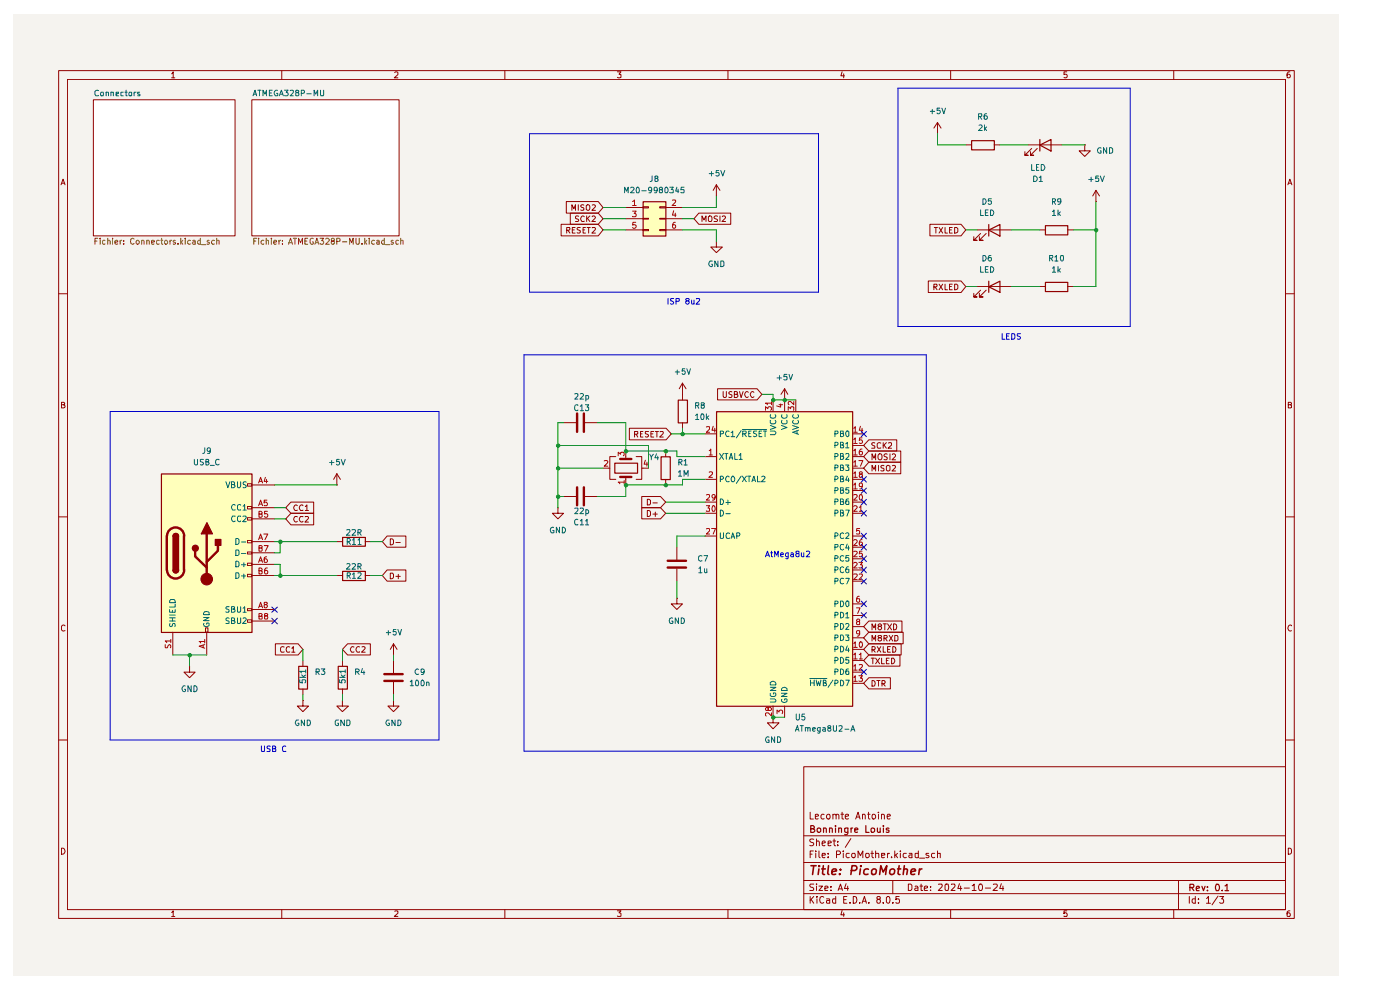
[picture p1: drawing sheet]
<svg xmlns="http://www.w3.org/2000/svg" width="297mm" height="210mm" viewBox="0 0 297 210" stroke-linecap="round" stroke-linejoin="round" font-family="sans-serif">
<path d="M2.9 3h281.2v203.8h-281.2z" fill="#f5f3ef"/>
<g fill="none" stroke="#910000" stroke-width=".21">
<path d="M12.4 15h262.2v179.8h-262.2zM14.3 16.8h258.4v176.2h-258.4zM36.4 15.7l.3-.5v1.3M36.4 16.5h.7M59.8 15v1.8M83.7 15.4l.2-.2h.3l.2 .2v.4l-.8 .7h.8M107.1 15v1.8M131 15.2h.7l-.4 .5 .4 .1v.6h-.7M154.4 15v1.8M178.6 15.2l-.2 .9h.8M179 15.7v.8M201.7 15v1.8"/>
<path d="M226.3 15.2h-.6v.6l.4-.1 .3 .3-.1 .4h-.6M249 15v1.8M273.6 15.2l-.4 .1-.2 .3v.8h.6v-.6l-.4-.1-.2 .3M13 39.2l.4-1.2 .4 1.2M13.1 38.9h.6M273.2 39.2l.4-1.2 .5 1.2M273.3 38.9h.6M12.4 62.3h1.9M272.7 62.3h1.9M13 85.8h.5l.2-.3-.2-.2h-.5v1.2h.5l.3-.4-.3-.3M273.3 85.8h.5l.2-.3-.2-.2h-.5v1.2h.5l.2-.1v-.4l-.3-.2M12.4 109.6h1.9"/>
<path d="M272.7 109.6h1.9M13.8 132.8l-.4-.2-.4 .3 .1 .8 .3 .2 .4-.1M274 132.8l-.2-.2a.6 .6 0 0 0-.6 .7 .6 .6 0 0 0 .8 .5M12.4 157h1.9M272.7 157h1.9M13 179.9a.65 .65 0 0 1 .8 .6 .65 .65 0 0 1-.8 .7zM170.5 162.6h102.2v30.4h-102.2zM170.5 177.3h102.2M171.9 172.3v1.4h.6M172.6 178.1h-.7l-.1 .3 .2 .2 .5 .1 .1 .4-.3 .3-.5-.1M173 173.2l.6-.1v-.3h-.6v.8h.6M173.2 178.6l.2-.2 .3 .1 .1 .9"/>
<path d="M173.2 178v1.4M174.4 178.9l.7-.2-.2-.3-.4 .1-.1 .7 .3 .2 .3-.1M174.8 172.8l-.4-.1a.6 .6 0 0 0 0 1l.4-.1M175.7 178.9l.7-.2-.1-.2h-.6v.8h.6M176.7 172.9l.1-.1a.36 .36 0 0 1 .6 .2v.7M176.7 178.4h.6M176.7 172.7v1M177 178v1.2l.3 .2M177.4 173v-.2a.36 .36 0 0 1 .6 .2v.7M177.7 179.2v.2M177.7 178.5v.1M178.4 172.7h.6"/>
<path d="M178.6 172.3v1.3l.4 .1M179.3 173.2l.7-.1v-.3l-.4-.1-.3 .3 .1 .6h.6M180.5 177.9l-1.2 1.8M181.5 173.7l.5-1.4 .5 1.4M181.7 173.3h.7M183 172.9l.1-.2 .4 .1 .1 .9M183 172.7v1M184.1 172.7h.5M184.2 172.3v1.2l.4 .2M186.3 172.3v.1M186.3 172.7v1M187 172.9v-.1a.36 .36 0 0 1 .6 .2v.7"/>
<path d="M187 172.7v1M188.2 173.2l.7-.1-.2-.4-.4 .1-.1 .7 .2 .2 .4-.1M273.3 179.9l.5 .1 .2 .3v.5l-.4 .4h-.3zM36.4 193.5l.3-.3v1.2M36.4 194.4h.7M59.8 193v1.8M83.7 193.3h.7v.4l-.8 .7h.8M107.1 193v1.8M131 193.2h.7l-.4 .4 .4 .2v.5h-.7M154.4 193v1.8M170.5 189.6h102.2M170.5 186.8h102.2"/>
<path d="M170.5 183h102.2M171.9 190.2v1.4M171.9 181.2h.4M172 190.8l.6 .8M172.5 180.5h-.6v1.4M172.6 187.5l-.7 .1v.4l.6 .3 .1 .3-.1 .3h-.7M172.6 190.2l-.7 .8M173.1 180.5v.2M173.1 181v.9M173.2 187.5v.1M173.2 188v.9M173.3 190.2v.1"/>
<path d="M173.3 190.7v.9M173.7 188h.8l-.8 .9h.8M173.7 180.5v1.2l.3 .2M174.4 181.4h.7l-.1-.4h-.5l-.1 .2 .1 .7h.5M174.7 190.3l-.4-.1a.7 .7 0 0 0-.4 .8 .7 .7 0 0 0 .8 .5v-.1M175 188.5l.7-.2-.1-.3h-.6v.9h.6M175.3 190.7h.6l.1 .9M175.7 181.8v.1M175.7 181v.2M176 191l-.7 .1v.4h.7M176.3 188.8v.1M176.3 188v.2"/>
<path d="M177.3 190.7h-.6l-.1 .2 .1 .6h.6M177.3 190.2v1.4M177.5 181.3h.6l.2-.3v-.2l-.2-.3h-.6v1.4M177.8 188.9l.5-1.4 .4 1.4M178 188.5h.6M178.6 193.1l-.2 1h.8M178.9 180.5v.2M178.9 181v.9M179 193.6v.8M179 190.8h.5M179.5 187.4l-.3 1.1h.8M179.7 190.2h-.7v1.4h.7"/>
<path d="M179.8 188v.9M180.2 181h-.5l-.2 .3v.4l.2 .2h.5M180.3 191.4v.2M180.8 181.1l.6-.1v.9a.45 .45 0 0 1-.7-.2zM181 190.2h.4a.75 .75 0 0 1 .4 .8 .75 .75 0 0 1-.8 .6zM182 181.9v-1.4l.5 1 .5-1v1.4M182.4 191.4v.2M182.9 191.6l.5-1.4 .4 1.4M183 191.2h.7M183.7 181h.5l.2 .7a.45 .45 0 0 1-.7 .2zM184.3 191.4v.2M184.7 181h.6"/>
<path d="M185 180.5v1.2l.3 .2M185.8 181.1l.5-.1 .1 .9M185.8 180.5v1.4M186.3 190.8l-.3-.3 .3-.3h.4v.5a.56 .56 0 0 0-.6 .2 .56 .56 0 0 0 0 .6h.6l.1-.5-.3-.2M187 181.4h.7l-.1-.4h-.6v.9h.6M187.4 191.4v.2M188 190.4l.4-.2a.8 .8 0 0 1 .4 .7 .8 .8 0 0 1-.4 .7l-.4-.3zM188.3 181v.9M188.7 181h-.3l-.1 .3M189.1 181.8v.1M189.4 191.4v.2M189.4 186.8v2.8"/>
<path d="M189.8 180.5v1.4M190 181.4l.4 .5M190.4 181l-.6 .5M190.8 190.2h-.7v.6l.1-.1 .6 .1v.7l-.6 .1-.1-.2M191 180.5v.2M191 181v.9M192.3 181h-.5l-.2 .3v.4l.3 .2h.4M192.7 187.5h.5l.3 .4v.6l-.3 .4h-.5zM192.9 181h.6v.9M193.5 181.4h-.5l-.2 .2 .2 .3h.5M194.1 188h.4l.2 .2v.7h-.6v-.4l.6-.2M194.8 181l-.7 .1v.7l.3 .1h.4"/>
<path d="M194.8 180.5v1.4M195.1 182h1.1M195.2 188h.5M195.4 187.5v1.4h.3M196.1 188.5l.7-.2v-.3h-.5l-.2 .2 .1 .7h.6M197 181h-.5l-.1 .2 .6 .3v.4h-.6M197.4 188.8v.1M197.4 188v.2M198.3 181h-.5l-.2 .3v.4l.3 .2h.4M198.9 181.1l.6-.1v.9M198.9 180.5v1.4M199.1 187.6l.7-.1 .1 .4-.9 1h.9"/>
<path d="M200.6 187.6h.6v.8l-.1 .5h-.4l-.2-.3zM201.7 193v1.8M201.8 187.6l.7-.1 .1 .4-.8 1h.8M203.5 187.4l-.3 1.1h.8M203.8 188v.9M204.6 188.4h1.1M206.2 187.9l.5-.4v1.4M206.2 188.9h.9M207.9 187.5a.73 .73 0 0 1 .6 .6 .73 .73 0 0 1-.3 .8h-.3l-.3-.5zM209 188.4h1.1M210.7 187.6l.7-.1 .2 .4-.1 .2-.9 .8h1M212.4 187.4l-.3 1.1h.8"/>
<path d="M212.8 188v.9M226.3 193.2h-.6v.6l.2-.2 .4 .1v.7l-.6-.1M249 193v1.8M250 186.8v6.2M252.3 190.2v1.4M253.6 190.7h-.5l-.2 .2v.4l.2 .3 .5-.1M253.6 190.2v1.4M254.3 191.4v.2M254.3 190.7v.1M255.9 190.6l.5-.4v1.4M255.9 191.6h.9M258.4 190.1l-1.3 1.8"/>
<path d="M258.7 190.2h.9l-.4 .5 .3 .1v.7l-.6 .1-.2-.2M273.6 193.2l-.6 .3v.8l.6 .1v-.7l-.4-.1-.2 .3"/>
<circle cx="175.7" cy="173.3" r=".48"/>
<circle cx="185.4" cy="173.3" r=".48"/>
</g>
<g fill="none" stroke="#910000" stroke-width=".25">
<path d="M172 175.8l.7-.1 .1-.3-.3-.3h-.5v1.5h.5l.3-.3v-.2l-.3-.3M173.4 175.7l.5-.1 .2 .3v.4l-.2 .3h-.3l-.2-.3zM174.7 175.7l.4-.1 .2 .2v.8M174.7 175.6v1M176 175.7l.4-.1 .2 .2v.8M176 175.6v1M177.2 175.1v.2M177.2 175.6v1M177.9 175.7h.6v.9M177.9 175.6v1M179.9 175.6l-.1 1.3-.3 .2-.3-.1M179.9 175.7h-.7v.7l.2 .2 .5-.1"/>
<path d="M180.5 175.6v1M180.9 175.6l-.4 .1v.2M181.3 176.1l.7-.1-.2-.4-.5 .2v.6l.3 .2 .3-.1M183.7 175.1v1.5h.7M184.9 175.7h.6v.6a.45 .45 0 0 1-.6 .2zM186.1 175.6v.8l.2 .2 .4-.2M186.7 175.6v1M187.4 175.1v.2M187.4 175.6v1M188.6 175.7l-.3-.1-.3 .2 .1 .3h.5v.4h-.6M252.4 188.3h.7l.2-.3-.1-.3-.8-.1v1.3M252.8 188.3l.5 .6"/>
<path d="M253.8 188.5l.7-.2-.2-.3-.4 .1-.1 .7 .1 .1h.5M255 188l.3 .9 .3-.9M256.2 188.8v.1M256.2 188.1v.2M258 187.6a.73 .73 0 0 1 .8 .5 .73 .73 0 0 1-.4 .8h-.4l-.2-.5zM259.3 188.8v.1M259.9 187.9l.4-.3v1.3M259.9 188.9h.7"/>
</g>
<g fill="none" stroke="#910000" stroke-width=".34">
<path d="M172 183.6h1.1M172.6 183.6l-.2 1.9M173.7 184.3l-.1 1.2M173.8 183.6l-.1 .2 .2-.1-.1-.1-.1 .2M174.3 184.3h.8M174.7 183.6l-.2 1.6 .4 .3M175.8 183.6l-.2 1.6 .2 .3M176.5 184.9l1-.2-.1-.3a.6 .6 0 0 0-.9 .2v.8h.8M178.1 185.3v.2M178.3 184.4v.2M180.6 184.7l.9-.1 .3-.3-.1-.5-.3-.2h-.6l-.3 1.9M182.5 184.3l-.1 1.2"/>
<path d="M182.6 183.6v.2M184.2 184.4a.65 .65 0 0 0-.9 .3v.6a.64 .64 0 0 0 .8 .1M184.9 184.7l.4-.4 .5 .1 .1 .3-.1 .5a.56 .56 0 0 1-.9 .1zM186.6 185.5l.3-1.9 .5 1.4 .7-1.4-.2 1.9M188.9 184.5l.3-.2 .5 .2v.8l-.4 .2-.5-.2zM190.4 184.3h.7M190.8 183.6l-.3 1.6 .4 .3M191.7 184.5l.3-.2 .4 .1v1.1M191.9 183.6l-.3 1.9M193.3 184.9l.9-.2-.1-.3a.6 .6 0 0 0-.8 .2v.8h.8M195.1 184.3l-.2 1.2M195.6 184.3l-.4 .1-.1 .3"/>
</g>
<g fill="#fff">
<path d="M53.4 21.2h31.3v28.8h-31.3z"/>
<path d="M19.8 21.2h30.1v28.8h-30.1z"/>
</g>
<g fill="#ffb">
<path d="M136.4 42.8h4.8v7.2h-4.8z"/>
<path d="M34.2 100.5h19.2v33.6h-19.2z"/>
<path d="M152 87.3h28.8v62.5h-28.8z"/>
</g>
<g fill="none" stroke="#910000" stroke-width=".21">
<path d="M19.8 21.2h30.1v28.8h-30.1zM53.4 21.2h31.3v28.8h-31.3zM152 39.2l-.7 1.2M152 39.2v2.4M152 39.2l.7 1.2M198.9 28.4h.1M198.9 26l-.8 1.2M198.9 26v2.4M198.9 26l.7 1.2M204.9 30.7h1.2M210.9 30.7h1.2M218.1 30.7h7.2"/>
<path d="M218.9 31.5l-1.5 1.4h.7h-.7v-.7M220 31.5l-1.4 1.4h.7h-.7v-.7M230.1 30.7v1.3h1.2l-1.2 1.2-1.2-1.2h1.2M230.1 30.7h.1M119 47.6h7.9l1 1.2-1 1.2h-7.9zM120.1 42.8h6.8l1 1.2-1 1.2h-6.8zM120.2 48.8h.6v-.5h-.6v1.1M120.5 48.8l.4 .6M121 45.2h5.9l1 1.2-1 1.2h-5.9zM121.3 44.6v-1.2l.4 .9 .4-.9v1.2M121.4 48.8h.4M122 48.3h-.6v1.1h.6"/>
<path d="M122.7 43.4v1.2M122.8 45.9l-.5-.1-.2 .2v.3l.7 .3-.2 .4h-.5M123.1 48.3h-.5l-.2 .1 .2 .4 .5 .1v.4l-.2 .1h-.5M123.7 48.8h.3M123.9 43.5l-.5-.1-.2 .3 .2 .3 .5 .2v.3h-.7M123.9 46l-.2-.2a.67 .67 0 0 0-.5 .5 .67 .67 0 0 0 .2 .7l.5-.1M124.2 48.3h-.5v1.1h.5M124.4 43.6l.5-.2a.65 .65 0 0 1 .3 .7 .65 .65 0 0 1-.6 .5l-.2-.2zM124.5 45.8v1.2M124.5 48.3h.7M124.6 46.3l.5 .7M124.9 48.3v1.1"/>
<path d="M125.1 45.8l-.6 .7M125.6 48.3h.6l.1 .3-.7 .8h.7M125.6 46l.5-.2 .2 .3-.7 .9h.7M125.6 43.5l.5-.1 .2 .4-.7 .8h.7M132.8 48.8h3.6M132.8 44h3.6M132.8 46.4h3.6M136.4 48.7h1.2v.2h-1.2zM136.4 46.3h1.2v.2h-1.2zM136.4 43.9h1.2v.2h-1.2zM140 48.7h1.2v.2h-1.2zM140 46.3h1.2v.2h-1.2z"/>
<path d="M140 43.9h1.2v.2h-1.2zM141.2 48.8h3.6M141.2 44h3.6M141.2 46.4h3.6M148.2 45.2h6.8v2.4h-6.8l-1-1.2zM148.9 47v-1.2l.4 .8 .5-.8v1.2M150.3 46l.5-.2a.86 .86 0 0 1 .1 1.2h-.5l-.1-.2zM152 51.2v1.2h1.2l-1.2 1.2-1.2-1.2h1.2M152 51.2h.1M152 41.6h.1M152.2 45.9l-.5-.1-.2 .3 .1 .2 .5 .2 .1 .3-.1 .2h-.6M152.7 45.8v1.2"/>
<path d="M153.2 46l.5-.2 .2 .3-.7 .9h.7M196.9 59.6h7l1 1.2-1 1.3h-7zM197.3 47.6h6.6l1 1.2-1 1.2h-6.6zM198.2 48.3h.7M198.5 48.3v1.1M199.2 48.3l.8 1.1M200 48.3l-.8 1.1M200.5 48.3v1.1h.5M201.4 48.8h.4M202 48.3h-.6v1.1h.6M202.5 48.3h.4l.3 .2v.6l-.4 .3h-.3zM207.3 48.8h7.2"/>
<path d="M208 49.5l-1.4 1.5h.7h-.7v-.8M209.2 49.5l-1.4 1.5h.7h-.7v-.8M220.6 48.8h1.1M226.5 48.8h1.2M232.5 42.8h.1M232.5 40.4l-.7 1.2M232.5 40.4v2.4M232.5 40.4l.8 1.2M198.1 60.9l.6-.1v-.5h-.6v1.2M198.4 60.9l.4 .6M199.2 60.3l.8 1.2M200 60.3l-.8 1.2"/>
<path d="M200.5 60.3v1.2h.5M201.4 60.8h.4M202 60.3h-.6v1.2h.6M202.5 60.3h.4l.3 .2v.6l-.4 .4h-.3zM207.3 60.8h7.2M208 61.5l-1.4 1.5h.7h-.7v-.8M209.2 61.5l-1.4 1.5h.7h-.7v-.8M220.6 60.8h1.1M226.5 60.8h1.2M152.2 82.5h8.4l1 1.1-1 1.2h-8.4zM153.4 83.1v1l.3 .2 .4-.1v-1.1M155.3 83.1h-.4l-.3 .2 .1 .3 .6 .2v.4l-.2 .1-.5-.1"/>
<path d="M155.8 83.6h.6v-.5h-.6v1.2h.5l.2-.4-.3-.3M156.9 83.1l.3 1.2 .4-1.2M158.7 83.2l-.2-.1a.65 .65 0 0 0-.5 .6 .65 .65 0 0 0 .5 .6l.2-.1M159.9 83.2l-.2-.1a.65 .65 0 0 0-.5 .6 .65 .65 0 0 0 .5 .6l.2-.1M166.5 84.8h.1M166.5 82.5l-.8 1.1M166.5 82.5v2.3M166.5 82.5l.6 1.1M184.3 93.3h5.9v2.4h-5.9l-1.1-1.2zM184.3 95.7h6.8v2.3h-6.8l-1.1-1.1zM184.3 98h6.8v2.5h-6.8l-1.1-1.2zM185 97.5v-1.2l.4 .9 .4-.9v1.2"/>
<path d="M185 99.9v-1.2l.4 .9 .4-.9v1.2M185.6 94l-.4-.1-.3 .2 .3 .4 .4 .2v.3l-.7 .1M186.3 98.7v1.2M186.4 96.3h.5a.86 .86 0 0 1 0 1.2 .46 .46 0 0 1-.6-.4zM186.9 94h-.1a.45 .45 0 0 0-.7 .1v.7l.2 .3 .6-.1M187.4 93.9v1.2M187.5 98.8l-.4-.1-.2 .3 .2 .3 .4 .2v.3h-.6M187.5 94.4l.5 .7M188 98.9l.3-.2 .5 .2v.8l-.3 .2-.5-.2zM188 93.9l-.6 .7M188.2 96.3h-.4l-.3 .2 .2 .4 .5 .1v.4l-.2 .1-.5-.1M188.5 94h.6v.4l-.7 .7h.7"/>
<path d="M188.8 96.3v1.2M189.3 96.4l.4-.1 .3 .4-.8 .8h.8M189.3 98.8l.4-.1 .3 .4-.8 .8h.8M52.5 119.5h.9v.5h-.9zM52.5 117.1h.9v.4h-.9zM52.5 114.6h.9v.5h-.9zM52.5 109.8h.9v.5h-.9zM52.5 107.4h.9v.5h-.9zM52.5 102.6h.9v.5h-.9zM61.7 108.9h4.8v2.4h-4.8l-1.1-1.2zM61.7 106.5h4.8v2.4h-4.8l-1.1-1.2zM63.1 109.6h-.5a.67 .67 0 0 0-.3 .6 .67 .67 0 0 0 .5 .5l.3-.1"/>
<path d="M63.1 107.3l-.3-.2a.67 .67 0 0 0-.5 .5 .67 .67 0 0 0 .3 .7l.5-.1M64.3 109.6h-.5a.66 .66 0 0 0-.3 .7 .66 .66 0 0 0 .6 .4l.2-.1M64.3 107.3l-.2-.2a.66 .66 0 0 0-.6 .5 .66 .66 0 0 0 .3 .7l.5-.1M64.8 109.6h.5l.1 .3-.7 .8h.7M64.8 107.4l.3-.3v1.2M64.8 108.3h.6M43.6 133.2h.5v.9h-.5zM52.5 131.5h.9v.5h-.9zM52.5 129.1h.9v.4h-.9zM52.5 121.8h.9v.5h-.9zM184.3 134.1h7.3v2.5h-7.3l-1.1-1.3zM184.3 138.9h6.6v2.4h-6.6l-1.1-1.2z"/>
<path d="M184.3 131.7h7v2.4h-7l-1.1-1.2zM184.3 136.6h6.9v2.3h-6.9l-1.1-1.2zM184.8 139.6h.7M185 136v-1.2l.4 .8 .4-.8v1.2M185 133.6v-1.3l.4 .9 .4-.9v1.3M185 137.8l.6-.1v-.5h-.6v1.1M185.2 139.6v1.2M185.2 137.8l.5 .5M185.8 139.6l.8 1.2M186.1 137.2l.8 1.1M186.5 135.3l-.2-.3 .1-.2h.5l.1 .2-.2 .3h-.4l-.1 .2 .2 .5h.3l.2-.3-.2-.4M186.5 132.8l-.2-.2 .2-.3h.3l.2 .4-.7 .4v.2l.2 .3h.3l.2-.3v-.2l-.2-.3"/>
<path d="M186.6 139.6l-.8 1.2M186.9 137.2l-.8 1.1M187 139.6v1.2h.6M187.4 137.2v1.1h.5M187.4 132.3h.6M187.5 135.4l.6-.1 .1-.3-.2-.2h-.5v1.2M187.7 132.3v1.3M187.8 135.4l.4 .6M188.3 132.3l.8 1.3M188.3 137.7h.4M188.6 139.6h-.6v1.2h.6M188.6 134.8l.8 1.2"/>
<path d="M188.9 137.2h-.6v1.1h.6M189.1 139.6h.5a.66 .66 0 0 1 .2 .8 .66 .66 0 0 1-.7 .4zM189.1 132.3l-.8 1.3M189.4 137.2a.66 .66 0 0 1 .7 .4 .66 .66 0 0 1-.3 .7h-.4zM189.4 134.8l-.8 1.2M189.6 132.3a.64 .64 0 0 1 .7 .7 .64 .64 0 0 1-.7 .6zM189.8 134.8h.5l.2 .2v.7l-.3 .3h-.4zM184.3 143.8h4.6v2.3h-4.6l-1.1-1.2zM185 144.4a.66 .66 0 0 1 .6 .4 .66 .66 0 0 1-.2 .7h-.4zM186 144.4h.7M186.3 144.4v1.1M187.1 145l.6-.1v-.5h-.6v1.1"/>
<path d="M187.4 145l.4 .5M188 140.1h.4"/>
</g>
<path d="M206.1 29.8h4.8v2h-4.8zM220.6 30.8l2.4-1.2v2.4zM220.6 29.6v2.4M136.4 42.8h4.9v7.3h-4.9zM209.8 48.8l2.3-1.2v2.5zM209.8 47.6v2.5M209.8 59.6v2.4M221.8 47.9h4.7v1.9h-4.7zM221.8 59.9h4.7v1.9h-4.7zM209.8 60.8l2.3-1.2v2.4zM34.2 100.5h19.3v33.7h-19.3zM36.7 120.9a.59 .59 0 0 0 .6 .6 .59 .59 0 0 0 .6-.6" fill="none" stroke="#910000" stroke-width=".25"/>
<path d="M134.2 42.8l.4-.4v1.2M134.2 44.8h.8l-.5 .5 .5 .2v.3l-.2 .2-.6-.1M134.2 43.6h.8M134.9 47.2h-.6l-.1 .5h.7l.1 .5-.3 .2h-.3l-.2-.1M142.7 42.5l.6-.1v.4l-.7 .8h.7M142.9 44.7l-.2 .9h.7M143.3 47.2a.72 .72 0 0 0-.6 .5 .72 .72 0 0 0 .2 .7l.4-.1v-.4a.35 .35 0 0 0-.3-.2 .35 .35 0 0 0-.3 .2M143.3 45.2v.8" fill="none" stroke="#b90000" stroke-width=".21"/>
<path d="M35.4 120.9a1.82 1.82 0 0 0 1.9 1.8 1.82 1.82 0 0 0 1.8-1.8" fill="none" stroke="#910000" stroke-width=".51"/>
<path d="M36.7 120.9h1.2a.59 .59 0 0 1-.6 .6 .59 .59 0 0 1-.6-.6z" fill="#910000"/>
<path d="M36.7 113.7h1.2v7.2h-1.2z" fill="none" stroke="#910000" stroke-width=".25"/>
<path d="M36.7 113.7h1.2v7.2h-1.2z" fill="#910000"/>
<path d="M36.7 113.7a.59 .59 0 0 1 .6-.5 .59 .59 0 0 1 .6 .5" fill="none" stroke="#910000" stroke-width=".25"/>
<path d="M36.9 113.3a.59 .59 0 0 1 .6-.1 .59 .59 0 0 1 .4 .5h-1.2z" fill="#910000"/>
<path d="M35.4 113.7a1.82 1.82 0 0 1 1.9-1.8 1.82 1.82 0 0 1 1.8 1.8" fill="none" stroke="#910000" stroke-width=".51"/>
<circle cx="41.4" cy="116.3" r=".64" fill="none" stroke="#910000" stroke-width=".25"/>
<circle cx="41.4" cy="116.3" r=".64" fill="#910000"/>
<circle cx="43.9" cy="122.8" r="1.23" fill="none" stroke="#910000" stroke-width=".21"/>
<circle cx="43.9" cy="122.8" r="1.23" fill="#910000"/>
<path d="M35.4 113.7v7.2M39 113.7v7.2M41.4 116.8v1.2l2.5 2.4M43.9 113.2v9.6M46.2 115.7v1.1l-2.3 2.4" fill="none" stroke="#910000" stroke-width=".51"/>
<path d="M43.9 110.9l1.2 2.3h-2.4z" fill="none" stroke="#910000" stroke-width=".25"/>
<path d="M43.9 110.9l1.2 2.3h-2.4z" fill="#910000"/>
<path d="M45.7 114.4h1.2v1.3h-1.2z" fill="none" stroke="#910000" stroke-width=".25"/>
<path d="M45.7 114.4h1.2v1.3h-1.2z" fill="#910000"/>
<g fill="none" stroke="#910000" stroke-width=".21">
<path d="M119.5 89.7h2.7M124.1 89.7h2.6M127.9 99.3h1.5M130.6 96.9h-1.2v4.8h1.2M132.8 95.7v1.7M133.5 90.8h7.8l1.1 1.2-1.1 1.3h-7.8zM134.6 92.1l.7-.1v-.4l-.7-.1v1.2M135 96.9h1.1v4.8h-1.1M135 92.1l.3 .6M135.9 92h.3M136.1 99.3h1.5M136.4 91.5h-.5v1.2h.5"/>
<path d="M137.6 91.5h-.6l-.1 .4a.57 .57 0 0 1 .6 .7h-.6M138.1 92h.4M138.7 91.5h-.6v1.2h.6M139 91.5h.7M139.4 91.5v1.2M140 91.6l.6-.1 .1 .4-.7 .8h.7M141.2 95.7v1.2M144.8 83.6h.1M144.8 81.3l-.7 1.2M144.8 81.3v3.5M144.8 89.7v1.1M144.8 81.3l.7 1.2"/>
<path d="M149.6 92h2.4M149.6 96.9h2.4M164 84.8v2.5M166.5 84.8v2.5M168.8 84.8v2.5M180.8 92h2.4M180.8 99.3h2.4M180.8 96.9h2.4M180.8 94.5h2.4M53.4 102.9h4.8M53.4 107.7h4.8M53.4 119.7h4.8"/>
<path d="M53.4 114.9h4.8M53.4 110.1h4.8M53.4 117.3h4.8M71.5 102.9h.1M71.5 114.9h1.1M71.5 100.5l-.7 1.2M71.5 100.5v2.4M71.5 100.5l.7 1.2M77.5 114.9h1.2M82.1 113.7h4v2.4h-4l-1-1.2zM82.8 114.3l.5 .1 .2 .2v.6l-.4 .4h-.3zM84 115.1h.9"/>
<path d="M118.4 107.7v1.2h1.1l-1.1 1.2-1.2-1.2h1.2M118.4 107.7h.1M119.5 105.3h2.7M124.1 105.3h2.6M132.8 101.2v1.7M136.1 107.7h4l1.1 1.2-1.1 1.2h-4zM136.1 105.3h4l1.1 1.2-1.1 1.2h-4zM137.3 108.3h.4l.3 .3v.6l-.3 .4h-.4zM137.3 105.9h.4l.3 .3v.6l-.2 .3h-.5zM138.5 109h.9M138.5 106.7h.9M139 108.6v1"/>
<path d="M141.2 101.7v1.2M143.6 116.1v2.7M149.6 101.7h2.4M149.6 106.5h2.4M149.6 108.9h2.4M149.6 113.7h2.4M180.8 101.7h2.4M180.8 104.1h2.4M180.8 106.5h2.4M180.8 108.9h2.4M180.8 118.5h2.4M180.8 116.1h2.4"/>
<path d="M180.8 113.7h2.4M36.7 134.1v4.8M43.9 134.1v4.8M53.4 129.3h4.8M53.4 122.1h4.8M53.4 131.7h4.8M58.4 136.6h4.8l1.1 1.1-1.1 1.2h-4.8zM60.3 137.2h-.4l-.4 .3v.6l.2 .2h.6M61.5 137.2h-.3a.67 .67 0 0 0-.5 .5 .67 .67 0 0 0 .3 .6h.5M61.9 137.5h.2l.1-.3v1.1M61.9 138.3h.7M71.5 122.1h1.1"/>
<path d="M73.7 136.6h4.9v2.3h-4.9l-1.1-1.2zM75.1 137.2h-.3a.67 .67 0 0 0-.5 .5 .67 .67 0 0 0 .3 .6h.5M76.3 137.2h-.2a.66 .66 0 0 0-.6 .4 .66 .66 0 0 0 .3 .7h.5M76.8 137.2h.4l.3 .3-.8 .8h.8M77.5 122.1h1.2M82.1 120.9h4v2.4h-4l-1-1.2zM82.8 121.6h.5l.2 .2v.6l-.4 .4h-.3zM83.5 138.9h.1M83.5 136.6l-.7 1.1M83.5 136.6v2.3M83.5 136.6l.7 1.1M84 122.3h.9"/>
<path d="M84.5 121.8v1M143.6 126.9v1.2h1.2l-1.2 1.2-1.2-1.2h1.2M143.6 126.9h.1M143.6 120.6v2.7M180.8 137.7h2.4M180.8 123.3h2.4M180.8 120.9h2.4M180.8 128.1h2.4M180.8 130.6h2.4M180.8 132.9h2.4M180.8 135.3h2.4M40.2 141.3v1.3h1.2l-1.2 1.2-1.2-1.2h1.2"/>
<path d="M40.2 141.3h.1M64.3 148.6v1.2h1.1l-1.1 1.2-1.2-1.2h1.2M64.3 148.6h.1M64.3 140.1v1.2M64.3 146.1v1.2M72.6 148.6v1.2h1.3l-1.3 1.2-1.1-1.2h1.1M72.6 148.6h.1M72.6 140.1v1.2M72.6 146.1v1.2M83.5 148.6v1.2h1.2l-1.2 1.2-1.2-1.2h1.2M83.5 148.6h.1M83.5 140.1v2.6"/>
<path d="M83.5 144.7v2.6M164 152.1v1.2h1.3l-1.3 1.3-1.2-1.3h1.2M164 152.1h.1M164 149.8v2.3M166.5 149.8v2.3M180.8 140.1h2.4M180.8 142.6h2.4M180.8 144.9h2.4"/>
</g>
<g fill="none" stroke="#006665" stroke-width=".21">
<path d="M20.9 19.2h-.1a.46 .46 0 0 0-.7 .2v.7l.2 .2 .6-.1M21.4 19.6h.5l-.1 .7h-.4zM22.5 19.6h.4l.1 .7M22.5 19.6v.7M23.5 19.6h.5v.7M23.5 19.6v.7M24.6 20l.5-.2v-.2h-.5v.7h.5M26.2 19.6h-.5v.6l.5 .1M26.5 19.6h.5M26.8 19.1v1.2h.2M27.4 19.6h.5v.7h-.5zM28.4 19.6v.7"/>
<path d="M28.9 19.6h-.3l-.2 .2M29.6 19.6h-.4v.3l.4 .1 .1 .1-.1 .2h-.4M53.8 20h.6M54.7 19.1h.7M55 19.1v1.2M57.1 19.7h.5M57.7 19.1h-.6v1.2h.6M58.8 19.2a.59 .59 0 0 0-.7 .4 .59 .59 0 0 0 .3 .7l.5-.1v-.4h-.2M59.4 20h.5M60.4 19.1h.7l-.4 .5 .4 .2v.3l-.1 .2-.6-.1M61.5 19.2h.7v.4l-.7 .7h.7M62.9 19.6h-.2v-.4h.6v.4l-.6 .2 .1 .5h.4l.2-.2v-.2l-.2-.3"/>
<path d="M63.9 19.8l.6-.1v-.5l-.6-.1v1.2M65.1 19.9h.9M68 19.1l.1 1.2h.5l.1-.2v-1M53.7 20.3l.4-1.2 .3 1.2M55.8 20.3v-1.2l.4 .9 .4-.9v1.2M59.3 20.3l.4-1.2 .4 1.2M66.6 20.3v-1.2l.4 .9 .4-.9v1.2M152.7 96.2l.8 1.2M152.8 92l.6-.1 .1-.3-.2-.2h-.5v1.2M153.5 96.2l-.8 1.2M153.8 96.2h.6M154.1 96.2v1.2"/>
<path d="M154.7 97.4l.4-1.2 .3 1.2M154.7 91.5l-.5-.1a.67 .67 0 0 0-.3 .7 .67 .67 0 0 0 .5 .5l.3-.1M154.8 97.1h.6M155.1 91.8l.3-.4v1.2M155.1 92.6h.8M155.9 96.2v1.2h.6M156.8 96.6l.3-.4v1.2M156.8 97.4h.7M157.2 91.4l-1 1.5M157.5 91.1h5.1M157.6 92l.6-.1 .1-.3-.1-.2h-.6v1.2M157.9 92l.4 .6"/>
<path d="M158.8 91.9h.4M159.3 91.4h-.5v1.2h.5M160.5 91.4h-.6l-.1 .2 .1 .3 .5 .2v.4h-.6M161 91.9h.5M161.6 91.4h-.6v1.2h.6M162 91.4h.6M162.3 91.4v1.2M163.4 91.4h.9l.3 .3v.2l-.3 .3h-.9M163.4 90.3l1.2 .4-1.2 .4M163.5 89.2l-.1 .5 .3 .2 .7-.1 .2-.2-.2-.4M163.5 88l-.1 .5a.67 .67 0 0 0 .7 .2 .67 .67 0 0 0 .5-.5l-.2-.2M165.8 90.3l1.2 .4-1.2 .4"/>
<path d="M165.9 89.2a.45 .45 0 0 0 .1 .7h.7l.3-.2-.1-.5M165.9 88l-.1 .2a.67 .67 0 0 0 .5 .5 .67 .67 0 0 0 .7-.2l-.1-.5M168.1 90.3l1.3 .4-1.3 .4M168.3 89.2l-.2 .4 .4 .3h.6l.2-.2 .1-.3-.2-.2M168.3 88l-.2 .2a.65 .65 0 0 0 .7 .5 .65 .65 0 0 0 .6-.5l-.2-.2M169.1 91.4v.6M169.4 91.3l-1.3 .4 1.3 .4M177.1 92l.6-.1 .1-.3-.2-.2h-.5v1.2M177.1 94.5h.4l.3-.3-.1-.3-.6-.1v1.2M177.1 96.9l.6-.1 .1-.4-.3-.2h-.4v1.2M177.1 99.2h.5l.2-.1-.1-.4-.6-.1v1.2M178.3 91.9h.5l.1-.4-.6-.1v1.2l.6-.1 .1-.3-.3-.3"/>
<path d="M178.3 94.4h.4l.2-.2v-.3l-.6-.1v1.2h.6l.1-.3-.3-.3M178.3 96.8h.5l.1-.5-.2-.1h-.4v1.2h.6l.1-.4-.3-.2M178.3 99.2h.4l.2-.1v-.4l-.2-.1h-.4v1.2l.6-.1 .1-.3-.3-.2M179.4 94.1l.3-.3v1.2M179.4 96.3l.2-.1h.3l.2 .1v.5l-.7 .6h.7M179.4 98.6h.7l-.4 .5 .4 .1v.5h-.7M179.4 95h.7M179.6 91.4h.3l.2 .2v.8l-.2 .1a.6 .6 0 0 1-.6-.4 .6 .6 0 0 1 .3-.7zM47.9 102.2l.4 1.3 .5-1.3M49.1 102.8h.6v-.5l-.6-.1v1.3h.5l.3-.5-.4-.2M49.9 107.2l-.2-.2a.66 .66 0 0 0-.6 .5 .66 .66 0 0 0 .3 .7l.5-.1M49.9 109.6l-.5-.1a.66 .66 0 0 0-.3 .7 .66 .66 0 0 0 .6 .5l.2-.2"/>
<path d="M50 119h.4l.3 .4v.6l-.2 .2h-.5zM50 114.2l.5 .1 .2 .3v.5l-.3 .4h-.4zM50 116.7h.5l.2 .2v.7l-.3 .3h-.4zM50.4 102.2v1.1l.1 .2h.3l.3-.3v-1M51.1 107.2l-.4-.2-.3 .4v.5l.1 .3 .6-.1M51.1 109.6l-.6-.1-.1 .2 .1 .8 .2 .2 .4-.2M51.2 119.8h1M51.2 115h1M51.2 117.4h1M51.6 107.4l.3-.4v1.2M51.6 109.6l.6-.1v.3l-.7 .9h.7M51.6 108.2h.6"/>
<path d="M51.7 119.4v.8M52.2 102.3h-.6v.5l.6 .2v.2l-.2 .3-.4-.1M152.8 101.7h.4l.3-.4-.3-.3h-.4v1.2M152.8 113l.1 1.2h.4l.2-.2v-1M152.8 105.8a.66 .66 0 0 1 .7 .5 .66 .66 0 0 1-.3 .7h-.4zM152.8 108.2a.64 .64 0 0 1 .7 .6 .64 .64 0 0 1-.7 .7zM154 106.6h.9M154 109h.9M154.4 106.1v.9M154.7 101.2l-.3-.2a.67 .67 0 0 0-.5 .5 .67 .67 0 0 0 .3 .7l.5-.1M154.8 113.2l-.3-.2a.67 .67 0 0 0-.5 .5 .67 .67 0 0 0 .3 .7l.5-.1M155.1 114.2l.3-1.2 .5 1.2"/>
<path d="M155.2 113.9h.6M155.3 101.1l.1-.1a.61 .61 0 0 1 .5 .7 .61 .61 0 0 1-.6 .5l-.2-.4zM156.3 113.7l.6-.1v-.5l-.6-.1v1.2M157.2 101l-1 1.5M157.5 101l.8 1.2M158.3 101l-.8 1.2M158.6 101h.7M158.9 101v1.2M159.5 102.2l.4-1.2 .4 1.2M159.6 101.9h.6M160.7 101v1.2h.6M161.6 101.2l.4-.2 .3 .3-.8 .9h.8"/>
<path d="M177.1 101.7h.4l.3-.4-.3-.3h-.4v1.2M177.1 104.1l.6-.1 .1-.4-.2-.1h-.5v1.1M177.1 106.4h.5l.2-.1-.1-.4-.6-.1v1.2M177.1 108.9h.4l.3-.4-.3-.3h-.4v1.3M177.1 118.4h.5l.2-.1-.1-.4h-.6v1.1M177.1 116.1l.6-.1 .1-.3-.2-.2h-.5v1.2M177.1 113.7h.4l.3-.2-.3-.5h-.4v1.2M178.3 101.6l.6-.1v-.3l-.2-.2h-.4v1.2h.6l.1-.3-.3-.3M178.3 104h.5l.1-.5h-.6v1.1h.6l.1-.4-.3-.2M178.3 106.4h.4l.2-.1v-.4l-.6-.1v1.2h.6l.1-.4-.3-.2M178.3 108.8l.6-.1v-.3l-.2-.2h-.4v1.3l.6-.1 .1-.4-.3-.2M179 117.9h-.3a.6 .6 0 0 0-.5 .5 .6 .6 0 0 0 .5 .6h.3"/>
<path d="M179 115.6l-.5-.1a.67 .67 0 0 0-.3 .7 .67 .67 0 0 0 .5 .5l.3-.2M179 113.2l-.3-.2a.67 .67 0 0 0-.5 .5 .67 .67 0 0 0 .3 .7l.5-.1M179.4 108.2h.8l-.5 1.3M179.4 113.2l.2-.2h.3l.2 .2v.3l-.7 .7h.7M179.7 101l-.3 .9h.8M179.7 115.4l-.3 .8h.8M180 105.8l-.4 .1a.94 .94 0 0 0 0 1.1l.5-.1v-.5l-.4-.1-.3 .2M180 101.4v.8M180 115.8v.9M180.1 103.5h-.6l-.1 .5h.7v.5l-.2 .1h-.3l-.2-.1M180.1 117.9h-.6l-.1 .5 .2-.1h.3l.2 .1v.6h-.7M36 129.3v.6h1.2v-.6"/>
<path d="M36 131.7h1.2M36 131.1h1.2M36 130.5h1.2M36.1 132.2l-.1 .5 .2 .2 .3-.1 .2-.6h.4v.7M36.1 127.3l.1-.1h.7l.3 .3v.3h-1.2zM36.6 129.5v.4M36.6 131.1v.6M37.2 128.2v.6h-1.2M43.2 131h1.2l-1.2 .7h1.2M43.3 132.2l-.1 .1a.66 .66 0 0 0 .5 .6 .66 .66 0 0 0 .7-.2l-.1-.5h-.4v.2M43.3 129.8h.9l.2 .2v.4h-1.2zM48.6 128.7h-.5l-.2 .2 .2 .3 .5 .3v.3h-.7"/>
<path d="M48.6 131.1h-.6a.57 .57 0 0 0 .6 .7l-.1 .4h-.6M49.1 129.2h.6v-.5h-.6v1.2h.5l.3-.4-.4-.3M49.1 131.7l.6-.1v-.5h-.6v1.1h.6l.2-.3-.4-.2M50 121.5h.5l.2 .2v.6l-.3 .4h-.4zM50.4 128.7v1.1l.1 .1 .5-.1 .1-.2v-.9M50.4 131.1l.1 1.1h.4l.2-.1v-1M51.2 122.2h1M51.6 129l.3-.3v1.2M51.6 131.1h.4l.2 .3-.7 .8h.7M51.6 129.9h.6M51.7 121.7v1M177.1 137.7h.4l.3-.2-.1-.3-.6-.1v1.2"/>
<path d="M177.1 123.3h.5l.2-.5-.2-.1h-.5v1.2M177.1 120.9h.4l.3-.4-.3-.3h-.4v1.3M177.1 128.1l.6-.1 .1-.3-.2-.2h-.5v1.2M177.1 130.5h.5l.2-.2-.1-.3-.6-.1v1.2M177.1 132.9h.4l.3-.4-.3-.3h-.4v1.3M177.1 135.3l.6-.1 .1-.3-.2-.2h-.5v1.2M178.3 137.1a.66 .66 0 0 1 .7 .4 .66 .66 0 0 1-.3 .8h-.4zM178.3 139.4a.64 .64 0 0 1 .7 .7 .64 .64 0 0 1-.7 .6zM178.3 127.5h.4a.66 .66 0 0 1 .3 .8 .66 .66 0 0 1-.7 .4zM178.3 129.9l.6 .1 .1 .4-.1 .5-.3 .2h-.3zM178.3 132.2a.64 .64 0 0 1 .7 .7 .64 .64 0 0 1-.7 .6zM178.3 134.7h.4a.66 .66 0 0 1 .3 .8 .66 .66 0 0 1-.7 .4z"/>
<path d="M179 122.8l-.5-.1a.61 .61 0 0 0-.3 .8 .61 .61 0 0 0 .8 .3M179 120.4l-.3-.2a.65 .65 0 0 0-.5 .7 .65 .65 0 0 0 .5 .6l.3-.2M179.4 122.7h.8l-.5 1.2M179.4 130.2l.3-.3v1.2M179.4 132.4l.2-.2h.3l.2 .2v.4l-.7 .7h.7M179.4 134.7h.7l-.4 .4 .4 .1v.6h-.7M179.4 131.1h.7M179.6 127.5h.3l.2 .2v.7l-.3 .3a.71 .71 0 0 1-.2-1.2zM179.7 137l-.3 .9h.8M180 120.2l-.4 .2-.2 .8 .3 .3 .4-.2-.1-.6h-.4l-.2 .2M180 137.5v.8M180.1 139.4h-.6l-.1 .6h.7v.5l-.2 .2h-.3l-.2-.2"/>
<path d="M163.4 148.2h.9l.3 .3-.2 .4h-1M163.4 147.1v.5l.3 .1h.6l.2-.1 .1-.4-.2-.2h-.3v.2M163.4 145.8h1.2l-1.2 .7h1.2M163.4 144.8a.66 .66 0 0 1 .8-.2 .66 .66 0 0 1 .4 .7h-1.2zM165.8 147.1h1.2l-1.2 .6h1.2M165.9 148.3l-.1 .1a.66 .66 0 0 0 .4 .6 .66 .66 0 0 0 .8-.2l-.1-.6h-.4v.3M165.9 146a.72 .72 0 0 1 1.1 0v.5h-1.2zM171.8 143.9h3.6M172 144.3v1.2M172 144.9h.7M172.7 144.3v1.2M173.1 144.3l.3 1.2 .2-.9 .3 .9 .3-1.2"/>
<path d="M174.7 144.9l.5-.1v-.4l-.5-.1v1.2h.5l.1-.4-.3-.2M176.7 144.3l-1 1.5M177.1 140.1l.6-.1 .1-.3-.3-.3h-.4v1.3M177.1 142.5h.5l.2-.2-.1-.3-.6-.1v1.2M177.1 144.9h.4l.3-.4-.3-.2h-.4v1.2M178.3 141.9l.6 .2 .1 .3-.1 .5-.3 .2h-.3zM178.3 144.3a.66 .66 0 0 1 .7 .4 .66 .66 0 0 1-.3 .8h-.4zM179.4 144.3h.8l-.5 1.2M180 141.9h-.3a.73 .73 0 0 0 0 1.2l.4-.1v-.5l-.4-.2-.3 .3"/>
</g>
<g fill="none" stroke="#b90000" stroke-width=".21">
<path d="M128.2 97.8l.6-.1 .1 .2v.3l-.7 .7h.7M131.1 96.7v-.8l.6 .4v-.3h.6l.1 .5-.2 .2M136.9 97.6l-.3 .9h.8M137.2 98v.9M149.9 90.6h.6v.4l-.6 .7h.6M150.4 95.6l.4-.4v1.3M150.4 96.5h.7M151.3 90.4l-.3 .9h.8M151.6 90.8v.9M162.4 87v-.7l.5 .4 .1-.3h.6l.1 .5-.2 .1M163.7 85.5h-1.3l.4 .3M163.7 85.2v.6"/>
<path d="M165.3 85.8h.7M165.6 85.7v.7l-.8-.3M167.2 87v-.7l.5 .4v-.3h.7l-.1 .6M168.4 85.2v.6l-.7-.6h-.3l-.2 .1v.4l.2 .1M181.1 90.8l.3-.3v1.2M181.1 93.2l.3-.3v1.2M181.1 95.6h.2l.1-.4v1.3M181.1 98l.3-.3v1.2M181.1 96.5h.8M181.1 91.7h.8M181.1 94.1h.8M181.1 98.9h.8"/>
<path d="M182.2 97.7h.8l-.5 1.2M182.5 90.4l-.2 .9h.7M182.9 92.9h-.5l-.1 .6 .2-.2 .4 .1v.6h-.6M182.9 95.2h-.3a.93 .93 0 0 0-.2 1.2h.5l.1-.5-.1-.1h-.5l-.1 .1M182.9 90.8v.9M54.9 102.4l.4-1.1 .4 1.1M54.9 107.3l.4-1.2 .4 1.2M54.9 119.3l.4-1.2 .4 1.2M54.9 114.5l.4-1.2 .4 1.2M54.9 109h.6l.1-.3-.2-.2h-.5v1.2h.6l.1-.1v-.4l-.2-.2M54.9 116.2h.6l.1-.3-.1-.2h-.6v1.2h.6l.1-.1v-.4l-.2-.2M55 102.1h.5"/>
<path d="M55 106.9h.5M55 119h.5M55 114.1h.5M56 113.3h.8l-.6 1.2M56 115.7h.9l-.6 1.2M56.3 101.3l-.3 .8h.8M56.6 118.1l-.6 .3v.8l.6 .1 .1-.2v-.3l-.2-.3h-.3l-.2 .3M56.6 101.7v.7M56.6 106.1h-.6v.6l.5-.2 .2 .3v.3l-.1 .2-.6-.1M56.7 108.5h-.6v.5h.6v.6l-.4 .1-.2-.1M132.4 102.3h-1.3l.4 .3M132.4 101.9v.7"/>
<path d="M149.9 112.2h.6v.4l-.6 .7h.6M149.9 105h.6v.4l-.6 .7h.6M149.9 107.3h.6l-.3 .5 .3 .1v.5h-.6M150.4 100.2h.7v.4l-.7 .7h.7M151 112.1h.8l-.5 1.2M151.3 107.3a.75 .75 0 0 1 .3 1.2h-.4l-.2-.5 .1-.6zM151.7 105.4l-.4 .3-.2-.1-.1-.4a.35 .35 0 0 1 .4-.3 .35 .35 0 0 1 .3 .3l-.1 .8-.5 .1M181.1 100.4l.3-.3v1.2M181.1 102.9l.3-.5v1.3M181.1 105l.5-.1 .3 .3-.8 .9h.8M181.1 107.4l.2-.1h.3l.3 .2-.8 1h.8M181.1 119.5l.2-.2h.3l.3 .2-.8 1h.8"/>
<path d="M181.1 117l.5-.1 .3 .3-.8 .9h.8M181.1 114.6l.2-.1h.3l.3 .2-.1 .4-.7 .6h.8M181.1 101.3h.8M181.1 103.7h.8M182.2 119.3h.8l-.5 .5h.4l.1 .2-.1 .5-.7-.1M182.3 107.6l.3-.3v1.2M182.3 108.5h.7M182.4 105l.3-.1a.78 .78 0 0 1 0 1.2l-.3-.1zM182.4 112.1h-.6l-.1 .6 .2-.2h.3l.2 .2v.5h-.7M182.5 100.6h-.1l-.1-.3a.35 .35 0 0 1 .3-.2 .35 .35 0 0 1 .4 .2l-.1 .3-.5 .1v.6h.5l.1-.2v-.3l-.3-.2M182.9 116.9h-.5l-.1 .6 .2-.2 .4 .1v.6h-.6M182.9 114.5a.72 .72 0 0 0-.6 .5 .72 .72 0 0 0 .2 .7h.4l.1-.5a.35 .35 0 0 0-.4-.2 .35 .35 0 0 0-.3 .2"/>
<path d="M183 103l-.1 .2h-.5l-.1-.2 .1-.5 .3-.1 .2 .2a.85 .85 0 0 1-.3 1.1h-.2M35 136.7l.1 .7h.4l.4-.7 .3 .3-.1 .4M36.2 136h-1.2l.4 .3M36.2 135.6v.7M43.1 136.8v.6M43.4 136.7l-1.2 .4 1.2 .4M43.4 136.1h-1.2l.4 .3M43.4 135.6v.8M54.9 128.9l.4-1.1 .4 1.1M54.9 121.1h.6l.1-.4-.2-.2h-.5v1.2h.6l.1-.1v-.4l-.2-.1M54.9 130.7h.5l.2-.2-.1-.3-.6-.1v1.2h.6l.1-.5-.2-.1M55 128.6h.5"/>
<path d="M56.2 128.3l-.2-.5h.6l.1 .2-.2 .3-.5 .1v.4l.2 .1h.3l.2-.2v-.3l-.2-.1M56.3 130.6h-.2v-.4h.6v.4l-.6 .1 .1 .6 .5-.1a.36 .36 0 0 0-.1-.6M56.7 120.5l-.4 .1-.2 .2v.8l.2 .1h.4v-.6l-.4-.1-.2 .2M181.1 136.5l.3-.4v1.2M181.1 138.9h.2l.1-.4v1.3M181.1 121.8l.6-.1 .2 .2-.1 .4-.7 .6h.8M181.1 137.3h.8M181.1 139.8h.8M181.7 128.9h.8l-.6 1.2M181.9 131.8l-.2-.2 .2-.3h.3l.2 .4-.5 .1-.2 .3 .2 .4 .5-.1v-.4l-.2-.2M182.3 138.9l.3-.4v1.3M182.3 121.8l.6-.1 .1 .4-.8 .8h.8"/>
<path d="M182.3 126.5l-.4 .2-.2 .8 .2 .3 .5-.2-.1-.6h-.4l-.2 .3M182.3 139.8h.7M182.4 136.2l.3-.1a.78 .78 0 0 1 0 1.2l-.3-.1zM182.4 134.3l-.1 .1h-.4l-.2-.1v-.4l.2-.1 .5 .1v.7l-.2 .3-.3 .1M163 150.3l.1-.3h.3l.3 .3-.2 .4h-.4l-.1-.4-.3-.3-.3 .3 .2 .4 .4-.2M163.7 151.2v.7l-.7-.7h-.4l-.2 .2v.3l.2 .2M164.8 151.4v-.8l.5 .4 .1-.3h.5v.7M181.1 141.3l.3-.3v1.2M181.1 143.7h.2l.1-.4v1.2M181.1 142.2h.8M181.1 144.5h.8M182.2 143.3h.8l-.5 .5h.4l.1 .2-.1 .5-.7-.1"/>
<path d="M182.3 141.1l.6-.1 .1 .3-.8 .9h.8"/>
</g>
<path d="M122.4 87.7v3.9M123.9 87.7v3.9M131.6 97.4h2.3M122.4 103.4v3.8M123.9 103.4v3.8M131.6 101.2h2.3M141.6 119h3.9M141.6 120.4h3.9M81.5 144.4h3.9M81.5 143h3.9" fill="none" stroke="#910000" stroke-width=".51"/>
<path d="M130.4 98.3h4.9v2.1h-4.9zM140.2 96.9h2v4.8h-2zM143.9 84.9h1.9v4.8h-1.9zM152 87.3h28.9v62.5h-28.9zM72.7 114h4.8v1.9h-4.8zM72.7 121.2h4.8v1.9h-4.8zM63.4 141.3h1.8v4.9h-1.8zM71.8 141.3h1.9v4.9h-1.9z" fill="none" stroke="#910000" stroke-width=".25"/>
<g fill="none" stroke="#090" stroke-width=".21">
<path d="M198.9 28.4v2.3h6M212.1 30.7h6M225.3 30.7h4.8M127.9 48.8h4.9M127.9 46.4h4.9M127.9 44h4.9M144.8 48.8h7.2v2.4M144.8 46.4h2.4M152 41.6v2.4h-7.2M204.9 48.8h2.4M214.5 48.8h6.1M227.7 48.8h4.8"/>
<path d="M232.5 42.8v18h-4.8M204.9 60.8h2.4M214.5 60.8h6.1M118.4 99.3h9.5M118.4 94.5h19.2v4.8M119.5 89.7h-1.1v18M126.7 89.7h6.1v6h10.8v1.2h6M142.4 92h7.2M144.8 90.8v1.2M161.6 83.6h2.4v1.2h4.8M58.2 102.9h13.3M58.2 114.9h13.3"/>
<path d="M58.2 119.7h1.2v2.4M58.2 110.1h2.4M58.2 107.7h2.4M59.4 114.9v2.4h-1.2M78.7 114.9h2.4M118.4 105.3h1.1M141.2 108.9h8.4M141.2 106.5h8.4M149.6 113.7h-6v2.4M149.6 101.7h-4.8v1.2h-12v2.4h-6.1M36.7 138.9h7.2M40.2 138.9v2.4"/>
<path d="M58.2 122.1h13.3M64.3 137.7v2.4M72.6 137.7v2.4M78.7 122.1h2.4M83.5 138.9v1.2M143.6 123.3v3.6M64.3 147.3v1.3M72.6 147.3v1.3M83.5 147.3v1.3M164 152.1h2.5"/>
</g>
<g fill="none" stroke="#0000ca" stroke-width=".21">
<path d="M190.5 18.7h49.3v50.6h-49.3zM112.3 28.4h61.3v33.6h-61.3zM111.2 75.3h85.3v84h-85.3zM141.7 63.3v1.2M142.9 63.3h-.6l-.1 .2 .1 .3 .5 .2v.4h-.6M143.4 63.9l.7-.1v-.4l-.7-.1v1.2M145.7 63.8l-.2-.3 .1-.2h.4l.2 .3-.7 .4v.3l.2 .2h.3l.2-.2v-.3l-.2-.2M146.7 63.7v.7l.4 .1 .1-.2M147.2 63.7v.8M147.7 63.4l.6-.1 .1 .4-.7 .8h.7M212.6 70.8v1.2h.6M213.5 71.3h.4"/>
<path d="M214.1 70.8h-.6v1.2h.6M214.6 70.8h.5l.2 .2v.6l-.3 .4h-.4zM216.5 70.8l-.7 .1v.3l.7 .4-.3 .4-.4-.1M23.4 87.3h69.7v69.7h-69.7zM162.4 118.1l.4-1.2 .4 1.2M162.6 117.8h.5M163.5 117.3h.4M163.7 116.9v1.1l.2 .1M164.3 118.1v-1.2l.5 .9 .3-.9v1.2M165.6 117.7l.6-.1-.2-.3-.4 .1v.5l.2 .2 .3-.1M167.2 117.3v1.1l-.2 .1-.3-.1M167.2 117.3h-.3l-.3 .2 .1 .5h.5"/>
<path d="M167.8 117.3h.3l.2 .1v.7M168.3 117.6h-.4l-.2 .2 .2 .3 .4-.1M169.1 117.4l-.3-.3 .2-.2h.4l.1 .4-.7 .3 .1 .4 .2 .1 .4-.1v-.5l-.2-.1M170 117.3v.6l.2 .2 .3-.1M170.5 117.3v.8M171.1 117l.5-.1 .2 .4-.8 .8h.8M55.5 158.2v1.2h.5l.1-1.2M57.3 158.3h-.6v.4a.47 .47 0 0 1 .5 .2 .47 .47 0 0 1 0 .5h-.6M57.8 158.8h.4l.3-.2-.1-.3-.6-.1v1.2h.6l.1-.5-.3-.1M60.6 158.3a.45 .45 0 0 0-.7 .2v.7l.2 .2 .5-.1"/>
</g>
<g fill="none" stroke="#765500" stroke-width=".21">
<path d="M20.1 51.1h.5M20.7 50.5h-.6v1.3M21.2 50.5v.2M21.2 51v.8M22.3 51.1l-.4-.1-.1 .1v.5l.1 .2 .4-.1M22.9 51.1l.1-.1 .4 .1v.7M22.9 50.5v1.3M23.9 50.5v.2M23.9 51v.8M24.4 51.4l.6-.1v-.2l-.4-.1-.2 .1 .1 .6h.5M25.5 51v.8M25.8 51l-.3 .2"/>
<path d="M26.2 51.6v.2M26.2 51.1h.1M28.4 50.7l-.2-.2a.65 .65 0 0 0-.5 .7 .65 .65 0 0 0 .5 .6l.2-.2M28.9 51.2l.4-.2 .2 .2v.4l-.4 .2-.2-.2zM30.1 51.1l.1-.1 .4 .1v.7M30.1 51v.8M31.2 51.1l.1-.1 .4 .1v.7M31.2 51v.8M32.2 51.4l.6-.1-.1-.2h-.5v.6h.5M33.8 51.1l-.4-.1-.2 .2 .1 .5h.5M34.1 51h.4M34.3 50.5v1.2l.2 .1"/>
<path d="M35.1 51l.5 .2v.4l-.3 .2-.4-.2v-.4zM36.1 51v.8M36.4 51l-.3 .2M37.2 51.1h-.5v.2l.4 .1 .2 .2-.2 .2-.4-.1M37.8 51.6v.2M38.4 50.5v1.3M38.4 51.3l.4 .5M38.8 51l-.4 .5M39.3 50.5v.2M39.3 51v.8M40.4 51.1l-.4-.1-.2 .2v.4l.2 .2 .4-.1M40.9 51.1h.5v.7"/>
<path d="M41.4 51.3l-.6 .2 .3 .3 .3-.1M42.5 51.1l-.3-.1-.3 .2v.4l.3 .2 .3-.1M42.5 50.5v1.3M42.8 51.9h.9M44.4 51.1l-.3-.1-.2 .2 .5 .4-.1 .2-.4-.1M45.5 51.1l-.4-.1-.2 .2v.4l.2 .2 .4-.1M46 51.1l.1-.1 .4 .1v.7M46 50.5v1.3M53.8 51.1h.5M54.4 50.5h-.6v1.3M54.9 50.5v.2M54.9 51v.8"/>
<path d="M56 51.1l-.4-.1-.2 .2v.4l.2 .2 .4-.1M56.5 51.1l.1-.1 .4 .1v.7M56.5 50.5v1.3M57.6 50.5v.2M57.6 51v.8M58.1 51.4l.6-.1-.2-.3-.4 .1v.5l.1 .2 .4-.1M59.2 51v.8M59.5 51l-.3 .2M59.9 51.6v.2M59.9 51.1h.1M61.2 51.8l.4-1.3 .5 1.3M61.3 51.5h.6"/>
<path d="M62.2 50.5h.7M62.6 50.5v1.3M63.3 51.8v-1.3l.5 1 .4-1v1.3M64.7 51.1h.4M65.3 50.5h-.6v1.3h.6M66.5 50.6l-.4-.1-.3 .4v.6l.2 .2h.5v-.4h-.2M66.8 51.8l.4-1.3 .4 1.3M67 51.5h.6M67.9 50.5h.8l-.5 .6 .5 .2-.1 .4-.5 .1-.2-.2M69.1 50.7l.2-.2h.3l.2 .3v.3l-.7 .7h.7M70.5 51.1h-.1a.31 .31 0 0 1 0-.5 .31 .31 0 0 1 .5 .1v.4h-.5l-.1 .2v.3l.2 .2 .4-.2v-.5h-.2M71.5 51.2l.6-.1v-.4l-.1-.2h-.5v1.3"/>
<path d="M72.6 51.3h1M74.2 51.8v-1.3l.4 1 .3-1v1.3M75.5 50.5v1.1l.3 .2 .4-.2v-1.1M76.8 51.6v.2M77.4 50.5v1.3M77.5 51.3l.3 .5M77.8 51l-.4 .5M78.3 50.5v.2M78.3 51v.8M79.4 51.1l-.3-.1-.3 .2v.4l.3 .2 .3-.1M79.9 51.1h.5v.7M80.4 51.3l-.5 .1v.3h.5"/>
<path d="M81.5 51.1l-.3-.1-.3 .2v.4l.3 .2 .3-.1M81.5 50.5v1.3M81.8 51.9h.9M83.4 51.1l-.3-.1-.1 .2 .5 .4-.2 .2-.3-.1M84.5 51.1l-.3-.1-.2 .1v.5l.2 .2 .3-.1M85 51.1l.2-.1 .3 .1v.7M85 50.5v1.3"/>
</g>
<g fill="none" stroke="#00008a" stroke-width=".21">
<path d="M182.7 91.5l1.1 1.1M183.8 91.5l-1.1 1.1M182.7 101.1l1.1 1.2M182.7 103.5l1.1 1.1M182.7 117.9l1.1 1.2M182.7 105.9l1.1 1.2M182.7 108.3l1.1 1.2M182.7 113.1l1.1 1.2M182.7 115.5l1.1 1.2M183.8 101.1l-1.1 1.2M183.8 103.5l-1.1 1.1M183.8 117.9l-1.1 1.2"/>
<path d="M183.8 105.9l-1.1 1.2M183.8 108.3l-1.1 1.2M183.8 113.1l-1.1 1.2M183.8 115.5l-1.1 1.2M57.7 128.8l1.1 1.1M57.7 131.1l1.1 1.2M58.8 128.8l-1.1 1.1M58.8 131.1l-1.1 1.2M182.7 127.5l1.1 1.2M182.7 122.8l1.1 1.1M182.7 120.3l1.1 1.2M182.7 130l1.1 1.1"/>
<path d="M183.8 127.5l-1.1 1.2M183.8 122.8l-1.1 1.1M183.8 120.3l-1.1 1.2M183.8 130l-1.1 1.1M182.7 142l1.1 1.1M183.8 142l-1.1 1.1"/>
</g>
<g fill="#090">
<circle cx="132.8" cy="102.9" r=".47"/>
<circle cx="141.3" cy="102.9" r=".47"/>
<circle cx="118.4" cy="105.4" r=".47"/>
<circle cx="132.8" cy="95.7" r=".47"/>
<circle cx="118.4" cy="94.5" r=".47"/>
<circle cx="118.4" cy="99.4" r=".47"/>
<circle cx="59.5" cy="114.9" r=".47"/>
<circle cx="59.5" cy="122.1" r=".47"/>
<circle cx="141.3" cy="95.7" r=".47"/>
<circle cx="144.8" cy="92.1" r=".47"/>
<circle cx="166.5" cy="84.9" r=".47"/>
<circle cx="164" cy="84.9" r=".47"/>
<circle cx="232.5" cy="48.8" r=".47"/>
<circle cx="40.3" cy="139" r=".47"/>
<circle cx="164" cy="152.2" r=".47"/>
</g>
<g fill="none" stroke="#006665" stroke-width=".21">
<path d="M133.8 39.9l.1-.2h.4l.2 .3-.7 .9h.7M135.2 39.7a.75 .75 0 0 1 .3 1.2h-.4l-.1-.4v-.6zM138.3 37.3v1.1l-.4 .1M139.1 37.8h-.2v-.4h.6v.4l-.6 .1v.5l.2 .1h.3l.2-.2-.2-.5M141.3 39.7a.71 .71 0 0 1 .3 1.2h-.4l-.1-.2v-.7zM142.1 39.7h.7l-.4 .5 .4 .1v.5h-.7M143.6 39.7l-.3 .9h.7M145.1 39.7h-.6l-.1 .6 .6-.1 .1 .6h-.7M150.4 36.8h1M151 36.4v.9M152.5 36.1h-.5l-.1 .6h.6v.6h-.6M152.9 36.1l.4 1.2 .5-1.2"/>
<path d="M197.4 23.6h.9M197.8 23.2v.9M199.4 22.9h-.6v.5h.6l.1 .5-.3 .2-.4-.1M199.8 22.9l.4 1.2 .4-1.2M207.6 24.7l.7-.1v-.4l-.7-.1v1.2M207.7 26.6l.4-.1 .3 .3-.8 .9h.8M207.9 24.7l.4 .6M208.9 26.5v1.2M209 27.3l.3 .4M209.3 24.1h-.3l-.2 .3v.8a.42 .42 0 0 0 .5 0 .42 .42 0 0 0 .1-.6h-.4l-.2 .2M209.3 26.9l-.4 .4M218.9 34.9v1.2h.6"/>
<path d="M219.3 37.3a.61 .61 0 0 1 .8 .6 .61 .61 0 0 1-.8 .6zM219.9 35.5h.3M220.4 34.9h-.5v1.2h.5M220.5 37.7l.3-.4v1.2M220.5 38.5h.6M220.9 34.9a.65 .65 0 0 1 .8 .6 .65 .65 0 0 1-.8 .6zM231 38.1h.9M231.5 37.6v.9M233.1 37.3h-.6l-.1 .6 .2-.1h.3l.2 .1v.5h-.7M233.4 37.3l.4 1.2 .5-1.2M233.6 31.4a.55 .55 0 0 0-.8 .5 .55 .55 0 0 0 .8 .5v-.4h-.2M234.8 31.3v1.2l-.7-1.2v1.2"/>
<path d="M235.4 31.3h.3l.3 .3v.7l-.3 .2h-.3zM132.5 40.9v-1.2l.4 .9 .4-.9v1.2M136.1 40.5h1M138.3 40.2a.35 .35 0 0 1-.4 .3 .35 .35 0 0 1-.3-.3l.1-.4h.5v.8l-.2 .3h-.3M139.4 40.2l-.2 .3-.4-.1v-.5l.4-.2a.81 .81 0 0 1 0 1.2h-.3M140.1 40.2h-.1a.31 .31 0 0 1 0-.4 .31 .31 0 0 1 .5 .1v.3h-.4l-.2 .3 .1 .4h.5v-.4l-.2-.3M143.8 40.1v.8M151.1 55.4h-.5a.61 .61 0 0 0-.2 .7 .61 .61 0 0 0 .7 .4v-.5h-.1M152.3 55.4v1.2l-.7-1.2v1.2M152.9 55.4h.5l.2 .2v.7l-.4 .3h-.3zM208 56.6v1.1h.6M208 44.5v1.2h.6"/>
<path d="M208.5 54.2h.5a.66 .66 0 0 1 .2 .7 .66 .66 0 0 1-.7 .5zM208.5 42.2h.5a.66 .66 0 0 1 .2 .7 .66 .66 0 0 1-.7 .4zM209 57.1h.5M209 45.1h.5M209.6 56.6h-.6v1.1h.6M209.6 44.5h-.6v1.2h.6M210.1 56.6a.66 .66 0 0 1 .7 .4 .66 .66 0 0 1-.2 .7h-.5zM210.1 44.5a.66 .66 0 0 1 .7 .5 .66 .66 0 0 1-.2 .7h-.5zM210.2 54.2l-.4 .1a.82 .82 0 0 0 .1 1.1l.4-.2v-.5l-.4-.1-.3 .3M210.3 42.2h-.6l-.1 .5h.7v.5l-.2 .1h-.3l-.2-.1M222.7 54.8l.6-.1v-.5h-.6v1.2M222.9 54.8l.4 .6"/>
<path d="M223.3 44.9l.3-.4v1.2M223.3 56.9l.3-.3v1.1M223.3 42.8l.6-.1v-.4l-.1-.1h-.5v1.1M223.3 45.7h.6M223.3 57.7h.6M223.5 42.8l.4 .5M223.8 54.5l.3-.3v1.2M223.8 55.4h.6M224.4 44.5v1.2M224.4 56.6v1.1M224.6 45.3l.4 .4M224.6 57.3l.4 .4"/>
<path d="M225 45l-.6 .4M225 57l-.6 .4M225 42.7v.1h-.6v-.6h.6v.8l-.1 .3h-.5M225 54.3l.1-.1a.59 .59 0 0 1 .6 .3 .59 .59 0 0 1-.2 .7l-.1 .2-.4-.2zM143.3 78.9h.9M143.7 78.5v.9M145.3 78.2h-.5l-.1 .5h.6v.6l-.4 .1-.2-.2M145.7 78.2l.4 1.2 .4-1.2M165.4 79.7v.9M167 79.4h-.6l-.1 .5h.7v.6h-.7M167.4 79.4l.3 1.2 .4-1.2M41.2 97.4v1l.3 .2 .4-.1v-1.1"/>
<path d="M43.2 97.4l-.7 .1v.4l.7 .4-.3 .3-.4-.1M43.4 95v.8l-.1 .4h-.3M43.7 98h.5v-.6h-.5v1.2h.4l.3-.4-.4-.2M44.6 95.5l-.2 .3-.4-.1v-.6l.4-.1 .2 .2v.7l-.2 .3h-.4M44.6 98.7h.9M46.5 97.5l-.5-.1a.67 .67 0 0 0-.3 .7 .67 .67 0 0 0 .5 .5l.3-.1M69.9 98.1h1M70.4 97.7v.9M72 97.4h-.5l-.1 .6h.6v.5l-.5 .1-.1-.1M72.4 97.4l.4 1.2 .4-1.2M121.9 83.6h.7v.4l-.7 .7h.7M122.6 86l-.3-.2-.4 .4 .1 .7 .3 .2 .3-.2"/>
<path d="M123.1 83.6l.4-.1 .3 .3-.8 .9h.8M123.1 86.2l.3-.4v1.3M123.1 87.1h.7M124.2 85.8h.7l-.4 .6h.4v.5l-.2 .2h-.3l-.2-.2M124.3 84.7l.5-.1 .1-.5-.2-.2h-.4v1.2M137.8 96.3l.4 .6 .4-.6M138.2 96.9v.6M139.3 96.3l-.4 .8h.8M139.5 96.8v.7M144 98h.6l.1-.4-.2-.2h-.5v1.2M144.3 98l.4 .6M145.1 97.8l.4-.4v1.2"/>
<path d="M145.1 98.6h.7M147.6 88.1l.3-.3v1.2M147.6 86l.6-.1v-.4l-.6-.1v1.2M147.6 89h.6M147.9 86l.3 .6M148.8 87.9l.3-.1a.86 .86 0 0 1 .1 1.2l-.4-.1zM148.9 85.9l-.1-.4 .5-.1 .1 .3-.2 .2-.4 .1v.5l.1 .1 .4-.1 .1-.1v-.3l-.2-.2M149.9 87.8v1.2M150 88.6l.4 .4M150.4 88.2l-.5 .4M164.8 80.2h1M73.6 119.6l.4-.1 .2 .4-.7 .8h.7"/>
<path d="M73.6 112.4l.6-.1v.4l-.7 .8h.7M73.7 114.9h.4l.2-.4-.2-.3h-.4v1.3M73.9 114.9l.4 .6M74.7 119.6l.5-.1 .2 .3-.7 .9h.7M74.7 112.4l.6-.1 .1 .2v.4l-.7 .6h.7M74.8 114.6l.3-.4v1.3M74.8 115.5h.6M75.9 112.9h.6l.1-.4-.1-.2h-.6v1.2M75.9 114.6l.4-.4v1.3M75.9 115.5h.7M76.2 112.9l.4 .6M117.4 111.9l-.1-.1a.66 .66 0 0 0-.5 .5 .66 .66 0 0 0 .2 .7l.5-.1v-.4h-.2"/>
<path d="M118.7 111.8v1.2l-.7-1.2v1.2M119.3 111.8a.66 .66 0 0 1 .6 .5 .66 .66 0 0 1-.2 .7h-.4zM121.9 107.9h.7v.4l-.7 .7h.7M122.6 110.2l-.3-.1-.4 .4v.6l.2 .2 .5-.1M123.1 107.9l.6-.1 .1 .3-.8 .9h.8M123.1 110.5l.3-.4v1.2M123.1 111.3h.7M124.2 110.5h.2l.1-.4v1.2M124.2 111.3h.7M124.3 108.2l.3-.1 .3 .3-.1 .5h-.5M124.3 108.1v1.3M143.9 100.2l.4-.4v1.2"/>
<path d="M143.9 101h.7M145.1 101v-1.2l.4 .9 .5-.9v1.2M148.9 117.9h-.2a.6 .6 0 0 0-.5 .5 .6 .6 0 0 0 .5 .6h.2M149.3 117.9h.8l-.5 1.1M73.7 122.1l.5-.1 .1-.3-.1-.2h-.5v1.2M73.9 122.1l.4 .6M74.8 121.8l.3-.3v1.2M74.8 122.7h.6M75.9 120.1h.6l.1-.1-.1-.4-.6-.1v1.2M75.9 121.6l.6-.1 .1 .3-.7 .9h.7M76.2 120.1l.4 .6M82 134.2h.9"/>
<path d="M82.4 133.8v.9M84 133.5h-.5l-.1 .5h.6v.6l-.4 .1-.2-.2M84.4 133.5l.4 1.2 .4-1.2M142.7 131.1h-.1a.66 .66 0 0 0-.6 .4 .66 .66 0 0 0 .2 .7h.5v-.5h-.2M143.9 131.1v1.1l-.6-1.1v1.1M144.5 131.1a.66 .66 0 0 1 .7 .4 .66 .66 0 0 1-.3 .7h-.4zM148.2 120.6l.4-.4v1.3M148.2 121.5h.7M149.4 120.6v.7l.2 .2 .3-.2M149.9 120.6v.9M39.3 145.5h-.1a.6 .6 0 0 0-.6 .6 .6 .6 0 0 0 .7 .5l.1-.4h-.3M40.6 145.5v1.2l-.7-1.2v1.2"/>
<path d="M41.1 145.5a.64 .64 0 0 1 .7 .6 .64 .64 0 0 1-.7 .6zM63.3 152.7h-.4a.67 .67 0 0 0-.3 .7 .67 .67 0 0 0 .6 .5l.2-.1v-.4h-.2M63.6 144.2v.6l.6 .1-.1-.6 .6-.1 .2 .2v.3l-.2 .2M63.6 143.7h1.3M64 143.2l.5 .5M64.6 152.7v1.2l-.7-1.2v1.2M64.9 142.4h-1.3l.3 .3M64.9 143.2l-.6 .3M64.9 142.1v.6M65.2 152.7h.4a.66 .66 0 0 1 .2 .8 .66 .66 0 0 1-.6 .4zM67.1 142.5h.5l.1-.5-.6-.1v1.2M67.3 142.5l.4 .6"/>
<path d="M68.2 141.9h.7l-.4 .4 .4 .3-.1 .4h-.6M71.8 152.7h-.5l-.2 .3v.6l.2 .2h.5v-.4h-.2M72 144.2v.6l.6 .1v-.7h.5v.7M72 143.7h1.2M72.4 143.2l.5 .5M73.1 152.7v1.2l-.8-1.2v1.2M73.2 142.4h-1.2l.4 .3M73.2 143.2l-.4 .3M73.2 142.1v.6M73.6 152.7h.5l.1 .3v.6l-.3 .3h-.3zM75.4 142.5h.6l.2-.2-.1-.3-.7-.1v1.2M75.8 142.5l.4 .6"/>
<path d="M76.9 141.8l-.3 .9h.8M77.2 142.3v.8M82.5 152.7h-.4a.67 .67 0 0 0-.2 .7 .67 .67 0 0 0 .5 .5l.2-.1v-.4h-.2M83.8 152.7v1.2l-.7-1.2v1.2M84.4 152.7h.4a.66 .66 0 0 1 .3 .8 .66 .66 0 0 1-.7 .4zM87 144.6l.4-.3v1.2M87 145.5h.7M88.4 144.3a.75 .75 0 0 1 .2 1.2h-.3l-.2-.5 .1-.6zM88.8 142a.55 .55 0 0 0-.8 .5 .55 .55 0 0 0 .8 .5M89.6 144.3a.71 .71 0 0 1 .2 1.2h-.3l-.2-.2v-.8zM90 142.4l-.3 .3-.4-.2v-.5l.4-.1a.73 .73 0 0 1 0 1.2h-.3M90.5 144.8l.3-.1 .2 .2v.6"/>
<path d="M90.5 144.7v.8M163.1 156.4l-.1-.1a.66 .66 0 0 0-.6 .5 .66 .66 0 0 0 .2 .7h.5v-.5h-.2M164.3 156.3v1.2l-.6-1.2v1.2M164.9 156.3l.5 .1 .2 .2v.6l-.2 .3h-.5zM168.7 155.1l.5-1.2 .3 1.2M168.8 154.8h.6M168.9 151.5v1l.3 .2 .4-.2v-1M169.8 153.9h.6M170.1 153.9v1.2M170.7 151.5h-.5l-.1 .6h.6v.6h-.4l-.2-.1M170.9 154.4l.4-.1 .1 .8M170.9 154.3v.8"/>
<path d="M171.4 154.5v-.2h.4l.1 .8M172.4 154.7l.6-.1-.1-.3h-.4l-.1 .2v.4l.1 .2 .4-.1M174 155h-.5l-.1-.5 .2-.2h.4v1l-.3 .2-.2-.1M174.6 154.3h.4l.1 .8M175.1 154.6l-.5 .1-.1 .2 .2 .2 .4-.1M175.8 154.4l-.2-.2a.35 .35 0 0 1 .3-.3 .35 .35 0 0 1 .4 .3l-.3 .2a.36 .36 0 0 0-.4 .4 .36 .36 0 0 0 .5 .3 .36 .36 0 0 0 .1-.6l-.2-.1M176.8 153.9v1l.2 .2 .5-.1v-1.1M178 154h.6v.4l-.6 .7h.6M179.2 154.7h.9M180.5 155.1l.4-1.2 .5 1.2M180.6 154.8h.6"/>
</g>
</svg>
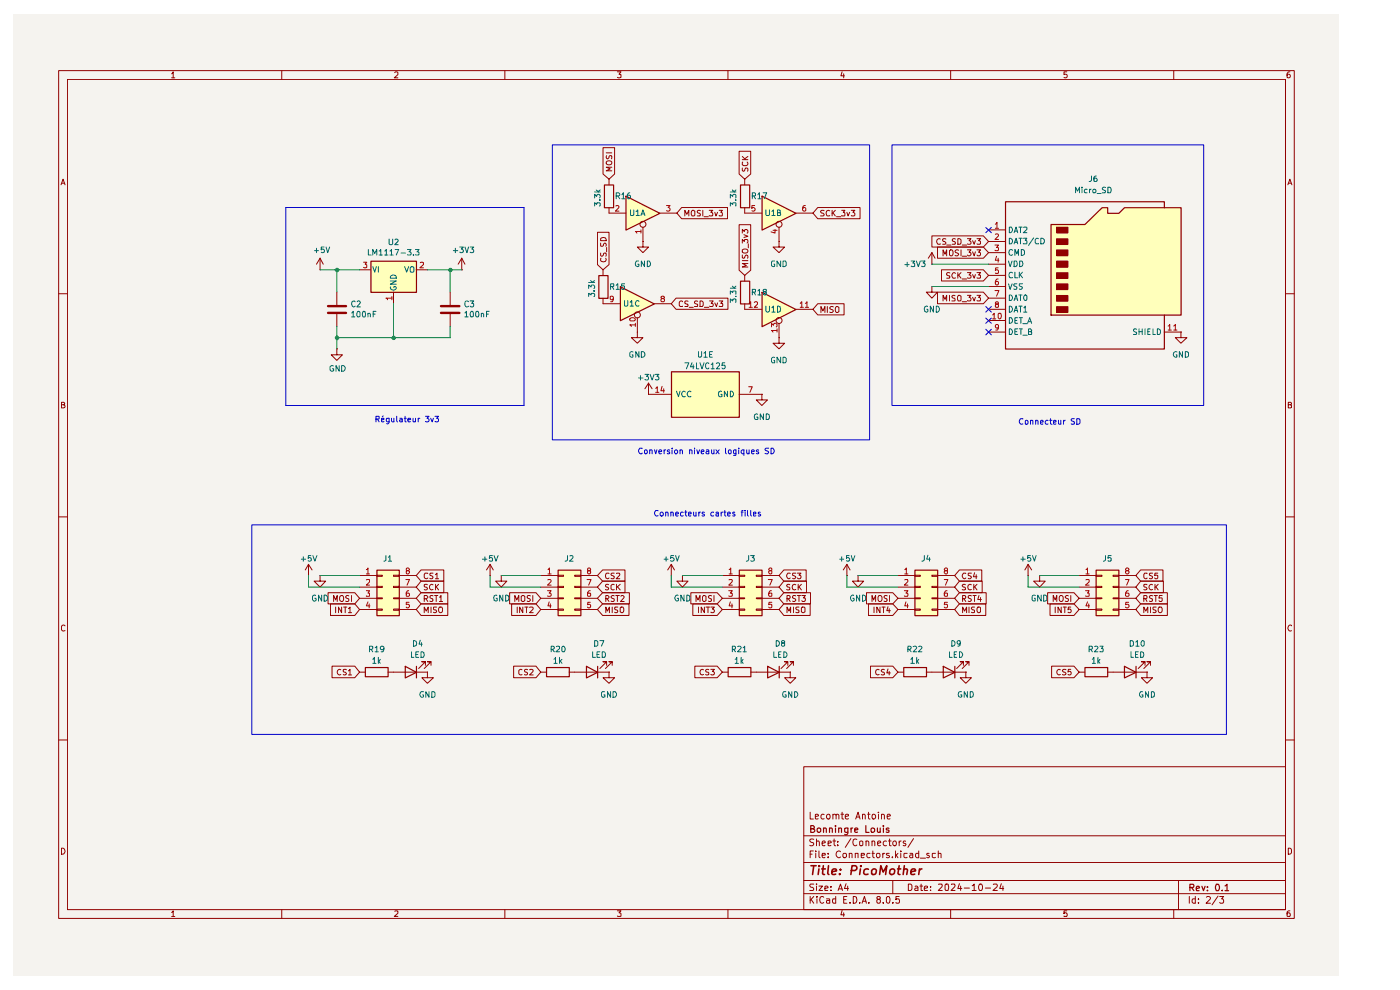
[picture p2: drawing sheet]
<svg xmlns="http://www.w3.org/2000/svg" width="297mm" height="210mm" viewBox="0 0 297 210" stroke-linecap="round" stroke-linejoin="round" font-family="sans-serif">
<path d="M2.9 3h281.2v203.8h-281.2z" fill="#f5f3ef"/>
<g fill="none" stroke="#910000" stroke-width=".21">
<path d="M12.4 15h262.2v179.8h-262.2zM14.3 16.8h258.4v176.2h-258.4zM36.4 15.7l.3-.5v1.3M36.4 16.5h.7M59.8 15v1.8M83.7 15.4l.2-.2h.3l.2 .2v.4l-.8 .7h.8M107.1 15v1.8M131 15.2h.7l-.4 .5 .4 .1v.6h-.7M154.4 15v1.8M178.6 15.2l-.2 .9h.8M179 15.7v.8M201.7 15v1.8"/>
<path d="M226.3 15.2h-.6v.6l.4-.1 .3 .3-.1 .4h-.6M249 15v1.8M273.6 15.2l-.4 .1-.2 .3v.8h.6v-.6l-.4-.1-.2 .3M13 39.2l.4-1.2 .4 1.2M13.1 38.9h.6M273.2 39.2l.4-1.2 .5 1.2M273.3 38.9h.6M12.4 62.3h1.9M272.7 62.3h1.9M13 85.8h.5l.2-.3-.2-.2h-.5v1.2h.5l.3-.4-.3-.3M273.3 85.8h.5l.2-.3-.2-.2h-.5v1.2h.5l.2-.1v-.4l-.3-.2M12.4 109.6h1.9"/>
<path d="M272.7 109.6h1.9M13.8 132.8l-.4-.2-.4 .3 .1 .8 .3 .2 .4-.1M274 132.8l-.2-.2a.6 .6 0 0 0-.6 .7 .6 .6 0 0 0 .8 .5M12.4 157h1.9M272.7 157h1.9M13 179.9a.65 .65 0 0 1 .8 .6 .65 .65 0 0 1-.8 .7zM170.5 162.6h102.2v30.4h-102.2zM170.5 177.3h102.2M171.9 172.3v1.4h.6M172.6 178.1h-.7l-.1 .3 .2 .2 .5 .1 .1 .4-.3 .3-.5-.1M173 173.2l.6-.1v-.3h-.6v.8h.6M173.2 178.6l.2-.2 .3 .1 .1 .9"/>
<path d="M173.2 178v1.4M174.4 178.9l.7-.2-.2-.3-.4 .1-.1 .7 .3 .2 .3-.1M174.8 172.8l-.4-.1a.6 .6 0 0 0 0 1l.4-.1M175.7 178.9l.7-.2-.1-.2h-.6v.8h.6M176.7 172.9l.1-.1a.36 .36 0 0 1 .6 .2v.7M176.7 178.4h.6M176.7 172.7v1M177 178v1.2l.3 .2M177.4 173v-.2a.36 .36 0 0 1 .6 .2v.7M177.7 179.2v.2M177.7 178.5v.1M178.4 172.7h.6"/>
<path d="M178.6 172.3v1.3l.4 .1M179.3 173.2l.7-.1v-.3l-.4-.1-.3 .3 .1 .6h.6M180.5 177.9l-1.2 1.8M181.5 173.7l.5-1.4 .5 1.4M181.7 173.3h.7M181.8 178.1l-.4-.1a.7 .7 0 0 0-.5 .8 .7 .7 0 0 0 .8 .5l.1-.1M182.5 178.5l.3-.1 .2 .2v.6l-.2 .2-.4-.2zM183 172.9l.1-.2 .4 .1 .1 .9M183 172.7v1M183.7 178.6v-.1a.36 .36 0 0 1 .6 .1v.8M183.7 178.4v1M184.1 172.7h.5"/>
<path d="M184.2 172.3v1.2l.4 .2M185 178.6l.2-.2 .3 .1 .1 .9M185 178.4v1M186.2 178.9l.7-.2-.2-.3-.4 .1-.1 .7 .2 .2 .4-.1M186.3 172.3v.1M186.3 172.7v1M187 172.9v-.1a.36 .36 0 0 1 .6 .2v.7M187 172.7v1M188 178.5l-.3-.1-.3 .3 .1 .6h.5M188.2 173.2l.7-.1-.2-.4-.4 .1-.1 .7 .2 .2 .4-.1M188.5 178.4h.6M188.7 178v1.3l.4 .1"/>
<path d="M190.8 178.4v1M191.2 178.4l-.4 .3M192.1 178.5l-.3-.1-.2 .2 .2 .3 .4 .2-.1 .2h-.5M193.8 177.9l-1.2 1.8M273.3 179.9l.5 .1 .2 .3v.5l-.4 .4h-.3zM36.4 193.5l.3-.3v1.2M36.4 194.4h.7M59.8 193v1.8M83.7 193.3h.7v.4l-.8 .7h.8M107.1 193v1.8M131 193.2h.7l-.4 .4 .4 .2v.5h-.7M154.4 193v1.8"/>
<path d="M170.5 189.6h102.2M170.5 186.8h102.2M170.5 183h102.2M171.9 190.2v1.4M171.9 181.2h.4M172 190.8l.6 .8M172.5 180.5h-.6v1.4M172.6 187.5l-.7 .1v.4l.6 .3 .1 .3-.1 .3h-.7M172.6 190.2l-.7 .8M173.1 180.5v.2M173.1 181v.9M173.2 187.5v.1"/>
<path d="M173.2 188v.9M173.3 190.2v.1M173.3 190.7v.9M173.7 188h.8l-.8 .9h.8M173.7 180.5v1.2l.3 .2M174.4 181.4h.7l-.1-.4h-.5l-.1 .2 .1 .7h.5M174.7 190.3l-.4-.1a.7 .7 0 0 0-.4 .8 .7 .7 0 0 0 .8 .5v-.1M175 188.5l.7-.2-.1-.3h-.6v.9h.6M175.3 190.7h.6l.1 .9M175.7 181.8v.1M175.7 181v.2M176 191l-.7 .1v.4h.7"/>
<path d="M176.3 188.8v.1M176.3 188v.2M177.3 190.7h-.6l-.1 .2 .1 .6h.6M177.3 190.2v1.4M177.8 188.9l.5-1.4 .4 1.4M178 188.5h.6M178.3 180.7a.63 .63 0 0 0-.9 .5 .63 .63 0 0 0 .9 .6M178.6 193.1l-.2 1h.8M178.9 181.1h.6l.1 .6-.3 .2h-.2l-.3-.2zM179 193.6v.8M179 190.8h.5M179.5 187.4l-.3 1.1h.8"/>
<path d="M179.7 190.2h-.7v1.4h.7M179.8 188v.9M180.2 181.1l.5-.1 .1 .9M180.2 181v.9M180.3 191.4v.2M181 190.2h.4a.75 .75 0 0 1 .4 .8 .75 .75 0 0 1-.8 .6zM181.4 181.1l.6-.1v.9M181.4 181v.9M182.4 191.4v.2M182.7 181.4h.7l-.1-.4h-.6v.9h.6M182.9 191.6l.5-1.4 .4 1.4M183 191.2h.7"/>
<path d="M184.3 191.4v.2M184.6 181h-.5l-.2 .3v.4l.2 .2h.5M185 181h.5M185.2 180.5v1.2l.3 .2M186 181.1h.6l.1 .6-.3 .2h-.2l-.3-.2zM186.3 190.8l-.3-.3 .3-.3h.4v.5a.56 .56 0 0 0-.6 .2 .56 .56 0 0 0 0 .6h.6l.1-.5-.3-.2M187.3 181v.9M187.4 191.4v.2M187.7 181h-.3l-.1 .3M188 190.4l.4-.2a.8 .8 0 0 1 .4 .7 .8 .8 0 0 1-.4 .7l-.4-.3zM188.6 181h-.5l-.1 .2 .6 .3v.4h-.6M189.3 181.8v.1"/>
<path d="M189.4 191.4v.2M189.4 186.8v2.8M190 180.5v1.4M190.1 181.4l.4 .5M190.5 181l-.5 .5M190.8 190.2h-.7v.6l.1-.1 .6 .1v.7l-.6 .1-.1-.2M191.1 180.5v.2M191.1 181v.9M192.4 181l-.6 .1v.7l.2 .1h.4M192.7 187.5h.5l.3 .4v.6l-.3 .4h-.5zM193 181h.5l.1 .9M193.6 181.4h-.5l-.1 .2 .1 .3h.5"/>
<path d="M194.1 188h.4l.2 .2v.7h-.6v-.4l.6-.2M194.9 181h-.5l-.2 .3v.4l.3 .2h.4M194.9 180.5v1.4M195.2 188h.5M195.2 182h1.1M195.4 187.5v1.4h.3M196.1 188.5l.7-.2v-.3h-.5l-.2 .2 .1 .7h.6M197.1 181h-.4l-.1 .2 .2 .2 .3 .1v.4h-.5M197.4 188.8v.1M197.4 188v.2M198.5 181l-.7 .1v.7l.2 .1h.5M199 181.1l.6-.1v.9"/>
<path d="M199 180.5v1.4M199.1 187.6l.7-.1 .1 .4-.9 1h.9M200.6 187.6h.6v.8l-.1 .5h-.4l-.2-.3zM201.7 193v1.8M201.8 187.6l.7-.1 .1 .4-.8 1h.8M203.5 187.4l-.3 1.1h.8M203.8 188v.9M204.6 188.4h1.1M206.2 187.9l.5-.4v1.4M206.2 188.9h.9M207.9 187.5a.73 .73 0 0 1 .6 .6 .73 .73 0 0 1-.3 .8h-.3l-.3-.5zM209 188.4h1.1"/>
<path d="M210.7 187.6l.7-.1 .2 .4-.1 .2-.9 .8h1M212.4 187.4l-.3 1.1h.8M212.8 188v.9M226.3 193.2h-.6v.6l.2-.2 .4 .1v.7l-.6-.1M249 193v1.8M250 186.8v6.2M252.3 190.2v1.4M253.6 190.7h-.5l-.2 .2v.4l.2 .3 .5-.1M253.6 190.2v1.4M254.3 191.4v.2M254.3 190.7v.1M255.9 190.3l.2-.1h.4l.3 .4-.9 1h.9"/>
<path d="M258.4 190.1l-1.3 1.8M258.7 190.2h.9l-.4 .5 .3 .1v.7l-.6 .1-.2-.2M273.6 193.2l-.6 .3v.8l.6 .1v-.7l-.4-.1-.2 .3"/>
<circle cx="175.7" cy="173.3" r=".48"/>
<circle cx="185.4" cy="173.3" r=".48"/>
<circle cx="189.8" cy="178.9" r=".48"/>
</g>
<g fill="none" stroke="#910000" stroke-width=".25">
<path d="M172 175.8l.7-.1 .1-.3-.3-.3h-.5v1.5h.5l.3-.3v-.2l-.3-.3M173.4 175.7l.5-.1 .2 .3v.4l-.2 .3h-.3l-.2-.3zM174.7 175.7l.4-.1 .2 .2v.8M174.7 175.6v1M176 175.7l.4-.1 .2 .2v.8M176 175.6v1M177.2 175.1v.2M177.2 175.6v1M177.9 175.7h.6v.9M177.9 175.6v1M179.9 175.6l-.1 1.3-.3 .2-.3-.1M179.9 175.7h-.7v.7l.2 .2 .5-.1"/>
<path d="M180.5 175.6v1M180.9 175.6l-.4 .1v.2M181.3 176.1l.7-.1-.2-.4-.5 .2v.6l.3 .2 .3-.1M183.7 175.1v1.5h.7M184.9 175.7h.6v.6a.45 .45 0 0 1-.6 .2zM186.1 175.6v.8l.2 .2 .4-.2M186.7 175.6v1M187.4 175.1v.2M187.4 175.6v1M188.6 175.7l-.3-.1-.3 .2 .1 .3h.5v.4h-.6M252.4 188.3h.7l.2-.3-.1-.3-.8-.1v1.3M252.8 188.3l.5 .6"/>
<path d="M253.8 188.5l.7-.2-.2-.3-.4 .1-.1 .7 .1 .1h.5M255 188l.3 .9 .3-.9M256.2 188.8v.1M256.2 188.1v.2M258 187.6a.73 .73 0 0 1 .8 .5 .73 .73 0 0 1-.4 .8h-.4l-.2-.5zM259.3 188.8v.1M259.9 187.9l.4-.3v1.3M259.9 188.9h.7"/>
</g>
<g fill="none" stroke="#910000" stroke-width=".34">
<path d="M172 183.6h1.1M172.6 183.6l-.2 1.9M173.7 184.3l-.1 1.2M173.8 183.6l-.1 .2 .2-.1-.1-.1-.1 .2M174.3 184.3h.8M174.7 183.6l-.2 1.6 .4 .3M175.8 183.6l-.2 1.6 .2 .3M176.5 184.9l1-.2-.1-.3a.6 .6 0 0 0-.9 .2v.8h.8M178.1 185.3v.2M178.3 184.4v.2M180.6 184.7l.9-.1 .3-.3-.1-.5-.3-.2h-.6l-.3 1.9M182.5 184.3l-.1 1.2"/>
<path d="M182.6 183.6v.2M184.2 184.4a.65 .65 0 0 0-.9 .3v.6a.64 .64 0 0 0 .8 .1M184.9 184.7l.4-.4 .5 .1 .1 .3-.1 .5a.56 .56 0 0 1-.9 .1zM186.6 185.5l.3-1.9 .5 1.4 .7-1.4-.2 1.9M188.9 184.5l.3-.2 .5 .2v.8l-.4 .2-.5-.2zM190.4 184.3h.7M190.8 183.6l-.3 1.6 .4 .3M191.7 184.5l.3-.2 .4 .1v1.1M191.9 183.6l-.3 1.9M193.3 184.9l.9-.2-.1-.3a.6 .6 0 0 0-.8 .2v.8h.8M195.1 184.3l-.2 1.2M195.6 184.3l-.4 .1-.1 .3"/>
</g>
<g fill="#ffb">
<path d="M161.6 41.6l7.2 3.6-7.2 3.6z"/>
<path d="M161.6 62l7.2 3.6-7.2 3.7z"/>
<path d="M132.8 41.6l7.2 3.6-7.2 3.6z"/>
<path d="M142.4 78.8h14.4v9.7h-14.4z"/>
<path d="M78.7 55.4h9.6v6.6h-9.6z"/>
<path d="M131.6 60.8l7.2 3.6-7.2 3.6z"/>
<path d="M232.5 120.9h4.8v9.7h-4.8z"/>
<path d="M194.1 120.9h4.8v9.7h-4.8z"/>
<path d="M222.9 47.6h7.2l3.7-3.6h1.1v1.2h2.4l1.2-1.2h12v22.8h-27.6z"/>
<path d="M156.8 120.9h4.8v9.7h-4.8z"/>
<path d="M79.9 120.9h4.8v9.7h-4.8z"/>
<path d="M118.4 120.9h4.8v9.7h-4.8z"/>
</g>
<g fill="none" stroke="#910000" stroke-width=".21">
<path d="M127.9 31.3h2.5v5.6l-1.2 1.1-1.3-1.1zM128.6 34.4a.65 .65 0 0 1 .7-.3 .65 .65 0 0 1 .5 .5 .62 .62 0 0 1-.7 .4 .62 .62 0 0 1-.5-.6zM128.6 32.4h1.2M128.7 33l-.1 .4 .3 .3 .3-.3 .2-.4h.3v.7M129.2 38v1.2M129.8 35.5h-1.2l.9 .3-.9 .4h1.2M156.8 32.1h2.5v4.8l-1.3 1.1-1.2-1.1zM157.5 35.6v.5l.1 .2 .4-.2 .2-.5h.3l.2 .2-.1 .5M157.5 33.9h1.2M157.5 33.2l.7 .7M157.6 34.4l-.1 .6 .2 .1h.6l.3-.1 .1-.4-.2-.2M158 38v1.2"/>
<path d="M158.7 33.2l-.7 .5M67.9 57.2h.1M67.9 54.8l-.8 1.2M67.9 54.8v2.4M67.9 54.8l.7 1.2M76.3 57.2h2.4M88.3 57.2h2.4M98 57.2h.1M98 54.8l-.8 1.2M98 54.8v2.4M98 54.8l.6 1.2M126.7 49.3h2.5v6.8l-1.3 1.1-1.2-1.1z"/>
<path d="M127.4 53.7v.5l.2 .2 .4-.3 .2-.4h.3v.7M127.4 51.6l.1 .6h.3l.5-.6 .3 .2-.1 .4M127.4 50.6a.66 .66 0 0 1 .8-.2 .66 .66 0 0 1 .4 .7h-1.2zM127.5 54.8l-.1 .5a.61 .61 0 0 0 .8 .2 .61 .61 0 0 0 .3-.7M127.9 57.2v1.2M128.7 52.5v.9M129.2 44v1.2h3.6M136.4 51.2v1.2h1.2l-1.2 1.2-1.2-1.2h1.2M136.4 51.2h.1M136.4 48.2v3M140 45.2h3.6M144.6 44h9.7v2.4h-9.7l-1-1.2z"/>
<path d="M145.3 45.8v-1.2l.4 .9 .4-.9v1.2M146.9 44.6l.5 .2v.8l-.2 .2h-.4a.86 .86 0 0 1 .1-1.2zM148.6 44.7h-.6v.4a.47 .47 0 0 1 .5 .2 .47 .47 0 0 1 0 .5h-.6M149.1 44.6v1.2M149.3 46h1M150.4 44.6h.8l-.4 .4 .4 .3-.1 .5-.7-.1M151.6 45l.3 .8 .3-.8M152.6 44.6h.6l-.3 .4 .3 .2v.5h-.6M156.8 47.7h2.5v9.6l-1.3 1.1-1.2-1.1zM157.5 54.1v.6h.5l.2-.5 .2-.1 .3 .3-.1 .4M157.5 53a.77 .77 0 0 1 1.2 .2l-.1 .3a.72 .72 0 0 1-1.1-.2zM157.5 51.6v-.8l.4 .4 .1-.4h.5l.2 .3v.3l-.2 .2"/>
<path d="M157.5 49.4v-.7l.4 .4 .1-.3 .4-.1 .3 .2v.4l-.2 .1M157.5 55.3h1.2M157.8 49.8l.9 .3-.9 .3M158 44v1.2h3.6M158 58.4v1.2M158.7 55.9h-1.2l.8 .4-.8 .3h1.2M158.7 51.7v.9M165.3 51.2v1.2h1.2l-1.2 1.2-1.3-1.2h1.3M165.3 51.2h.1M165.3 48.2v3M168.8 45.2h3.7M173.5 44h9v2.4h-9l-1-1.2z"/>
<path d="M174.8 44.7h-.6l-.1 .3 .2 .2h.3l.2 .4-.1 .2h-.6M176 44.7l-.2-.1a.67 .67 0 0 0-.5 .5 .67 .67 0 0 0 .2 .7l.5-.1M176.5 44.6v1.2M176.7 45.1l.5 .7M177.2 44.6l-.7 .7M177.5 46h.9M178.6 44.6h.6l-.3 .4 .3 .2v.5h-.6M179.7 45l.2 .8 .4-.8M180.6 44.6h.8l-.5 .4 .5 .3v.3l-.2 .2-.6-.1M197.7 50h10.9l1.1 1.2-1.1 1.2h-10.9zM198.9 52.4h9.7l1.1 1.2-1.1 1.2h-9.7zM199.5 50.7a.61 .61 0 0 0-.8 .3 .61 .61 0 0 0 .3 .8l.5-.1"/>
<path d="M199.7 57.2h8.9l1.1 1.2-1.1 1.2h-8.9zM200.1 54.3v-1.3l.4 .9 .3-.9v1.3M200.7 50.7h-.7v.4l.7 .4-.2 .3h-.5M200.8 52h1M201.4 53.2l.5-.2a.86 .86 0 0 1 0 1.3l-.5-.2zM201.5 57.9l-.5-.1-.2 .2v.3l.6 .2 .1 .2-.1 .3h-.6M202.7 50.7h-.6v.4a.47 .47 0 0 1 .5 .2 .47 .47 0 0 1 0 .5h-.6M202.7 58l-.3-.2a.67 .67 0 0 0-.5 .5 .67 .67 0 0 0 .3 .7l.5-.1M203.2 50.6h.3l.4 .3v.7l-.2 .2h-.5zM203.2 57.8v1.2M203.4 53.1l-.5-.1-.3 .3 .2 .3 .5 .2 .1 .2-.3 .3-.5-.1M203.4 58.3l.5 .7"/>
<path d="M203.9 53v1.3M203.9 57.8l-.7 .7M204.1 54.4h1M204.1 52h1M204.1 59.2h1M205.2 53h.8l-.4 .5 .3 .1 .1 .4-.3 .3h-.3l-.2-.2M205.2 50.6h.8l-.4 .5 .4 .2v.3l-.2 .2-.6-.1M205.2 57.8h.8l-.4 .5 .4 .2v.3l-.2 .2-.6-.1M206.3 53.4l.4 .9 .2-.9M206.3 51.1l.4 .7 .2-.7M206.3 58.2l.4 .8 .2-.8M207.3 53h.7l-.4 .5 .3 .1v.6l-.5 .1-.1-.2"/>
<path d="M207.3 50.6h.7l-.4 .5 .4 .2-.1 .5-.6-.1M207.3 57.8h.7l-.4 .5h.3v.7l-.6-.1M71.5 74v1.3h1.1l-1.1 1.2-1.2-1.2h1.2M71.5 74h.1M71.5 62v2.7M71.5 66.5v2.8M83.5 62v2.4M95.5 62v2.7M95.5 66.5v2.8M127.9 63.2v1.2h3.7M135.2 70.4v1.2h1.2l-1.2 1.2-1.3-1.2h1.3M135.2 70.4h.1"/>
<path d="M135.2 67.4v3M138.8 64.4h3.6M143.4 63.2h11v2.4h-11l-1-1.2zM144.8 64l-.4-.2-.3 .4v.6l.2 .2 .5-.1M146 63.9l-.5-.1-.2 .2v.3l.6 .2 .1 .2-.1 .3h-.6M146.2 65.2h.9M148 63.9l-.4-.1-.3 .3 .1 .2 .6 .3v.3l-.7 .1M148.5 63.8h.3l.4 .4v.6l-.2 .2h-.5zM149.4 65.2h1M150.5 63.8h.8l-.4 .5 .4 .2v.4l-.2 .1-.6-.1M151.6 64.3l.4 .7 .2-.7M152.6 63.8h.7l-.4 .5h.3l.1 .2-.1 .5-.6-.1"/>
<path d="M158 64.4v1.2h3.6M165.3 71.6v1.2h1.2l-1.2 1.2-1.3-1.2h1.3M165.3 71.6h.1M165.3 68.7v2.9M168.8 65.6h3.7M173.5 64.4h5.6v2.4h-5.6l-1-1.2zM174.2 66.3v-1.3l.4 1 .4-1v1.3M175.5 65v1.3M176.8 65.1l-.5-.1-.3 .3 .1 .2 .5 .2 .2 .3-.3 .3-.5-.1M177.5 65l.5 .2v.9l-.5 .2a.86 .86 0 0 1 0-1.3zM198.9 62h9.7l1.1 1.2-1.1 1.2h-9.7zM200.1 63.8v-1.1l.4 .8 .3-.8v1.1"/>
<path d="M201.4 62.7v1.1M202.6 62.7h-.4l-.3 .2 .3 .3 .4 .2v.4h-.7M203.4 62.7l.5 .1v.9l-.2 .1h-.4l-.1-.1a.82 .82 0 0 1 .2-1zM204.1 64h1M205.2 62.7h.8l-.4 .4 .4 .2-.1 .5h-.7M206.3 63.1l.4 .7 .2-.7M207.3 62.7h.7l-.4 .4 .4 .2-.1 .5h-.6M137.6 83.6h.1M137.6 83.6h4.8M137.6 81.3l-.8 1.2M137.6 81.3v2.3M137.6 81.3l.7 1.2"/>
<path d="M156.8 83.6h4.8M161.6 83.6v1.2h1.2l-1.2 1.2-1.2-1.2h1.2M161.6 83.6h.1M65.4 119.7l-.6 1.2M65.4 119.7v2.4M65.4 119.7l.8 1.2M104 119.7l-.8 1.2M104 119.7v2.4M104 119.7l.6 1.2M142.4 119.7l-.8 1.2M142.4 119.7v2.4M142.4 119.7l.7 1.2"/>
<path d="M179.7 119.7l-.8 1.2M179.7 119.7v2.4M179.7 119.7l.6 1.2M218.1 119.7l-.7 1.2M218.1 119.7v2.4M218.1 119.7l.8 1.2M65.4 122.1h.1M104 122.1h.1M142.4 122.1h.1M166.3 120.9h4.7v2.4h-4.7l-1-1.2zM167.6 121.7l-.5-.1a.67 .67 0 0 0-.2 .7 .67 .67 0 0 0 .5 .5l.2-.2M168.8 121.6l-.7 .1v.3l.7 .4-.2 .4-.5-.1"/>
<path d="M169.2 121.6h.7l-.4 .4 .3 .1v.6l-.5 .1-.1-.2M179.7 122.1h.1M183.8 125.7h5.6l1.1 1.2-1.1 1.2h-5.6zM184.2 128.1h5.2l1.1 1.2-1.1 1.3h-5.2zM185 127.6v-1.3l.3 1 .5-1v1.3M185.4 128.8v1.2M186.5 126.3a.46 .46 0 0 1 .6 .4v.5a.46 .46 0 0 1-.6 .4 .86 .86 0 0 1 0-1.3zM186.7 128.8v1.2l-.7-1.2v1.2M187.1 128.8h.7M187.4 128.8v1.2M188.2 126.4h-.6v.4l.5 .2 .1 .3-.2 .3-.5-.1M188.4 128.7l-.3 .8h.8"/>
<path d="M188.6 129.1v.9M188.7 126.3v1.3M190.5 122.1h3.6M190.5 124.5h3.6M190.5 126.9h3.6M190.5 129.3h3.6M194.1 129.2h1.1v.3h-1.1zM194.1 126.8h1.1v.2h-1.1zM194.1 124.4h1.1v.2h-1.1zM194.1 122h1.1v.3h-1.1zM197.7 129.2h1.2v.3h-1.2zM197.7 126.8h1.2v.2h-1.2z"/>
<path d="M197.7 124.4h1.2v.2h-1.2zM197.7 122h1.2v.3h-1.2zM198.9 122.1h3.6M198.9 124.5h3.6M198.9 126.9h3.6M198.9 129.3h3.6M203.5 120.9h4.8v2.4h-4.8l-1-1.2zM203.5 123.3h4.9v2.4h-4.9l-1-1.2zM203.5 128.1h5.6v2.5h-5.6l-1-1.3zM203.5 125.7h5.7v2.4h-5.7l-1-1.2zM204.2 130v-1.2l.4 .8 .5-.8v1.2M204.2 127l.6-.1v-.5l-.6-.1v1.3"/>
<path d="M204.5 127l.4 .6M204.8 124l-.4-.1-.3 .3 .3 .3 .4 .2v.3h-.7M204.9 121.7l-.5-.1a.67 .67 0 0 0-.3 .7 .67 .67 0 0 0 .5 .5l.3-.2M205.6 128.8v1.2M206.1 121.6l-.7 .1v.3l.7 .4-.3 .4-.4-.1M206.1 124l-.3-.1a.6 .6 0 0 0-.5 .6 .6 .6 0 0 0 .5 .6l.3-.1M206.1 126.4l-.5-.1-.2 .2v.3l.5 .2 .2 .3-.3 .3-.4-.1M206.4 126.3h.7M206.6 123.9v1.2M206.8 121.5l-.3 .8h.8M206.8 128.8h-.6l-.1 .1 .2 .5 .5 .1v.4h-.7M206.8 124.5l.5 .6"/>
<path d="M206.8 126.3v1.3M207.1 121.9v.9M207.3 123.9l-.7 .7M207.4 128.8h.5l.1 .1v.9l-.5 .2a.86 .86 0 0 1-.1-1.2zM207.7 126.3l-.3 .9h.8M208 126.7v.9M218.1 122.1h.1M220.6 122.1v1.2h1.1l-1.1 1.2-1.3-1.2h1.3M220.6 122.1h.1M222.2 125.7h5.6l1.1 1.2-1.1 1.2h-5.6zM222.8 128.1h5l1.1 1.2-1.1 1.3h-5zM223.4 127.6v-1.3l.5 1 .3-1v1.3"/>
<path d="M223.9 128.8v1.2M224.8 126.5l.2-.2 .5 .2v.7l-.3 .4-.4-.2zM225.1 128.8v1.2l-.7-1.2v1.2M225.5 128.8h.7M225.9 128.8v1.2M226.6 126.4l-.4-.1-.2 .3 .1 .2 .5 .3v.3l-.1 .2-.5-.1M227.2 128.8h-.6v.6l.1-.2 .5 .1v.6h-.6M227.2 126.3v1.3M228.9 122.1h3.6M228.9 124.5h3.6M228.9 126.9h3.6M228.9 129.3h3.6"/>
<path d="M232.5 129.2h1.3v.3h-1.3zM232.5 126.8h1.3v.2h-1.3zM232.5 124.4h1.3v.2h-1.3zM232.5 122h1.3v.3h-1.3zM236.1 129.2h1.2v.3h-1.2zM236.1 126.8h1.2v.2h-1.2zM236.1 124.4h1.2v.2h-1.2zM236.1 122h1.2v.3h-1.2zM237.3 122.1h3.7M237.3 124.5h3.7M237.3 126.9h3.7M237.3 129.3h3.7"/>
<path d="M242 120.9h4.7v2.4h-4.7l-1-1.2zM242 123.3h4.8v2.4h-4.8l-1-1.2zM242 128.1h5.6v2.5h-5.6l-1-1.3zM242 125.7h5.6v2.4h-5.6l-1-1.2zM242.7 130v-1.2l.4 .8 .4-.8v1.2M242.7 127h.5l.1-.2v-.3l-.1-.2h-.5v1.3M243 127l.3 .6M243.3 121.7l-.5-.1-.1 .2v.8l.3 .2 .3-.2M243.3 124h-.6v.4l.6 .4-.2 .3-.4-.1M244.1 128.8v1.2M244.5 121.6h-.6v.5l.5 .2 .1 .2-.2 .3-.5-.1M244.5 124a.55 .55 0 0 0-.8 .5 .55 .55 0 0 0 .8 .5"/>
<path d="M244.5 126.4h-.6v.4l.5 .2 .1 .3-.2 .3-.5-.1M244.9 126.3h.6M245 123.9v1.2M245.2 124.5l.5 .6M245.2 126.3v1.3M245.3 128.8l-.7 .1v.3l.7 .4-.3 .4-.4-.1M245.6 121.6h-.6l-.1 .5h.7v.5l-.2 .2h-.3l-.2-.2M245.7 123.9l-.7 .7M245.9 128.8h.5a.77 .77 0 0 1-.2 1.2l-.3-.1a.87 .87 0 0 1 0-1.1zM246.5 126.3h-.5l-.1 .6 .6-.1v.6l-.1 .2h-.4l-.1-.2"/>
<circle cx="136.4" cy="47.6" r=".64"/>
<circle cx="165.3" cy="47.6" r=".64"/>
<circle cx="135.2" cy="66.8" r=".64"/>
<circle cx="165.3" cy="68" r=".64"/>
</g>
<g fill="none" stroke="#910000" stroke-width=".25">
<path d="M128.2 39.2h2v4.9h-2zM157.1 39.2h1.9v4.9h-1.9zM78.7 55.4h9.6v6.6h-9.6zM127 58.5h2v4.8h-2zM132.8 41.6l7.2 3.7-7.2 3.5zM157.1 59.6h1.9v4.9h-1.9zM161.7 41.6l7.2 3.7-7.2 3.5zM131.6 60.8l7.2 3.7-7.2 3.5zM142.4 78.9h14.4v9.6h-14.4zM161.7 62l7.2 3.7-7.2 3.6zM224.2 65.1h2.3v1.1h-2.3zM194.1 120.9h4.8v9.7h-4.8z"/>
<path d="M232.5 120.9h4.9v9.7h-4.9z"/>
</g>
<g fill="none" stroke="#b90000" stroke-width=".21">
<path d="M77.1 55.6h.7l-.3 .4 .3 .2v.5h-.7M89.2 55.7h.6v.4l-.7 .7h.7M130.6 43.7l.5-.1 .2 .3-.7 .9h.7M136 49.1h-1.2l.3 .3M136 48.8v.6M141.4 43.6h.8l-.5 .4 .5 .3-.1 .4h-.7M160.1 43.6h-.6v.6l.4-.2 .3 .3-.1 .4h-.6M164 48.8h.8M164.4 48.7v.7l-.8-.2M170.9 43.6h-.3a.73 .73 0 0 0-.1 1.2l.4-.1v-.5l-.4-.2-.2 .3M83.1 63.2h-1.2l.3 .2v.2M83.1 62.9v.7"/>
<path d="M130.1 63.3l-.2 .3h-.3l-.1-.2v-.5l.4-.1 .2 .3-.1 .8-.5 .1M133.6 67.6h.1a.66 .66 0 0 1 1.1 .2l-.3 .3h-.7l-.2-.2zM134.8 68.9h-1.2l.3 .4M134.8 68.6v.7M140.5 63.3l-.3-.2 .3-.3 .4 .1v.3a.48 .48 0 0 0-.5 .2 .48 .48 0 0 0 0 .6h.4l.2-.2-.1-.4-.2-.1M158.9 64.3l.4-.3v1.2M158.9 65.2h.7M160 64.2l.2-.2h.3l.2 .2v.3l-.7 .7h.7M163.7 69.3v-.7l.4 .4 .1-.3 .4-.1 .2 .2v.4l-.1 .1M164.8 70.1h-1.1l.3 .3M164.8 69.8v.6M169.8 64.3l.3-.3v1.2"/>
<path d="M169.8 65.2h.6M170.9 64.3l.3-.3v1.2M170.9 65.2h.6M139.1 82.4l.3-.4v1.2M139.1 83.2h.7M140.5 82l-.3 .9h.8M140.8 82.5v.7M158.8 82h.8l-.5 1.2M191.9 125.3h.7l-.4 .5h.3v.7l-.6-.1M191.9 120.8l.4-.3v1.2M191.9 123l.6-.1 .1 .4-.7 .8h.7M191.9 121.7h.7"/>
<path d="M192.2 127.7l-.3 .8h.8M192.5 128.1v.8M200.3 122.9h.8l-.5 1.2M200.6 121.1l-.3-.4 .3-.2h.2l.2 .4-.7 .3v.3l.3 .2 .4-.1v-.4l-.2-.1M200.9 125.3l-.4 .2-.2 .8 .2 .2 .5-.1-.1-.6h-.4l-.2 .2M201 127.8h-.6l-.1 .5h.7v.5l-.2 .1h-.3l-.2-.1M230.3 125.3h.8l-.4 .5 .4 .1v.5h-.8M230.4 120.8l.3-.3v1.2M230.4 123l.6-.1 .1 .5-.8 .7h.8M230.4 121.7h.7M230.7 127.7l-.3 .8h.7M231 128.1v.8"/>
<path d="M238.8 122.9h.7l-.5 1.2M239 121.1l-.2-.4 .2-.2h.3l.2 .3-.7 .4v.3l.2 .2h.3l.2-.2v-.3l-.2-.1M239.3 125.3l-.3 .1-.2 .2v.7l.1 .2h.4l.2-.2v-.3l-.2-.2h-.4l-.1 .2M239.4 127.8h-.6v.5h.6l.1 .4-.2 .2-.5-.1"/>
</g>
<g fill="none" stroke="#006665" stroke-width=".21">
<path d="M79.1 56.6l.4 1.1 .3-1.1M80.3 56.6v1.1M82.8 59.6h1.3l-1.3 .7h1.3M82.9 58.6a.66 .66 0 0 1 .7-.2 .66 .66 0 0 1 .5 .6h-1.3zM85.8 56.6l.5 1.1 .4-1.1M87 56.7l.3-.1 .5 .1v.9l-.2 .1h-.4l-.2-.1zM82.9 60.9l-.1 .1a.6 .6 0 0 0 .6 .5 .6 .6 0 0 0 .6-.6l-.4-.1v.2M143.5 83l.4 1.2 .4-1.2M145.4 83.1l-.3-.1a.67 .67 0 0 0-.5 .5 .67 .67 0 0 0 .3 .7l.5-.1M146.6 83.1l-.2-.1a.66 .66 0 0 0-.6 .4 .66 .66 0 0 0 .2 .8l.6-.1M153.1 83.1l-.1-.1a.66 .66 0 0 0-.6 .4 .66 .66 0 0 0 .3 .8l.5-.1v-.5h-.3M154.3 83v1.2l-.6-1.2v1.2"/>
<path d="M154.9 83a.66 .66 0 0 1 .7 .4 .66 .66 0 0 1-.2 .8h-.5z"/>
</g>
<path d="M69.6 66.4h3.8M69.6 64.9h3.8M93.6 66.4h3.8M93.6 64.9h3.8" fill="none" stroke="#910000" stroke-width=".51"/>
<path d="M224.2 65.1h2.3v1.1h-2.3z" fill="#910000"/>
<path d="M224.2 62.7h2.3v1.2h-2.3z" fill="none" stroke="#910000" stroke-width=".25"/>
<path d="M224.2 62.7h2.3v1.2h-2.3z" fill="#910000"/>
<path d="M224.2 60.2h2.3v1.2h-2.3z" fill="none" stroke="#910000" stroke-width=".25"/>
<path d="M224.2 60.2h2.3v1.2h-2.3z" fill="#910000"/>
<path d="M224.2 57.9h2.3v1.2h-2.3z" fill="none" stroke="#910000" stroke-width=".25"/>
<path d="M224.2 57.9h2.3v1.2h-2.3z" fill="#910000"/>
<path d="M224.2 55.4h2.3v1.3h-2.3z" fill="none" stroke="#910000" stroke-width=".25"/>
<path d="M224.2 55.4h2.3v1.3h-2.3z" fill="#910000"/>
<path d="M224.2 53h2.3v1.2h-2.3z" fill="none" stroke="#910000" stroke-width=".25"/>
<path d="M224.2 53h2.3v1.2h-2.3z" fill="#910000"/>
<path d="M224.2 50.7h2.3v1.2h-2.3z" fill="none" stroke="#910000" stroke-width=".25"/>
<path d="M224.2 50.7h2.3v1.2h-2.3z" fill="#910000"/>
<path d="M224.2 48.2h2.3v1.2h-2.3z" fill="none" stroke="#910000" stroke-width=".25"/>
<path d="M224.2 48.2h2.3v1.2h-2.3z" fill="#910000"/>
<g fill="none" stroke="#910000" stroke-width=".25">
<path d="M223 47.6h7.2l3.6-3.5h1.2v1.2h2.4l1.1-1.2h12.1v22.7h-27.6zM247 44.1v-1.3h-33.7v31.2h33.7v-7.2M80 120.9h4.7v9.7h-4.7zM118.4 120.9h4.8v9.7h-4.8zM156.8 120.9h4.9v9.7h-4.9zM77.5 141.6h4.8v1.9h-4.8zM86 141.3l2.3 1.3-2.3 1.2zM88.3 141.3v2.5M115.9 141.6h4.9v1.9h-4.9zM124.4 141.3l2.4 1.3-2.4 1.2zM126.8 141.3v2.5M154.5 141.6h4.8v1.9h-4.8z"/>
<path d="M162.9 141.3l2.4 1.3-2.4 1.2zM165.3 141.3v2.5M191.7 141.6h4.9v1.9h-4.9zM200.1 141.3l2.5 1.3-2.5 1.2zM202.6 141.3v2.5M230.2 141.6h4.8v1.9h-4.8zM238.5 141.3l2.5 1.3-2.5 1.2zM241 141.3v2.5"/>
</g>
<g fill="none" stroke="#910000" stroke-width=".21">
<path d="M197.7 56h.1M197.7 53.6l-.8 1.2M197.7 53.6v2.4M197.7 53.6l.7 1.2M209.7 48.8h3.6M209.7 51.2h3.6M209.7 53.6h3.6M209.7 56h3.6M209.7 58.4h3.6M197.7 60.8v1.2h1.2l-1.2 1.2-1.2-1.2h1.2M197.7 60.8h.1M209.7 68h3.6"/>
<path d="M209.7 70.4h3.6M209.7 60.8h3.6M209.7 63.2h3.6M209.7 65.6h3.6M247 70.4h3.5M250.5 70.4v1.2h1.3l-1.3 1.2-1.2-1.2h1.2M250.5 70.4h.1M67.9 122.1v1.2h1.2l-1.2 1.2-1.3-1.2h1.3M67.9 122.1h.1M69.6 125.7h5.7l1 1.2-1 1.2h-5.7zM70.1 128.1h5.2l1 1.2-1 1.3h-5.2zM70.8 127.6v-1.3l.4 1 .3-1v1.3"/>
<path d="M71.2 128.8v1.2M72.1 126.5l.5-.2a.86 .86 0 0 1 0 1.3l-.3-.1a.74 .74 0 0 1-.2-1zM72.5 128.8v1.2l-.7-1.2v1.2M72.9 128.8h.7M73.2 128.8v1.2M73.9 129.1l.3-.3v1.2M73.9 130h.7M74 126.4l-.4-.1-.3 .3 .1 .2 .6 .3v.3l-.2 .2-.5-.1M74.6 126.3v1.3M76.3 122.1h3.6M76.3 124.5h3.6M76.3 126.9h3.6"/>
<path d="M76.3 129.3h3.6M79.9 129.2h1.2v.3h-1.2zM79.9 126.8h1.2v.2h-1.2zM79.9 124.4h1.2v.2h-1.2zM79.9 122h1.2v.3h-1.2zM83.5 129.2h1.2v.3h-1.2zM83.5 126.8h1.2v.2h-1.2zM83.5 124.4h1.2v.2h-1.2zM83.5 122h1.2v.3h-1.2zM84.7 122.1h3.6M84.7 124.5h3.6M84.7 126.9h3.6"/>
<path d="M84.7 129.3h3.6M89.3 128.1h5.7v2.5h-5.7l-1-1.3zM89.3 120.9h4.8v2.4h-4.8l-1-1.2zM89.3 125.7h5.7v2.4h-5.7l-1-1.2zM89.3 123.3h4.8v2.4h-4.8l-1-1.2zM90 130v-1.2l.4 .8 .4-.8v1.2M90 127h.5l.3-.4-.3-.3h-.5v1.3M90.3 127l.5 .6M90.7 124h-.7v.4l.7 .4-.3 .3-.4-.1M90.8 121.7l-.6-.1-.2 .2 .1 .8 .3 .2 .4-.2M91.4 128.8v1.2M91.9 121.6h-.6v.5l.5 .2 .1 .2-.3 .3-.4-.1"/>
<path d="M91.9 126.4h-.6v.4l.5 .2 .1 .3-.3 .3-.4-.1M91.9 124a.55 .55 0 0 0-.8 .5 .55 .55 0 0 0 .8 .5M92.2 126.3h.7M92.4 121.9l.3-.3v1.2M92.4 122.8h.6M92.4 123.9v1.2M92.5 126.3v1.3M92.5 124.5l.5 .6M92.6 128.8l-.7 .1v.3l.7 .4-.2 .4-.5-.1M93 123.9l-.6 .7M93.2 128.8h.5a.77 .77 0 0 1-.1 1.2l-.4-.1a.87 .87 0 0 1 0-1.1zM93.2 126.7h.2l.2-.4v1.3"/>
<path d="M93.2 127.6h.7M106.3 122.1v1.2h1.2l-1.2 1.2-1.1-1.2h1.1M106.3 122.1h.1M108.1 125.7h5.6l1 1.2-1 1.2h-5.6zM108.5 128.1h5.2l1 1.2-1 1.3h-5.2zM109.2 127.6v-1.3l.4 1 .5-1v1.3M109.7 128.8v1.2M110.6 126.5l.2-.2 .5 .2v.9l-.2 .2-.5-.2zM110.9 128.8v1.2l-.7-1.2v1.2M111.3 128.8h.7M111.7 128.8v1.2M112.3 128.9l.6-.1 .2 .1-.1 .4-.7 .7h.8"/>
<path d="M112.5 126.4l-.5-.1-.2 .2v.3l.5 .2 .2 .3-.2 .3-.5-.1M113 126.3v1.3M114.7 122.1h3.7M114.7 124.5h3.7M114.7 126.9h3.7M114.7 129.3h3.7M118.4 129.2h1.1v.3h-1.1zM118.4 126.8h1.1v.2h-1.1zM118.4 124.4h1.1v.2h-1.1zM118.4 122h1.1v.3h-1.1zM121.9 129.2h1.3v.3h-1.3zM121.9 126.8h1.3v.2h-1.3z"/>
<path d="M121.9 124.4h1.3v.2h-1.3zM121.9 122h1.3v.3h-1.3zM123.2 122.1h3.5M123.2 124.5h3.5M123.2 126.9h3.5M123.2 129.3h3.5M127.8 120.9h4.8v2.4h-4.8l-1.1-1.2zM127.8 125.7h5.7v2.4h-5.7l-1.1-1.2zM127.8 123.3h4.8v2.4h-4.8l-1.1-1.2zM127.8 128.1h5.6v2.5h-5.6l-1.1-1.3zM128.5 127h.4l.3-.3-.3-.4h-.4v1.3M128.5 130v-1.2l.4 .8 .4-.8v1.2"/>
<path d="M128.8 127l.4 .6M129.1 124h-.6v.5l.5 .1 .1 .3-.2 .2-.5-.1M129.2 121.7l-.5-.1a.67 .67 0 0 0-.3 .7 .67 .67 0 0 0 .5 .5l.3-.2M129.9 128.8v1.2M130.3 121.6h-.5l-.2 .1 .2 .4 .5 .2v.3l-.2 .2-.5-.1M130.3 126.4l-.4-.1-.3 .3 .1 .2 .6 .3v.3l-.2 .2-.5-.1M130.3 124a.45 .45 0 0 0-.7 .2v.7a.45 .45 0 0 0 .7 .1M130.6 126.3h.8M130.8 121.7l.6-.1 .1 .3-.8 .9h.8M130.8 123.9v1.2M131 126.3v1.3M131 124.5l.6 .6"/>
<path d="M131.1 128.8h-.6a.47 .47 0 0 0 0 .5 .47 .47 0 0 0 .5 .2v.4h-.6M131.6 128.9l.1-.1h.5a.86 .86 0 0 1-.1 1.2l-.5-.2zM131.6 123.9l-.8 .7M131.7 126.5l.5-.2 .2 .4-.7 .9h.7M144.8 122.1v1.2h1.2l-1.2 1.2-1.2-1.2h1.2M144.8 122.1h.1M146.6 125.7h5.5l1.1 1.2-1.1 1.2h-5.5zM147 128.1h5.1l1.1 1.2-1.1 1.3h-5.1zM147.7 127.6v-1.3l.4 1 .4-1v1.3M148.2 128.8v1.2M149.3 126.3l.5 .2v.9l-.5 .2a.86 .86 0 0 1 0-1.3zM149.4 128.8v1.2l-.6-1.2v1.2"/>
<path d="M149.8 128.8h.7M150.2 128.8v1.2M150.8 128.8h.8l-.5 .4 .5 .3-.1 .4h-.7M151 126.4h-.6v.4l.5 .2 .1 .3-.3 .3-.4-.1M151.5 126.3v1.3M153.2 122.1h3.6M153.2 124.5h3.6M153.2 126.9h3.6M153.2 129.3h3.6M156.8 129.2h1.2v.3h-1.2zM156.8 126.8h1.2v.2h-1.2zM156.8 124.4h1.2v.2h-1.2z"/>
<path d="M156.8 122h1.2v.3h-1.2zM160.4 129.2h1.2v.3h-1.2zM160.4 126.8h1.2v.2h-1.2zM160.4 124.4h1.2v.2h-1.2zM160.4 122h1.2v.3h-1.2zM161.6 122.1h3.7M161.6 124.5h3.7M161.6 126.9h3.7M161.6 129.3h3.7M166.3 125.7h5.7v2.4h-5.7l-1-1.2zM166.3 128.1h5.6v2.5h-5.6l-1-1.3zM166.3 123.3h4.8v2.4h-4.8l-1-1.2z"/>
<path d="M167 127l.6-.1v-.5l-.6-.1v1.3M167 130v-1.2l.4 .8 .3-.8v1.2M167.2 127l.4 .6M167.6 124l-.5-.1-.2 .3 .2 .3 .5 .2v.3h-.7M168.3 128.8v1.2M168.8 126.4l-.5-.1-.2 .2v.3l.6 .2 .1 .3-.2 .3-.5-.1M168.8 124l-.2-.1a.6 .6 0 0 0-.5 .6 .6 .6 0 0 0 .5 .6l.2-.1M169.2 126.3h.6M169.3 123.9v1.2M169.5 128.8h-.5l-.2 .1 .3 .5 .4 .1v.4h-.7M169.5 126.3v1.3M169.5 124.5l.5 .6"/>
<path d="M170 128.9l.2-.1h.4l.2 .1v.9l-.3 .2-.5-.2zM170 123.9l-.7 .7M170.1 126.3h.8l-.5 .5h.4v.7l-.5 .1-.2-.2M182 122.1v1.2h1.2l-1.2 1.2-1.2-1.2h1.2M182 122.1h.1M70.4 141.3h4.9l1 1.3-1 1.2h-4.9zM72.3 142.1a.55 .55 0 0 0-.8 .5 .55 .55 0 0 0 .8 .5M73.5 142.1h-.7v.3l.7 .4-.3 .4-.4-.1M73.9 142.3l.3-.3v1.2M73.9 143.2h.7M76.3 142.6h1.2M82.3 142.6h8.4"/>
<path d="M90.3 141.1v-.7h-.8h.8l-1.5 1.4M90.7 142.6v1.2h1.2l-1.2 1.1-1.2-1.1h1.2M90.7 142.6h.1M91.4 141.1v-.7h-.7h.7l-1.4 1.4M109 141.3h4.7l1 1.3-1 1.2h-4.7zM110.7 142.1a.45 .45 0 0 0-.6 .1v.7a.45 .45 0 0 0 .6 .2M111.9 142.1l-.4-.1-.3 .2 .1 .3 .5 .2v.4h-.6M112.3 142.1l.6-.1 .2 .2-.8 1h.8M114.7 142.6h1.2M120.7 142.6h8.5M128.7 141.1v-.7h-.8h.8l-1.4 1.4M129.2 142.6v1.2h1.2l-1.2 1.1-1.3-1.1h1.3"/>
<path d="M129.2 142.6h.1M129.9 141.1v-.7h-.7h.7l-1.5 1.4M147.4 141.3h4.7l1.1 1.3-1.1 1.2h-4.7zM149.3 142.1l-.3-.1a.6 .6 0 0 0-.5 .6 .6 .6 0 0 0 .5 .6l.3-.1M150.4 142.1l-.5-.1-.2 .2 .1 .3 .6 .2v.4h-.7M150.8 142h.8l-.5 .4 .5 .3-.1 .4h-.7M153.2 142.6h1.2M159.3 142.6h8.3M167.1 141.1v-.7h-.6h.6l-1.4 1.4M167.6 142.6v1.2h1.2l-1.2 1.1-1.1-1.1h1.1M167.6 142.6h.1M168.3 141.1v-.7h-.7h.7l-1.4 1.4"/>
<path d="M184.7 141.3h4.7l1.1 1.3-1.1 1.2h-4.7zM186.5 142.1l-.2-.1a.6 .6 0 0 0-.6 .6 .6 .6 0 0 0 .6 .6l.2-.1M187.6 142.1l-.4-.1-.3 .2 .3 .4 .4 .1v.4h-.7M188.4 141.9l-.3 .8h.8M188.6 142.4v.8M190.5 142.6h1.2M196.5 142.6h8.4M204.4 141.1v-.7h-.7h.7l-1.5 1.4M204.9 142.6v1.2h1.2l-1.2 1.1-1.2-1.1h1.2M204.9 142.6h.1M205.6 141.1v-.7h-.7h.7l-1.5 1.4M223.1 141.3h4.7l1.1 1.3-1.1 1.2h-4.7z"/>
<path d="M225 142.1a.55 .55 0 0 0-.8 .5 .55 .55 0 0 0 .8 .5M226.1 142.1h-.6l-.1 .2 .2 .3h.3l.2 .3-.2 .3-.5-.1M227.2 142h-.6v.6l.1-.2 .5 .1v.6h-.6M228.9 142.6h1.2M234.9 142.6h8.4M242.9 141.1v-.7h-.8h.8l-1.4 1.4M243.3 142.6v1.2h1.2l-1.2 1.1-1.2-1.1h1.2M243.3 142.6h.1M244.1 141.1v-.7h-.8h.8l-1.4 1.4"/>
</g>
<g fill="none" stroke="#006665" stroke-width=".21">
<path d="M213.9 55.4l.4 1.2 .4-1.2M214.1 48.2h.4a.66 .66 0 0 1 .3 .7 .66 .66 0 0 1-.7 .5zM214.1 50.5a.66 .66 0 0 1 .7 .5 .66 .66 0 0 1-.3 .7h-.4zM214.8 53.1l-.3-.2a.65 .65 0 0 0-.5 .6 .65 .65 0 0 0 .5 .7l.3-.2M214.8 57.9l-.3-.2a.67 .67 0 0 0-.5 .6 .67 .67 0 0 0 .3 .6l.5-.1M215.1 49.4l.5-1.2 .3 1.2M215.1 51.7l.5-1.2 .3 1.2M215.1 55.4h.5a.66 .66 0 0 1 .2 .7 .66 .66 0 0 1-.7 .5zM215.2 49h.6M215.2 51.4h.6M215.3 54.2v-1.3l.4 .9 .4-.9v1.3M215.3 57.7v1.2h.6"/>
<path d="M216.2 48.2h.6M216.2 50.5h.6M216.2 57.7v1.2M216.3 55.4h.4a.66 .66 0 0 1 .3 .7 .66 .66 0 0 1-.7 .5zM216.4 58.2l.5 .7M216.5 48.2v1.2M216.5 50.5v1.2M216.7 52.9l.6 .2v.2v.5l-.4 .4h-.2zM216.9 57.7l-.7 .7M217.1 50.5h.7l-.3 .5 .3 .1v.5h-.7M217.2 48.3l.6-.1v.5l-.7 .7h.7M219.3 50.5l-1.1 1.6"/>
<path d="M220.3 50.6a.45 .45 0 0 0-.7 .2v.7l.2 .2 .5-.1M220.8 50.5a.66 .66 0 0 1 .7 .4 .66 .66 0 0 1-.2 .8h-.5zM213.9 60.2l.4 1.2 .4-1.2M214.1 67.4h.4a.66 .66 0 0 1 .3 .7 .66 .66 0 0 1-.7 .5zM214.1 62.6a.6 .6 0 0 1 .7 .6 .6 .6 0 0 1-.7 .6zM214.1 64.9a.64 .64 0 0 1 .7 .7 .64 .64 0 0 1-.7 .6zM214.1 69.8a.66 .66 0 0 1 .7 .4 .66 .66 0 0 1-.3 .7h-.4zM215.1 63.8l.5-1.2 .3 1.2M215.1 66.2l.5-1.3 .3 1.3M215.2 63.4h.6M215.2 65.9h.6M215.3 68h.4"/>
<path d="M215.3 70.4h.4M215.7 60.2h-.5l-.2 .2 .2 .3 .5 .2v.3l-.1 .2-.6-.1M215.9 67.4h-.6v1.2h.6M215.9 69.8h-.6v1.1h.6M216.2 62.6h.6M216.2 64.9h.6M216.2 67.4h.7M216.2 69.8h.7M216.5 62.6v1.2M216.5 64.9v1.3M216.6 67.4v1.2M216.6 69.8v1.1"/>
<path d="M216.9 60.2l-.7 .1v.3l.7 .4-.2 .4-.5-.1M217 68.7h.9M217 71.1h.9M217.2 65.3h.1l.2-.4v1.3M217.2 66.2h.6M217.3 62.7l.3-.1 .2 .2v.7l-.3 .3a.7 .7 0 0 1-.2-1.1zM218 68.6l.4-1.2 .5 1.2M218.2 70.4l.6-.1 .1-.3-.3-.2h-.4v1.1h.6l.1-.5h-.3M218.2 68.2h.5M241.1 69.8h-.6v.5l.5 .1 .1 .4-.1 .1h-.6M241.6 69.8v1.1M241.6 70.4h.7"/>
<path d="M242.3 69.8v1.1M242.9 69.8v1.1M243.5 70.4h.3M244 69.8h-.5v1.1h.5M244.6 69.8v1.1h.5M245.5 69.8a.66 .66 0 0 1 .7 .4 .66 .66 0 0 1-.2 .7h-.5z"/>
</g>
<g fill="none" stroke="#b90000" stroke-width=".21">
<path d="M211.1 52h.7l-.4 .5h.3v.7l-.6-.1M211.2 47.6l.3-.4v1.2M211.2 49.7l.4-.1 .2 .4-.7 .8h.7M211.2 48.4h.6M211.4 54.4l-.2 .8h.7M211.7 56.8h-.5v.6l.1-.2 .4 .1v.7l-.5-.1M211.7 59.2a.72 .72 0 0 0-.5 .5 .72 .72 0 0 0 .2 .7h.3l.1-.5a.35 .35 0 0 0-.3-.2 .35 .35 0 0 0-.3 .2M211.7 54.8v.8M210.6 66.8l.3-.3v1.1M210.6 67.6h.6M211.1 61.6h.8l-.5 1.2M211.4 64.5h-.2a.31 .31 0 0 1 .1-.4 .31 .31 0 0 1 .4 .1v.3h-.3l-.2 .3v.4h.5l.1-.4-.2-.3"/>
<path d="M211.7 66.6l.2-.1a.6 .6 0 0 1 .6 .4 .6 .6 0 0 1-.2 .7h-.3l-.3-.2zM211.8 69.3l-.4 .3-.2-.3v-.2a.35 .35 0 0 1 .3-.3 .35 .35 0 0 1 .3 .3l-.1 .8-.5 .1M247.8 69.2l.4-.4v1.2M247.8 70h.7M249 69.2l.3-.4v1.2M249 70h.7M77.7 120.8h.2l.2-.3v1.2M77.7 123h.7v.4l-.7 .7h.7M77.7 125.3h.7l-.3 .5 .3 .1v.5h-.7M77.7 121.7h.7M78.1 127.7l-.4 .8h.8M78.3 128.1v.8"/>
<path d="M86.1 122.9h.8l-.5 1.2M86.4 121.1l-.2-.5 .4-.1 .3 .3-.3 .3-.4 .1v.4l.2 .1h.2l.3-.2v-.3l-.3-.1M86.7 125.3l-.3 .1-.2 .2v.8l.5 .1 .2-.2v-.3l-.2-.2h-.4l-.1 .2M86.8 127.8h-.6v.5h.6l.1 .4-.3 .2-.4-.1M116.2 125.3h.7l-.4 .5 .4 .2v.3l-.1 .2-.6-.1M116.2 120.8l.4-.3v1.2M116.2 123l.6-.1 .1 .4-.7 .8h.7M116.2 121.7h.7M116.5 127.7l-.3 .8h.7M116.8 128.1v.8M124.5 122.9h.9l-.5 1.2M124.9 121.1l-.2-.1a.31 .31 0 0 1 .1-.4 .31 .31 0 0 1 .4 0v.4l-.5 .1-.1 .1 .1 .5h.2l.4-.2-.1-.4h-.2"/>
<path d="M125.2 127.8h-.5l-.1 .5h.6v.6h-.4l-.2-.1M125.2 125.3h-.2a.93 .93 0 0 0-.3 1.2h.5l.1-.5-.1-.2h-.5l-.1 .2M154.6 125.3h.8l-.5 .5h.4l.1 .2-.1 .5-.7-.1M154.7 120.8l.3-.3v1.2M154.7 123l.6-.1 .1 .4-.8 .8h.8M154.7 121.7h.7M154.9 127.7l-.2 .8h.7M155.3 128.1v.8M163 122.9h.8l-.5 1.2M163.3 121.1l-.2-.4 .2-.2h.3l.1 .4-.6 .3v.3l.2 .2 .4-.1v-.4l-.1-.1M163.7 125.3l-.5 .2-.1 .8 .1 .2 .5-.1v-.6h-.5l-.1 .2M163.7 127.8h-.6v.5h.6v.5l-.1 .1h-.4l-.1-.1"/>
</g>
<g fill="none" stroke="#090" stroke-width=".21">
<path d="M67.9 57.2h8.4M71.5 57.2v4.8M90.7 57.2h7.3M95.5 57.2v4.8M197.7 56h12M71.5 69.3v4.7M83.5 64.4v7.2M95.5 69.3v2.3h-24M197.7 60.8h12M65.4 122.1v2.4h10.9M67.9 122.1h8.4M104 122.1v2.4h10.7"/>
<path d="M106.3 122.1h8.4M142.4 122.1v2.4h10.8M144.8 122.1h8.4M179.7 122.1v2.4h10.8M182 122.1h8.5M218.1 122.1v2.4h10.8M220.6 122.1h8.3"/>
</g>
<g fill="none" stroke="#0000ca" stroke-width=".21">
<path d="M117.2 30.7h67.3v62.6h-67.3zM189.2 30.7h66.2v55.3h-66.2zM60.6 44h50.6v42h-50.6zM79.8 88.9h.5l.1-.5-.6-.1v1.2M80.1 88.9l.3 .6M80.9 89.1l.5-.1v-.3h-.5v.7h.5M81.3 88.2l-.2 .2M82.5 89.4a.36 .36 0 0 1-.5-.2v-.5h.5v1l-.2 .2-.3-.1M83.1 88.7v.6l.1 .2 .4-.1M83.6 88.7v.8M84.2 88.3v1l.1 .2M84.8 88.7h.5v.8"/>
<path d="M85.3 89l-.5 .1-.1 .1 .2 .3 .4-.1M85.8 88.7h.4M85.9 88.3v1.1l.3 .1M86.5 89.1l.6-.1-.1-.3h-.4l-.1 .2v.4l.2 .2 .3-.1M87.6 88.7v.7h.5M88.1 88.7v.8M88.7 88.7v.8M89.1 88.7h-.3l-.1 .2M90.3 88.3h.7l-.4 .4 .4 .3-.1 .4h-.6M91.4 88.7l.3 .8 .2-.8M92.3 88.3h.7l-.4 .4 .4 .1v.6h-.7M136.2 95.2l-.5-.1a.66 .66 0 0 0-.2 .7 .66 .66 0 0 0 .6 .5l.1-.2"/>
<path d="M136.7 95.6l.2-.2 .3 .1v.7l-.3 .1-.2-.2zM137.8 95.6l.2-.2 .3 .1v.8M137.8 95.4v.9M138.9 95.4l.2 .9 .3-.9M139.8 95.8h.6l-.2-.4-.4 .2v.5l.2 .2 .3-.1M140.9 95.4v.9M141.2 95.4l-.3 .3M142.1 95.5l-.4-.1-.1 .2 .1 .2 .4 .1v.3h-.5M142.6 95.1v.1M142.6 95.4v.9M143.1 95.7l.4-.3 .3 .3v.3l-.5 .3-.2-.3zM144.3 95.6l.1-.2 .4 .2v.7"/>
<path d="M144.3 95.4v.9M146.3 95.6l.2-.2 .3 .2v.7M146.3 95.4v.9M147.3 95.1v.1M147.3 95.4v.9M147.8 95.4l.3 .9 .3-.9M148.8 95.8h.5l-.1-.4-.4 .2v.5l.1 .2 .4-.1M149.9 95.5h.5v.8M150.4 95.8h-.5l-.1 .1 .1 .4 .5-.1M151 95.4v.7l.1 .2 .4-.2M151.5 95.4v.9M151.9 95.4l.7 .9"/>
<path d="M152.6 95.4l-.7 .9M153.9 95.1v1l.2 .2M154.6 95.5l.3-.1 .2 .2v.5l-.2 .2-.4-.3zM156.1 95.4v1.1l-.5 .1M156.1 95.5l-.3-.1-.2 .2v.5l.2 .2 .3-.1M156.7 95.1v.1M156.7 95.4v.9M157.8 95.5l-.3-.1-.3 .3v.3l.3 .3 .3-.1M157.8 95.4v1.2M158.4 95.4v.7l.2 .2 .3-.2M158.9 95.4v.9M159.4 95.8h.6l-.2-.4-.4 .2v.5l.2 .2 .3-.1"/>
<path d="M160.9 95.5l-.3-.1-.2 .2 .2 .2 .3 .1v.3h-.5M163.1 95.1h-.6l-.2 .1 .2 .4 .6 .3-.3 .4-.5-.1M163.6 95.1h.4a.66 .66 0 0 1 .2 .7 .66 .66 0 0 1-.6 .5zM217 88.9l-.5-.1a.61 .61 0 0 0-.2 .8 .61 .61 0 0 0 .7 .3M217.5 89.3l.2-.1h.3v.7h-.5zM218.6 89.3l.2-.1h.3v.8M218.6 89.2v.8M219.7 89.3l.2-.1 .3 .1v.7M219.7 89.2v.8M220.7 89.6l.6-.1-.2-.3-.4 .1v.5l.2 .2 .3-.1M222.3 89.2h-.3l-.3 .2 .1 .5h.5M222.7 89.2h.5"/>
<path d="M222.8 88.8v1l.4 .2M223.5 89.6l.5-.1v-.3h-.5v.7h.5M224.5 89.2v.6l.2 .2 .3-.1M225 89.2v.8M225.6 89.2v.8M226 89.2l-.4 .2M227.9 88.8h-.5l-.2 .2 .2 .3 .5 .2v.4h-.7M228.4 88.8h.5l.2 .3v.6l-.3 .3h-.4zM53.4 111.3h206.8v44.5h-206.8zM139.6 108.4l-.5-.1a.67 .67 0 0 0-.3 .7 .67 .67 0 0 0 .6 .5l.2-.1M140 108.9l.5-.3 .2 .3-.1 .5h-.5zM141.2 108.8l.2-.2 .3 .2v.7"/>
<path d="M141.2 108.6v.9M142.3 108.8l.2-.2 .3 .2v.7M142.3 108.6v.9M143.3 109h.6l-.1-.4-.5 .2v.5l.2 .2 .3-.1M144.9 108.7h-.5v.5a.36 .36 0 0 0 .5 .2M145.3 108.6h.4M145.5 108.3v1l.2 .2M146 109h.6l-.1-.4-.5 .2v.5l.2 .2 .4-.1M147.1 108.6v.7l.2 .2 .4-.1M147.7 108.6v.9M148.2 108.6v.9M148.6 108.6l-.4 .3"/>
<path d="M149.4 108.7l-.3-.1-.2 .2 .2 .2 .3 .1v.3h-.5M151.4 108.7l-.4-.1-.2 .3 .1 .5h.5M151.9 108.7h.5v.8M152.4 109h-.5v.4h.5M153 108.6v.9M153.3 108.6l-.3 .3M153.6 108.6h.4M153.8 108.3v1l.2 .2M154.3 109h.6l-.1-.4-.5 .2v.5l.2 .2 .4-.1M155.9 108.7h-.5v.3h.4l.2 .3-.2 .2-.4-.1M157.2 108.6h.4M157.6 108.3h-.2v1.2"/>
<path d="M158.1 108.3v.1M158.1 108.6v.9M158.6 108.3v1l.1 .2M159.3 108.3v1l.1 .2M159.8 109h.6v-.3h-.6v.7h.6M161.3 108.7h-.4v.3h.3l.2 .3-.2 .2-.3-.1"/>
</g>
<path d="M209.1 48.3l1.2 1.1M210.3 48.3l-1.2 1.1M209.1 67.5l1.2 1.1M209.1 65l1.2 1.2M209.1 69.8l1.2 1.2M210.3 67.5l-1.2 1.1M210.3 65l-1.2 1.2M210.3 69.8l-1.2 1.2" fill="none" stroke="#00008a" stroke-width=".21"/>
<g fill="#090">
<circle cx="95.5" cy="57.3" r=".47"/>
<circle cx="83.5" cy="71.7" r=".47"/>
<circle cx="71.5" cy="71.7" r=".47"/>
<circle cx="71.5" cy="57.3" r=".47"/>
</g>
<g fill="none" stroke="#006665" stroke-width=".21">
<path d="M229.5 39.7v.2M231.6 37.3v.9l-.2 .2-.3 .1M232.6 37.3l-.5 .3v.8h.6v-.4l-.2-.2h-.3l-.1 .2M234.5 39.8l-.4-.1-.3 .3 .1 .2 .5 .2v.5h-.6M235 39.7h.4l.3 .3v.6l-.2 .3h-.5zM66.7 53.2h.9M67.1 52.7v.9M68.7 52.4h-.5v.6l.4-.2 .2 .3-.1 .4h-.5M69.2 52.4l.3 1.2 .4-1.2M78.1 52.9v1.2h.6M79.1 54.1v-1.2l.4 .9 .4-.9v1.2M80.4 53.3l.4-.4v1.2"/>
<path d="M80.4 54.1h.7M81.6 53.3l.4-.4v1.2M81.6 54.1h.7M82.5 50.7v1l.2 .2h.4l.2-.2v-1M82.7 53.3l.4-.4v1.2M82.7 54.1h.7M83.8 52.9h.8l-.5 1.2M83.8 50.9l.4-.2 .3 .4-.8 .8h.8M85.1 53.7h.9M86.4 52.9h.8l-.4 .5 .4 .2v.3l-.2 .2-.6-.1M87.7 54v.1M88.1 52.9h.8l-.4 .5h.3l.1 .2-.1 .5-.7-.1"/>
<path d="M96.2 53.2h.9M96.6 52.7v.9M97.5 52.4h.8l-.4 .4 .4 .3-.1 .4h-.7M98.6 52.4l.5 1.2 .3-1.2M99.7 52.4h.8l-.4 .4 .4 .3-.1 .4h-.7M124.9 59.9h1.3M125.3 59.5l.4 .4M126.2 43.7v-.7l.4 .3 .1-.3h.5l.1 .2v.3l-.1 .2M126.2 42v-.8l.4 .5 .1-.4 .4-.1 .2 .3v.3l-.1 .2M126.2 40.7h1.1M126.2 59.5l-.6 .4M126.5 40.3l.5 .4"/>
<path d="M127.2 42.4h.1M127.3 40.3l-.5 .3M130.7 41.6l.7-.1 .1-.4-.3-.2h-.5v1.3M131.1 41.6l.4 .6M131.9 41.3l.3-.4v1.3M131.9 42.2h.7M133.6 40.9l-.3 .1-.2 .2v.8l.4 .2 .3-.3v-.2l-.3-.3-.4 .1v.2M133.8 44.5l.1 1.2h.4l.1-.2v-1M135 44.9l.3-.4v1.2M135 45.7h.6M135.5 55.4h-.5a.61 .61 0 0 0-.2 .8 .61 .61 0 0 0 .7 .3v-.5h-.2M136 45.7l.4-1.2 .4 1.2"/>
<path d="M136.1 45.4h.5M136.7 55.4v1.2l-.6-1.2v1.2M137.3 55.4h.4a.66 .66 0 0 1 .3 .7 .66 .66 0 0 1-.7 .5zM154.9 43.7v-.7l.5 .3 .1-.3h.5v.7M154.9 42v-.8l.5 .5 .2-.5h.4l.1 .2-.1 .6M154.9 40.7h1.2M155.4 40.3l.4 .4M156 42.4h.1M156.1 40.3l-.4 .3M159.6 41.6l.7-.1v-.4l-.2-.2h-.5v1.3M159.9 41.6l.4 .6M160.8 41.3l.3-.4v1.3"/>
<path d="M160.8 42.2h.7M161.9 40.9h.7l-.5 1.3M162.5 44.5v1l.1 .2h.5l.1-.2v-1M163.7 44.9l.4-.4v1.2M163.7 45.7h.7M164.3 55.4h-.5l-.1 .2v.7a.45 .45 0 0 0 .6 .2v-.5h-.1M164.9 45.1h.5l.1-.1v-.4l-.6-.1v1.2h.6l.1-.3-.1-.3h-.1M165.6 55.4v1.2l-.8-1.2v1.2M166.1 55.4h.5l.2 .2v.7l-.3 .3h-.4zM191.9 56.1h1M192.4 55.6v1M193.3 55.4h.8l-.5 .4 .5 .2v.5h-.8"/>
<path d="M194.4 55.4l.4 1.2 .4-1.2M195.5 55.4h.8l-.5 .4 .4 .1v.6h-.7M228.2 40.9v-1.2l.4 .9 .4-.9v1.2M229.5 40.1v.8M230.6 40.2l-.3-.1-.3 .3v.3l.2 .2h.4M231.1 40.1v.8M231.5 40.1l-.4 .3M231.9 40.2h.5l.1 .5-.2 .2h-.3l-.2-.2zM232.7 41.1h.9M70.7 77.6a.45 .45 0 0 0-.7 .2v.7a.52 .52 0 0 0 .8 .2v-.5h-.3M72 77.6v1.1l-.7-1.1v1.1M72.5 77.6a.61 .61 0 0 1 .7 .5 .61 .61 0 0 1-.7 .6z"/>
<path d="M74.6 66.4l.3-.4v1.2M74.6 67.2h.7M75.4 64l-.3-.2a.6 .6 0 0 0-.5 .7 .6 .6 0 0 0 .7 .5l.1-.1M75.8 64l.4-.2 .3 .4-.8 .9h.8M75.9 66.1l.2-.1 .3 .3v.8l-.2 .1h-.3l-.2-.4zM77 66.1l.3-.1a.91 .91 0 0 1 .1 1.2l-.4-.1zM78.1 66.5h.3l.2 .1v.6M78.1 66.5v.7M79.2 66.6h.4M79.8 66h-.6v1.2M98.6 66.4l.4-.4v1.2M98.6 67.2h.7"/>
<path d="M99.4 64l-.3-.2-.4 .2v.9a.37 .37 0 0 0 .3 .2 .37 .37 0 0 0 .4-.2M99.7 63.8h.8l-.4 .5h.3v.7l-.5 .1-.2-.2M99.9 66.1l.3-.1 .2 .3v.8l-.2 .1h-.3l-.2-.4zM101 66.1l.3-.1a.91 .91 0 0 1 .1 1.2h-.3l-.2-.1zM102.1 66.5h.3l.2 .1v.6M102.1 66.5v.7M103.2 66.6h.4M103.8 66h-.6v1.2M124.9 62.9v-.7l.5 .4 .1-.4h.5l.2 .2v.3l-.2 .2M124.9 61.2v-.8l.5 .5 .2-.5h.3l.3 .3v.3l-.2 .2M126 61.7h.2M129.5 60.8l.7-.1v-.4l-.7-.1v1.2"/>
<path d="M129.9 60.8l.3 .6M130.7 60.5l.4-.3v1.2M130.7 61.4h.7M132.5 60.2h-.6l-.1 .5h.7v.5l-.2 .2h-.3l-.2-.2M132.5 63.8l.1 1.1h.4l.2-.1v-1M133.7 64.1l.3-.3v1.1M133.7 64.9h.7M134.3 74.7a.45 .45 0 0 0-.7 .1v.7a.45 .45 0 0 0 .7 .2v-.4h-.2M135.5 74.6v1.2l-.6-1.2v1.2M135.5 63.9l-.2-.1a.67 .67 0 0 0-.5 .5 .67 .67 0 0 0 .2 .6h.5M135.9 79.7v.9M136.1 74.6a.61 .61 0 0 1 .7 .6 .61 .61 0 0 1-.7 .6z"/>
<path d="M136.8 79.4h.8l-.4 .4 .4 .3-.1 .4h-.7M137.9 79.4l.4 1.2 .5-1.2M139 79.4h.8l-.4 .4 .4 .3-.1 .4h-.7M145.3 77h.8l-.5 1.2M146.8 77l-.3 .8h.7M147.1 77.4v.8M147.7 77v1.2h.5M148.2 74.6v1.1l.1 .1 .5-.1v-.2v-.9M148.5 77l.4 1.2 .4-1.2M149.3 74.9l.4-.3v1.2M149.3 75.8h.7M150.4 77.1l-.2-.1-.4 .1v.9a.36 .36 0 0 0 .6 .1"/>
<path d="M150.5 75.2h.5M150.9 77.3l.3-.3v1.2M150.9 78.2h.7M151.1 74.6h-.6v1.2h.6M152 77.1l.1-.1h.4l.2 .1v.4l-.7 .7h.7M153.8 77h-.6v.6l.6-.1v.6l-.5 .1-.1-.1M154.9 64.2v-.8l.5 .4v-.3l.2-.1 .5 .1-.1 .7M154.9 62.4v-.7l.5 .4 .1-.4h.5v.7M154.9 61.1h1.2M155.4 60.7l.4 .4M156 62.9h.1M156.1 60.7l-.4 .3"/>
<path d="M159.6 62h.6l.1-.5-.7-.1v1.2M159.9 62l.4 .6M160.8 61.7l.3-.3v1.2M160.8 62.6h.7M162.1 61.9l-.2-.3 .1-.2h.5l.1 .4a.51 .51 0 0 0-.6 .7h.6v-.5l-.2-.1M162.5 64.9v1.1l.2 .2h.3l.2-.2v-1.1M163.7 65.3l.4-.4v1.3M163.7 66.2h.7M164.3 75.9l-.3-.1-.3 .3v.6l.1 .3h.5v-.5h-.1M164.9 64.9a.64 .64 0 0 1 .7 .7 .64 .64 0 0 1-.7 .6zM165.6 75.8v1.2l-.8-1.2v1.2M166.1 75.8h.4l.3 .3v.6l-.2 .3h-.5z"/>
<path d="M196.8 65l-.1-.1a.64 .64 0 0 0-.6 .6 .64 .64 0 0 0 .5 .7l.2-.2v-.4h-.2M198 64.9v1.3l-.6-1.3v1.3M198.6 64.9a.64 .64 0 0 1 .7 .7 .64 .64 0 0 1-.7 .6zM249.7 74.7a.55 .55 0 0 0-.8 .5 .55 .55 0 0 0 .8 .5v-.4h-.2M250.9 74.6v1.2l-.7-1.2v1.2M251.5 74.6h.3l.3 .2v.7l-.3 .3h-.3zM135.5 80.2h.9M160.7 87.9l-.1-.1a.66 .66 0 0 0-.6 .5 .66 .66 0 0 0 .3 .7l.5-.1v-.4h-.3M162 87.8v1.2l-.7-1.2v1.2M162.6 87.8a.66 .66 0 0 1 .6 .4 .66 .66 0 0 1-.2 .8h-.4zM63.9 118.6h1M64.3 118.1v.9"/>
<path d="M66 117.9h-.6v.5l.1-.1 .5 .1v.6h-.6M66.4 117.9l.4 1.1 .4-1.1M81.9 117.9v1l-.5 .1M82.4 118.2l.3-.3v1.1M82.4 119h.7M102.4 118.6h.9M102.9 118.1v.9M104.5 117.9h-.6l-.1 .5 .2-.1h.3l.2 .1v.6h-.7M104.8 117.9l.4 1.1 .5-1.1M120.4 117.9v.8l-.2 .3h-.3M120.9 117.9h.4l.3 .3-.8 .8h.8M140.9 118.6h.8"/>
<path d="M141.3 118.1v.9M142.9 117.9h-.6l-.1 .5 .2-.1h.3l.3 .2-.1 .5h-.7M143.3 117.9l.4 1.1 .4-1.1M158.8 117.9v.8l-.1 .3h-.4M159.3 117.9h.7l-.4 .4 .3 .1v.6h-.6M178.1 118.6h.9M178.6 118.1v.9M180.2 117.9h-.6v.5l.4-.1 .3 .2-.1 .5h-.6M180.6 117.9l.3 1.1 .5-1.1M196.1 117.9v.8l-.2 .3h-.3M196.8 117.8l-.2 .8h.8M197.2 118.3v.7"/>
<path d="M216.6 118.6h.9M217 118.1v.9M218.6 117.9h-.6v.5l.4-.1 .3 .2-.1 .5h-.6M219 117.9l.5 1.1 .3-1.1M234.5 117.9v.8l-.4 .3M235.7 117.9h-.6l-.1 .5 .2-.1h.3l.2 .1v.6h-.7M67 126.3l-.4-.1-.3 .4v.6l.3 .3 .5-.2v-.4h-.3M68.2 126.2v1.3l-.6-1.3v1.3M68.7 126.2a.65 .65 0 0 1 .8 .7 .65 .65 0 0 1-.8 .6zM78.4 137.7h.5l.2-.1v-.4l-.7-.1v1.2M78.7 137.7l.4 .6M79.1 139.9l.3-.5v1.3"/>
<path d="M79.6 137.4l.3-.3v1.2M79.6 138.3h.7M80.3 139.4v1.3M80.7 139.9l-.4 .5M81.4 137.6v.1a.42 .42 0 0 1-.6 0 .42 .42 0 0 1 0-.5l.4-.1 .2 .2-.1 .9-.4 .1M87.3 138.3v1.1h.5M87.7 135.9l.6 .2 .1 .3-.1 .5-.3 .2h-.3zM88.2 138.9h.4M88.8 138.3h-.6v1.1h.6M89.2 135.8l-.3 .8h.7M89.3 138.3a.66 .66 0 0 1 .7 .4 .66 .66 0 0 1-.3 .7h-.4zM89.4 136.3v.8"/>
<path d="M105.4 126.3l-.1-.1a.64 .64 0 0 0-.6 .6 .64 .64 0 0 0 .5 .7l.3-.2v-.4h-.3M106.7 126.2v1.3l-.7-1.3v1.3M107.3 126.2a.64 .64 0 0 1 .7 .7 .64 .64 0 0 1-.7 .6zM116.9 137.7h.4l.3-.2-.1-.3-.6-.1v1.2M117.2 137.7l.4 .6M117.5 139.9l.4-.5v1.3M118 137.2h.7v.4l-.8 .7h.8M118.7 139.4v1.3M119.2 139.9l-.5 .5M119.3 137.2h.1a.6 .6 0 0 1 .6 .4 .6 .6 0 0 1-.3 .7h-.3l-.2-.2zM125.7 138.3v1.1h.6M126.2 135.9h.3l.3 .2v.7l-.3 .3h-.3z"/>
<path d="M126.7 138.9h.4M127.3 138.3h-.6v1.1h.6M127.3 135.9h.8l-.5 1.2M127.8 138.3h.3l.3 .3v.6l-.1 .2h-.5zM143.8 126.3v-.1a.64 .64 0 0 0-.6 .6 .64 .64 0 0 0 .5 .7l.2-.2v-.4h-.2M145.1 126.2v1.3l-.7-1.3v1.3M145.7 126.2a.64 .64 0 0 1 .7 .7 .64 .64 0 0 1-.7 .6zM155.4 137.7h.6v-.5l-.6-.1v1.2M155.6 137.7l.4 .6M156 139.9l.3-.5v1.3M156.5 137.2l.5-.1 .2 .2-.7 1h.7M157.2 139.4v1.3"/>
<path d="M157.6 137.4l.4-.3v1.2M157.6 139.9l-.4 .5M157.6 138.3h.7M164.2 138.3v1.1h.6M164.7 135.9a.6 .6 0 0 1 .7 .6 .6 .6 0 0 1-.7 .6zM165.2 138.9h.3M165.7 138.3h-.5v1.1h.5M166 136.4l-.2-.3 .1-.1h.6v.3l-.5 .1a.35 .35 0 0 0-.2 .3 .35 .35 0 0 0 .2 .4l.5-.1v-.5l-.2-.1M166.3 138.3a.66 .66 0 0 1 .6 .4 .66 .66 0 0 1-.2 .7h-.4zM181.1 126.3l-.1-.1a.64 .64 0 0 0-.6 .6 .64 .64 0 0 0 .5 .7l.3-.2v-.4h-.3M182.4 126.2v1.3l-.7-1.3v1.3M183 126.2h.2l.4 .4v.6l-.4 .3h-.2z"/>
<path d="M192.6 137.7h.6v-.5l-.6-.1v1.2M192.9 137.7l.4 .6M193.2 139.9l.3-.5v1.3M193.7 137.2l.5-.1 .3 .2-.8 1h.8M194.5 139.4v1.3M194.9 137.2l.4-.1 .3 .3-.8 .9h.8M194.9 139.9l-.4 .5M201.4 138.3v1.1h.6M201.9 135.9a.6 .6 0 0 1 .7 .6 .6 .6 0 0 1-.7 .6zM202.4 138.9h.4M202.9 138.3h-.5v1.1h.5M203.5 138.3a.66 .66 0 0 1 .7 .4 .66 .66 0 0 1-.2 .7h-.5z"/>
<path d="M203.7 136.4l-.2 .2h-.2l-.3-.2 .1-.4h.6v.8l-.5 .3M219.6 126.3l-.3-.1-.4 .4v.6l.4 .3 .3-.1v-.5h-.1M220.9 126.2v1.3l-.8-1.3v1.3M221.4 126.2h.3l.4 .4v.6l-.4 .3h-.3zM231.1 137.7h.5l.1-.1v-.4l-.6-.1v1.2M231.4 137.7l.3 .6M231.7 139.9l.4-.5v1.3M232.2 137.2l.5-.1 .2 .3-.7 .9h.7M232.9 139.4v1.3M233.3 137.1h.7l-.3 .5 .3 .1v.5h-.7M233.3 139.9l-.4 .5M239.8 135.9h.3l.3 .2v.7l-.3 .3h-.3z"/>
<path d="M239.9 138.3v1.1h.5M240.9 138.9h.4M241 136.2l.3-.3v1.2M241 137.1h.6M241.5 138.3h-.6v1.1h.6M242 138.3a.66 .66 0 0 1 .6 .4 .66 .66 0 0 1-.2 .7h-.4zM242.2 136l.3-.1 .2 .2v.7l-.3 .3a.7 .7 0 0 1-.2-1.1zM79.1 140.7h.7M80.3 140.2l.4 .5M89.8 146.7h-.5a.66 .66 0 0 0-.2 .7 .66 .66 0 0 0 .6 .5l.1-.1v-.4h-.1M91 146.7v1.2l-.7-1.2v1.2M91.6 146.7h.5l.2 .3v.6l-.4 .3h-.3z"/>
<path d="M117.5 140.7h.7M118.9 140.2l.3 .5M128.3 146.7h-.5l-.2 .3v.6l.2 .2h.6v-.4h-.3M129.5 146.7v1.2l-.6-1.2v1.2M130 146.7h.6a.66 .66 0 0 1 .2 .8 .66 .66 0 0 1-.8 .4zM156 140.7h.6M157.3 140.2l.3 .5M166.7 146.7h-.4a.67 .67 0 0 0-.3 .7 .67 .67 0 0 0 .5 .5l.3-.1v-.4h-.3M168 146.7v1.2l-.7-1.2v1.2M168.6 146.7h.4a.66 .66 0 0 1 .2 .8 .66 .66 0 0 1-.6 .4zM193.2 140.7h.8M194.6 140.2l.3 .5"/>
<path d="M204 146.7h-.5a.67 .67 0 0 0-.2 .7 .67 .67 0 0 0 .5 .5l.2-.1v-.4h-.2M205.2 146.7v1.2l-.6-1.2v1.2M205.8 146.7h.4a.66 .66 0 0 1 .3 .8 .66 .66 0 0 1-.7 .4zM231.7 140.7h.7M233 140.2l.3 .5M242.4 146.7h-.4a.67 .67 0 0 0-.3 .7 .67 .67 0 0 0 .5 .5l.3-.1v-.4h-.3M243.7 146.7v1.2l-.7-1.2v1.2M244.3 146.7h.4a.66 .66 0 0 1 .2 .8 .66 .66 0 0 1-.6 .4z"/>
</g>
</svg>
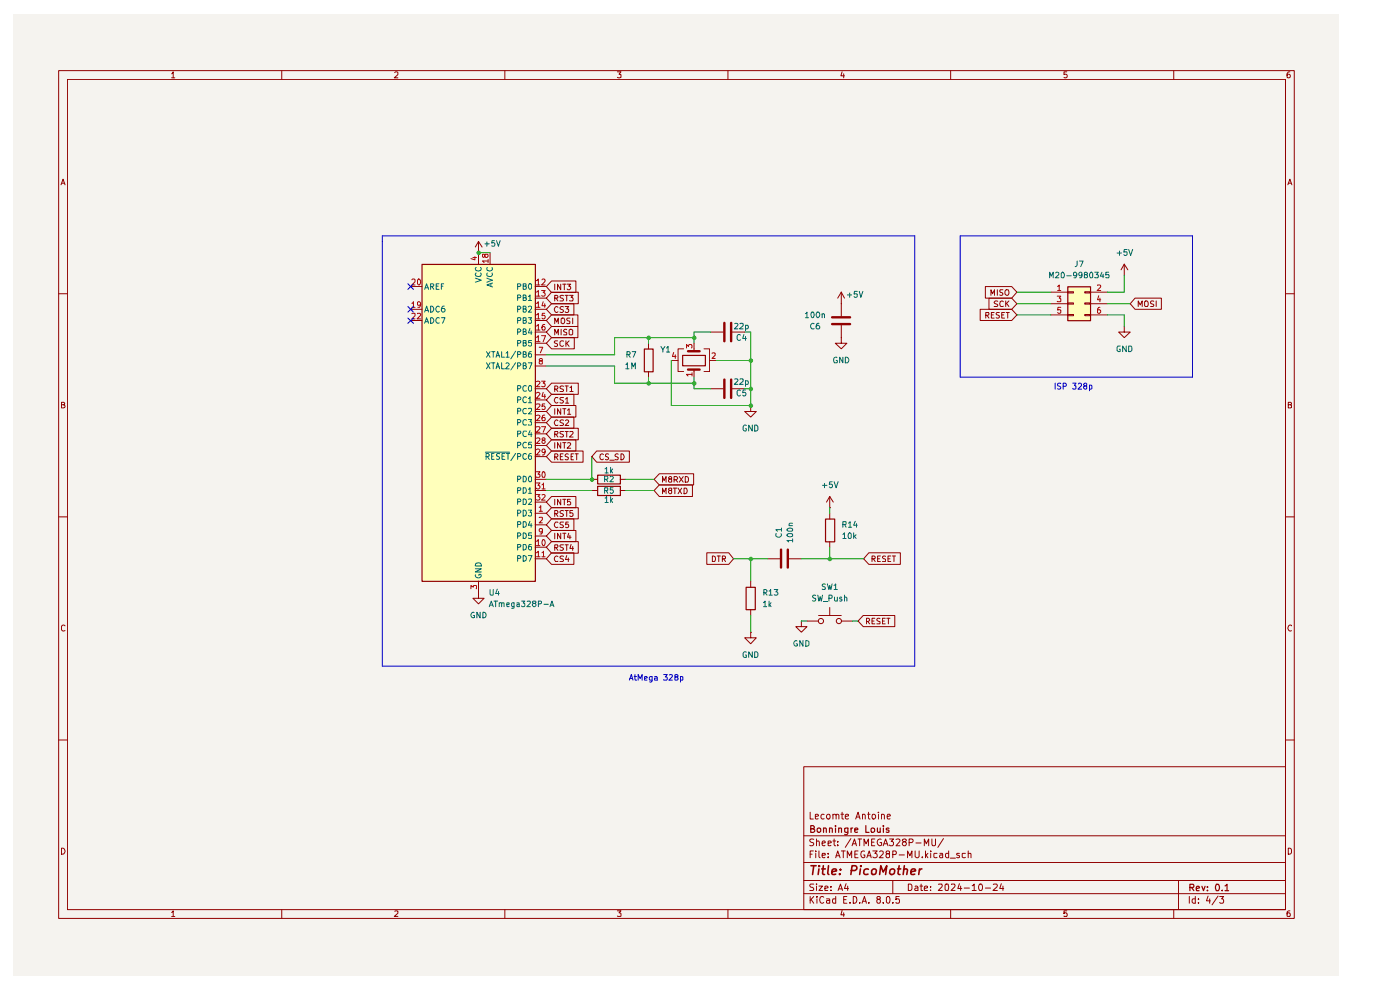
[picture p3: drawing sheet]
<svg xmlns="http://www.w3.org/2000/svg" width="297mm" height="210mm" viewBox="0 0 297 210" stroke-linecap="round" stroke-linejoin="round" font-family="sans-serif">
<path d="M2.9 3h281.2v203.8h-281.2z" fill="#f5f3ef"/>
<g fill="none" stroke="#910000" stroke-width=".21">
<path d="M12.4 15h262.2v179.8h-262.2zM14.3 16.8h258.4v176.2h-258.4zM36.4 15.7l.3-.5v1.3M36.4 16.5h.7M59.8 15v1.8M83.7 15.4l.2-.2h.3l.2 .2v.4l-.8 .7h.8M107.1 15v1.8M131 15.2h.7l-.4 .5 .4 .1v.6h-.7M154.4 15v1.8M178.6 15.2l-.2 .9h.8M179 15.7v.8M201.7 15v1.8"/>
<path d="M226.3 15.2h-.6v.6l.4-.1 .3 .3-.1 .4h-.6M249 15v1.8M273.6 15.2l-.4 .1-.2 .3v.8h.6v-.6l-.4-.1-.2 .3M13 39.2l.4-1.2 .4 1.2M13.1 38.9h.6M273.2 39.2l.4-1.2 .5 1.2M273.3 38.9h.6M12.4 62.3h1.9M272.7 62.3h1.9M13 85.8h.5l.2-.3-.2-.2h-.5v1.2h.5l.3-.4-.3-.3M273.3 85.8h.5l.2-.3-.2-.2h-.5v1.2h.5l.2-.1v-.4l-.3-.2M12.4 109.6h1.9"/>
<path d="M272.7 109.6h1.9M13.8 132.8l-.4-.2-.4 .3 .1 .8 .3 .2 .4-.1M274 132.8l-.2-.2a.6 .6 0 0 0-.6 .7 .6 .6 0 0 0 .8 .5M12.4 157h1.9M272.7 157h1.9M13 179.9a.65 .65 0 0 1 .8 .6 .65 .65 0 0 1-.8 .7zM170.5 162.6h102.2v30.4h-102.2zM170.5 177.3h102.2M171.9 172.3v1.4h.6M172.6 178.1h-.7l-.1 .3 .2 .2 .5 .1 .1 .4-.3 .3-.5-.1M173 173.2l.6-.1v-.3h-.6v.8h.6M173.2 178.6l.2-.2 .3 .1 .1 .9"/>
<path d="M173.2 178v1.4M174.4 178.9l.7-.2-.2-.3-.4 .1-.1 .7 .3 .2 .3-.1M174.8 172.8l-.4-.1a.6 .6 0 0 0 0 1l.4-.1M175.7 178.9l.7-.2-.1-.2h-.6v.8h.6M176.7 172.9l.1-.1a.36 .36 0 0 1 .6 .2v.7M176.7 178.4h.6M176.7 172.7v1M177 178v1.2l.3 .2M177.4 173v-.2a.36 .36 0 0 1 .6 .2v.7M177.7 179.2v.2M177.7 178.5v.1M178.4 172.7h.6"/>
<path d="M178.6 172.3v1.3l.4 .1M179.3 173.2l.7-.1v-.3l-.4-.1-.3 .3 .1 .6h.6M180.5 177.9l-1.2 1.8M180.8 179.4l.5-1.4 .4 1.4M180.9 179h.7M181.5 173.7l.5-1.4 .5 1.4M181.7 173.3h.7M182 178h.8M182.4 178v1.4M183 172.9l.1-.2 .4 .1 .1 .9M183 172.7v1M183.3 179.4v-1.4l.4 1 .5-1v1.4"/>
<path d="M184.1 172.7h.5M184.2 172.3v1.2l.4 .2M184.9 178.6h.5M185.6 178h-.7v1.4h.7M186.3 172.3v.1M186.3 172.7v1M186.9 178.1a.66 .66 0 0 0-.8 .6 .66 .66 0 0 0 .8 .6l.1-.6h-.3M187 172.9v-.1a.36 .36 0 0 1 .6 .2v.7M187 172.7v1M187.4 179.4l.5-1.4 .5 1.4M187.5 179h.7M188.2 173.2l.7-.1-.2-.4-.4 .1-.1 .7 .2 .2 .4-.1"/>
<path d="M188.7 178h.9l-.5 .5h.2l.3 .2-.1 .5-.2 .2h-.4l-.2-.2M190.1 178.1l.6-.1 .2 .2-.1 .4-.7 .8h.8M191.8 178.6l-.4-.3a.43 .43 0 0 1 .5-.3 .43 .43 0 0 1 .4 .3l-.3 .3a.45 .45 0 0 0-.5 .1 .45 .45 0 0 0 0 .5l.3 .2a.47 .47 0 0 0 .5-.6l-.3-.2M192.9 178.7h.6a.45 .45 0 0 0 .1-.6l-.7-.1v1.4M194.3 178.8h1.1M196.1 179.4v-1.4l.4 1 .5-1v1.4M197.7 178v1.1l.2 .3 .6-.2v-1.2M200.1 177.9l-1.1 1.8M273.3 179.9l.5 .1 .2 .3v.5l-.4 .4h-.3zM36.4 193.5l.3-.3v1.2M36.4 194.4h.7M59.8 193v1.8"/>
<path d="M83.7 193.3h.7v.4l-.8 .7h.8M107.1 193v1.8M131 193.2h.7l-.4 .4 .4 .2v.5h-.7M154.4 193v1.8M170.5 189.6h102.2M170.5 186.8h102.2M170.5 183h102.2M171.9 190.2v1.4M171.9 181.2h.4M172 190.8l.6 .8M172.5 180.5h-.6v1.4M172.6 187.5l-.7 .1v.4l.6 .3 .1 .3-.1 .3h-.7"/>
<path d="M172.6 190.2l-.7 .8M173.1 180.5v.2M173.1 181v.9M173.2 187.5v.1M173.2 188v.9M173.3 190.2v.1M173.3 190.7v.9M173.7 188h.8l-.8 .9h.8M173.7 180.5v1.2l.3 .2M174.4 181.4h.7l-.1-.4h-.5l-.1 .2 .1 .7h.5M174.7 190.3l-.4-.1a.7 .7 0 0 0-.4 .8 .7 .7 0 0 0 .8 .5v-.1M175 188.5l.7-.2-.1-.3h-.6v.9h.6"/>
<path d="M175.3 190.7h.6l.1 .9M175.7 181.8v.1M175.7 181v.2M176 191l-.7 .1v.4h.7M176.3 188.8v.1M176.3 188v.2M177.3 190.7h-.6l-.1 .2 .1 .6h.6M177.3 181.9l.4-1.4 .5 1.4M177.3 190.2v1.4M177.4 181.5h.7M177.8 188.9l.5-1.4 .4 1.4M178 188.5h.6"/>
<path d="M178.5 180.5h.8M178.6 193.1l-.2 1h.8M178.9 180.5v1.4M179 193.6v.8M179 190.8h.5M179.5 187.4l-.3 1.1h.8M179.7 190.2h-.7v1.4h.7M179.7 181.9v-1.4l.6 1 .4-1v1.4M179.8 188v.9M180.3 191.4v.2M181 190.2h.4a.75 .75 0 0 1 .4 .8 .75 .75 0 0 1-.8 .6zM181.4 181.2h.5"/>
<path d="M182 180.5h-.6v1.4h.6M182.4 191.4v.2M182.9 191.6l.5-1.4 .4 1.4M183 191.2h.7M183.4 180.6l-.4-.1a.7 .7 0 0 0-.4 .8 .7 .7 0 0 0 .8 .6l.1-.5h-.3M183.9 181.9l.5-1.4 .4 1.4M184.1 181.5h.6M184.3 191.4v.2M185.2 180.5h.9l-.5 .5 .4 .2 .1 .5a.59 .59 0 0 1-.9 .1M186.3 190.8l-.3-.3 .3-.3h.4v.5a.56 .56 0 0 0-.6 .2 .56 .56 0 0 0 0 .6h.6l.1-.5-.3-.2M186.6 180.7l.2-.2 .5 .1 .1 .5-.9 .8h.9M187.4 191.4v.2"/>
<path d="M188 190.4l.4-.2a.8 .8 0 0 1 .4 .7 .8 .8 0 0 1-.4 .7l-.4-.3zM188.2 181.1l-.2-.3 .2-.3 .5 .2-.1 .3a.56 .56 0 0 0-.5 .2 .56 .56 0 0 0-.1 .7h.5l.2-.1v-.5l-.2-.2M189.4 191.4v.2M189.4 181.3l.7-.1v-.6l-.7-.1v1.4M189.4 186.8v2.8M190.8 190.2h-.7v.6l.1-.1 .6 .1v.7l-.6 .1-.1-.2M190.8 181.4h1.1M192.5 181.9v-1.4l.5 1 .5-1v1.4M192.7 187.5h.5l.3 .4v.6l-.3 .4h-.5zM194.1 188h.4l.2 .2v.7h-.6v-.4l.6-.2M194.1 180.5v1.2l.4 .2h.2l.3-.2v-1.2M195.2 188h.5"/>
<path d="M195.4 187.5v1.4h.3M195.7 181.8v.1M196.1 188.5l.7-.2v-.3h-.5l-.2 .2 .1 .7h.6M196.3 180.5v1.4M196.4 181.4l.4 .5M196.8 181l-.5 .5M197.4 188.8v.1M197.4 188v.2M197.4 180.5v.2M197.4 181v.9M198.8 181l-.7 .1v.7l.3 .1h.4M199.1 187.6l.7-.1 .1 .4-.9 1h.9"/>
<path d="M199.4 181h.5l.1 .9M200 181.4h-.5l-.2 .2 .2 .3h.5M200.6 187.6h.6v.8l-.1 .5h-.4l-.2-.3zM201.2 181h-.5l-.1 .3v.4l.2 .2h.4M201.2 180.5v1.4M201.6 182h1.1M201.7 193v1.8M201.8 187.6l.7-.1 .1 .4-.8 1h.8M203.5 187.4l-.3 1.1h.8M203.5 181h-.5l-.1 .2 .6 .3v.4h-.6M203.8 188v.9M204.6 188.4h1.1"/>
<path d="M204.8 181l-.7 .1v.7l.3 .1h.4M205.4 181.1l.5-.1 .1 .9M205.4 180.5v1.4M206.2 187.9l.5-.4v1.4M206.2 188.9h.9M207.9 187.5a.73 .73 0 0 1 .6 .6 .73 .73 0 0 1-.3 .8h-.3l-.3-.5zM209 188.4h1.1M210.7 187.6l.7-.1 .2 .4-.1 .2-.9 .8h1M212.4 187.4l-.3 1.1h.8M212.8 188v.9M226.3 193.2h-.6v.6l.2-.2 .4 .1v.7l-.6-.1M249 193v1.8"/>
<path d="M250 186.8v6.2M252.3 190.2v1.4M253.6 190.7h-.5l-.2 .2v.4l.2 .3 .5-.1M253.6 190.2v1.4M254.3 191.4v.2M254.3 190.7v.1M256.3 190.1l-.4 1h.9M256.6 190.7v.9M258.4 190.1l-1.3 1.8M258.7 190.2h.9l-.4 .5 .3 .1v.7l-.6 .1-.2-.2M273.6 193.2l-.6 .3v.8l.6 .1v-.7l-.4-.1-.2 .3"/>
<circle cx="175.7" cy="173.3" r=".48"/>
<circle cx="185.4" cy="173.3" r=".48"/>
</g>
<g fill="none" stroke="#910000" stroke-width=".25">
<path d="M172 175.8l.7-.1 .1-.3-.3-.3h-.5v1.5h.5l.3-.3v-.2l-.3-.3M173.4 175.7l.5-.1 .2 .3v.4l-.2 .3h-.3l-.2-.3zM174.7 175.7l.4-.1 .2 .2v.8M174.7 175.6v1M176 175.7l.4-.1 .2 .2v.8M176 175.6v1M177.2 175.1v.2M177.2 175.6v1M177.9 175.7h.6v.9M177.9 175.6v1M179.9 175.6l-.1 1.3-.3 .2-.3-.1M179.9 175.7h-.7v.7l.2 .2 .5-.1"/>
<path d="M180.5 175.6v1M180.9 175.6l-.4 .1v.2M181.3 176.1l.7-.1-.2-.4-.5 .2v.6l.3 .2 .3-.1M183.7 175.1v1.5h.7M184.9 175.7h.6v.6a.45 .45 0 0 1-.6 .2zM186.1 175.6v.8l.2 .2 .4-.2M186.7 175.6v1M187.4 175.1v.2M187.4 175.6v1M188.6 175.7l-.3-.1-.3 .2 .1 .3h.5v.4h-.6M252.4 188.3h.7l.2-.3-.1-.3-.8-.1v1.3M252.8 188.3l.5 .6"/>
<path d="M253.8 188.5l.7-.2-.2-.3-.4 .1-.1 .7 .1 .1h.5M255 188l.3 .9 .3-.9M256.2 188.8v.1M256.2 188.1v.2M258 187.6a.73 .73 0 0 1 .8 .5 .73 .73 0 0 1-.4 .8h-.4l-.2-.5zM259.3 188.8v.1M259.9 187.9l.4-.3v1.3M259.9 188.9h.7"/>
</g>
<g fill="none" stroke="#910000" stroke-width=".34">
<path d="M172 183.6h1.1M172.6 183.6l-.2 1.9M173.7 184.3l-.1 1.2M173.8 183.6l-.1 .2 .2-.1-.1-.1-.1 .2M174.3 184.3h.8M174.7 183.6l-.2 1.6 .4 .3M175.8 183.6l-.2 1.6 .2 .3M176.5 184.9l1-.2-.1-.3a.6 .6 0 0 0-.9 .2v.8h.8M178.1 185.3v.2M178.3 184.4v.2M180.6 184.7l.9-.1 .3-.3-.1-.5-.3-.2h-.6l-.3 1.9M182.5 184.3l-.1 1.2"/>
<path d="M182.6 183.6v.2M184.2 184.4a.65 .65 0 0 0-.9 .3v.6a.64 .64 0 0 0 .8 .1M184.9 184.7l.4-.4 .5 .1 .1 .3-.1 .5a.56 .56 0 0 1-.9 .1zM186.6 185.5l.3-1.9 .5 1.4 .7-1.4-.2 1.9M188.9 184.5l.3-.2 .5 .2v.8l-.4 .2-.5-.2zM190.4 184.3h.7M190.8 183.6l-.3 1.6 .4 .3M191.7 184.5l.3-.2 .4 .1v1.1M191.9 183.6l-.3 1.9M193.3 184.9l.9-.2-.1-.3a.6 .6 0 0 0-.8 .2v.8h.8M195.1 184.3l-.2 1.2M195.6 184.3l-.4 .1-.1 .3"/>
</g>
<g fill="#ffb">
<path d="M89.5 56h24v67.3h-24z"/>
<path d="M226.5 60.8h4.8v7.2h-4.8z"/>
</g>
<g fill="none" stroke="#910000" stroke-width=".21">
<path d="M101.5 53.6h.1M101.5 51.2l-.7 1.2M101.5 51.2v4.8M101.5 51.2l.8 1.2M104 53.6v2.4M117 59.6h5.2v2.5h-5.2l-1.1-1.3zM238.5 58.4h.1M238.5 56l-.7 1.2M238.5 56v2.4M238.5 56l.8 1.2M87.1 60.8h2.4M87.1 65.6h2.4"/>
<path d="M87.1 68h2.4M113.5 70.4h2.4M113.5 60.8h2.4M113.5 63.2h2.4M113.5 65.6h2.4M113.5 68h2.4M113.5 72.8h2.4M113.5 75.3h2.4M113.5 77.6h2.4M117 62h5.7v2.4h-5.7l-1.1-1.2zM117 64.4h4.7v2.4h-4.7l-1.1-1.2zM117 66.8h5.6v2.5h-5.6l-1.1-1.3z"/>
<path d="M117 69.3h5.6v2.3h-5.6l-1.1-1.2zM117 71.6h4.8v2.4h-4.8l-1.1-1.2zM117.7 63.2h.6v-.5h-.6v1.1M117.7 68.7v-1.2l.4 .8 .3-.8v1.2M117.7 71v-1.2l.4 .9 .3-.9v1.2M117.7 60.3v1.2M117.9 63.2l.5 .6M118.3 72.3h-.5l-.2 .2 .2 .3 .5 .2v.3l-.2 .2-.5-.1M118.4 65.2l-.3-.2a.65 .65 0 0 0-.5 .7 .65 .65 0 0 0 .5 .6l.3-.2M119 60.3v1.2l-.7-1.2v1.2M119 67.6l.2-.1h.4l.1 .1a.65 .65 0 0 1-.4 1.1l-.3-.2zM119 69.8v1.2"/>
<path d="M119.4 60.3h.7M119.5 62.7h-.6l-.1 .3 .2 .2h.3l.2 .4-.1 .2h-.6M119.5 65.1l-.5-.1-.2 .3 .1 .2 .5 .2 .1 .3-.2 .3-.5-.1M119.5 72.4l-.5-.1-.2 .3 .1 .7 .3 .2 .3-.2M119.7 60.3v1.2M119.9 65h.7l-.4 .5h.4v.7l-.5 .1-.2-.2M119.9 62.7h.7M120.1 72.3v1.2M120.2 69.9l-.4-.1-.3 .3 .1 .3 .6 .2v.3l-.7 .1M120.2 62.7v1.1M120.2 72.8l.5 .7M120.3 60.3h.8l-.5 .4 .4 .1 .1 .4-.3 .3h-.3l-.2-.2"/>
<path d="M120.7 70l.3-.2 .5 .2v.9l-.2 .1h-.4l-.2-.1zM120.7 72.3l-.6 .7M120.8 62.7h.8l-.4 .4 .4 .2-.1 .5h-.7M120.9 67.5h-.5l-.2 .1 .3 .5 .4 .1v.4h-.7M121.5 67.5v1.2M137.6 72.8v1.2M137.6 78.8v1.2M142.4 76.5h1.4M145 74h-1.2v4.8h1.2M147.2 72.8v1.7M147.2 78.4v1.6M149.3 74h1.2v4.8h-1.2"/>
<path d="M150.5 76.5h1.5M150.8 70.4h2.6M155.4 70.4h2.6M178.5 71.6v1.2h1.2l-1.2 1.2-1.3-1.2h1.3M178.5 71.6h.1M178.5 64.4h.1M178.5 62l-.8 1.2M178.5 62v5.1M178.5 69v2.6M178.5 62l.7 1.2M207.9 65.6h6.7l1.1 1.2-1.1 1.2h-6.7zM209 60.8h5.6l1.1 1.2-1.1 1.2h-5.6z"/>
<path d="M209.1 66.9l.6-.1v-.5h-.6v1.2M209.4 66.9l.4 .6M209.8 63.2h4.8l1.1 1.2-1.1 1.2h-4.8zM210.2 62.7v-1.2l.4 .8 .4-.8v1.2M210.3 66.8h.4M210.9 66.3h-.6v1.2h.6M211.6 61.5v1.2M211.7 63.9l-.5-.1-.3 .3 .1 .2 .7 .4-.2 .3h-.6M212 66.3h-.5l-.2 .2 .2 .3 .5 .2v.3l-.2 .2-.5-.1M212.5 66.8h.4M212.8 61.5h-.6a.47 .47 0 0 0 0 .5 .47 .47 0 0 0 .5 .1v.5h-.6M212.8 64l-.2-.2a.67 .67 0 0 0-.5 .5 .67 .67 0 0 0 .2 .7l.5-.1"/>
<path d="M213.1 66.3h-.6v1.2h.6M213.3 61.6l.1-.1h.5v.1a.65 .65 0 0 1-.4 1.1l-.1-.1a.67 .67 0 0 1-.1-1zM213.4 63.8v1.2M213.4 66.3h.7M213.5 64.3l.5 .7M213.8 66.3v1.2M214 63.8l-.6 .7M222.9 66.8h3.6M222.9 62h3.6M222.9 64.4h3.6M226.5 66.7h1.2v.3h-1.2zM226.5 64.3h1.2v.2h-1.2z"/>
<path d="M226.5 61.9h1.2v.2h-1.2zM230.1 66.7h1.2v.3h-1.2zM230.1 64.3h1.2v.2h-1.2zM230.1 61.9h1.2v.2h-1.2zM231.3 66.8h3.6M231.3 62h3.6M231.3 64.4h3.6M238.5 69.3v1.1h1.3l-1.3 1.2-1.2-1.2h1.2M238.5 69.3h.1M240.8 63.2h5.6v2.4h-5.6l-1-1.2zM241.5 65v-1.2l.4 .9 .4-.9v1.2M242.8 64l.5-.2a.86 .86 0 0 1 .1 1.2h-.4l-.2-.1z"/>
<path d="M244.8 63.9l-.5-.1-.2 .2v.3l.7 .4-.2 .3h-.5M245.3 63.8v1.2M113.5 82.5h2.4M113.5 84.8h2.4M113.5 87.3h2.4M113.5 89.7h2.4M113.5 92h2.4M113.5 94.5h2.4M113.5 96.9h2.4M117 88.5h4.7v2.3h-4.7l-1.1-1.1zM117 90.8h5.7v2.5h-5.7l-1.1-1.3zM117 93.3h5.2v2.4h-5.2l-1.1-1.2z"/>
<path d="M117 95.7h6.7v2.3h-6.7l-1.1-1.1zM117 83.6h4.7v2.4h-4.7l-1.1-1.2zM117 86h5.2v2.5h-5.2l-1.1-1.2zM117 81.3h5.7v2.3h-5.7l-1.1-1.1zM117.7 92.1l.6-.1v-.5h-.6v1.2M117.7 96.9h.6v-.6h-.6v1.2M117.7 82.5h.6v-.5l-.6-.1v1.2M117.7 86.7v1.2M117.7 93.9v1.2M117.9 92.1l.5 .6M117.9 96.9l.5 .6M117.9 82.5l.5 .6"/>
<path d="M118.4 89.2l-.3-.1a.67 .67 0 0 0-.5 .5 .67 .67 0 0 0 .3 .7l.5-.1M118.4 84.4l-.5-.1a.67 .67 0 0 0-.3 .7 .67 .67 0 0 0 .5 .5l.3-.2M118.9 96.9h.4M119 93.9v1.2l-.7-1.2v1.2M119 86.7v1.2l-.7-1.2v1.2M119.4 93.9h.7M119.4 86.7h.7M119.5 96.3h-.6v1.2h.6M119.5 89.2l-.5-.1-.2 .2 .1 .3 .6 .3-.1 .4h-.6M119.5 91.5h-.5l-.2 .2 .2 .3 .5 .2v.4h-.7M119.5 84.3h-.5l-.2 .2 .2 .3 .5 .4-.2 .3-.5-.1M119.5 82h-.6v.4l.5 .1 .1 .4-.1 .2h-.6"/>
<path d="M119.7 86.7v1.2M119.7 93.9v1.2M119.9 91.5h.7M119.9 81.9h.7M120 89.2l.4-.1 .2 .3-.7 .9h.7M120 84.7l.3-.4v1.2M120 85.5h.6M120.2 81.9v1.2M120.2 91.5v1.2M120.4 94l.4-.1 .3 .3-.8 .9h.8M120.4 87l.3-.3v1.2M120.4 87.9h.7"/>
<path d="M120.6 96.3h-.5l-.2 .2 .2 .4 .5 .1v.4l-.2 .1-.5-.1M120.9 91.6l.6-.1 .1 .4-.8 .8h.8M120.9 82.2l.3-.3v1.2M120.9 83.1h.7M121.2 96.9h.3M121.7 96.3h-.5v1.2h.5M122 96.3h.7M122.3 96.3v1.2M126.6 95.7h6.9v2.3h-6.9l-1-1.1zM128 96.4l-.2-.1a.65 .65 0 0 0-.6 .6 .65 .65 0 0 0 .6 .6l.2-.1M129.1 96.3h-.6v.6l.5 .1 .1 .3-.2 .2-.5-.1M129.4 97.6h.9"/>
<path d="M131.1 96.3h-.4l-.2 .2 .1 .4 .5 .1v.4l-.1 .1-.5-.1M131.7 96.3a.64 .64 0 0 1 .7 .6 .64 .64 0 0 1-.7 .6zM150.8 82.5h2.6M155.4 82.5h2.6M159.3 86v1.3h-1.3l1.3 1.2 1.1-1.2h-1.1M159.3 86h.1M113.5 108.9h2.4M113.5 116.1h2.4M113.5 118.5h2.4M113.5 111.3h2.4M113.5 101.7h2.4M113.5 104.1h2.4"/>
<path d="M113.5 106.5h2.4M113.5 113.7h2.4M117 117.3h4.7v2.4h-4.7l-1.1-1.2zM117 114.9h5.7v2.4h-5.7l-1.1-1.2zM117 107.7h5.7v2.4h-5.7l-1.1-1.2zM117 112.5h5.2v2.4h-5.2l-1.1-1.2zM117 110.1h4.7v2.4h-4.7l-1.1-1.2zM117 105.3h5.2v2.4h-5.2l-1.1-1.2zM117.7 116.2l.6-.1v-.5h-.6v1.2M117.7 109l.6-.1v-.5l-.6-.1v1.3M117.7 105.9v1.2M117.7 113.1v1.2"/>
<path d="M117.9 116.2l.5 .6M117.9 109l.5 .6M118.4 118a.61 .61 0 0 0-.8 .3 .61 .61 0 0 0 .3 .8l.5-.1M118.4 110.8l-.5-.1a.61 .61 0 0 0-.3 .8 .61 .61 0 0 0 .8 .3M119 113.1v1.2l-.7-1.2v1.2M119 105.9v1.2l-.7-1.2v1.2M119.4 113.1h.7M119.4 105.9h.7M119.5 118h-.6l-.1 .3 .2 .2h.3l.2 .4-.1 .2h-.6M119.5 115.6h-.5l-.2 .1 .2 .4 .5 .3-.2 .4-.5-.1M119.5 108.4l-.5-.1-.2 .2 .2 .4 .5 .3-.2 .4-.5-.1M119.5 110.7h-.5l-.2 .3 .2 .3h.3l.2 .3v.2h-.7"/>
<path d="M119.7 105.9v1.2M119.7 113.1v1.2M119.9 115.6h.7M119.9 108.3h.7M120.2 117.9l-.2 .8h.7M120.2 108.3v1.3M120.2 115.6v1.2M120.6 110.7h-.5l-.1 .6 .1-.1h.5v.6h-.6M120.6 118.4v.7M120.6 113.1l-.2 .9h.8M120.9 113.5v.8M121 105.9h-.6v.6l.4-.2 .3 .3v.3l-.2 .2-.5-.1"/>
<path d="M121.2 115.5l-.3 .8h.8M121.5 108.3h-.6v.6l.4-.1 .3 .2-.1 .5-.4 .1-.2-.2M121.5 115.9v.9M125.6 101.7h1.1M125.6 104.1h1.1M131.6 101.7h1.2M131.6 104.1h1.2M139.9 100.5h7.2v2.4h-7.2l-1.1-1.2zM139.9 102.9h7v2.4h-7l-1.1-1.2zM140.5 102.3v-1.2l.4 .8 .4-.8v1.2M140.5 104.7v-1.2l.4 .9 .4-.9v1.2M142.1 101.6l-.3-.3 .3-.2h.2l.2 .4-.4 .1-.3 .3 .2 .4 .5-.1v-.4l-.2-.2"/>
<path d="M142.1 104.1l-.3-.4 .2-.2h.4l.1 .4-.7 .3v.3l.3 .2 .4-.1v-.5h-.2M142.8 103.5h.8M143 101.8h.5l.3-.5-.3-.2h-.5v1.2M143.2 103.5v1.2M143.3 101.8l.5 .5M143.8 103.5l.8 1.2M144.1 101.1l.8 1.2M144.6 103.5l-.8 1.2M144.9 101.1l-.8 1.2M145.1 103.5h.4a.66 .66 0 0 1 .3 .8 .66 .66 0 0 1-.7 .4zM145.4 101.1h.3l.3 .3v.6l-.1 .3h-.5zM149.9 117.3h4.7l1 1.2-1 1.2h-4.7z"/>
<path d="M151.1 117.9a.66 .66 0 0 1 .7 .5 .66 .66 0 0 1-.2 .7h-.5zM152.1 117.9h.7M152.5 117.9v1.2M153.2 118.5h.6v-.5l-.6-.1v1.2M153.5 118.5l.4 .6M162.8 118.5h2.6M167.4 118.5h2.6M176 107.7h.1M176 105.3v2.4M176 108.9v1.2M176 114.9v1.2M176 105.3l-.7 1.2"/>
<path d="M176 105.3l.8 1.2M184.3 117.3h6.7v2.4h-6.7l-1.1-1.2zM185 118.5h.6v-.5l-.6-.1v1.2M185.2 118.5l.5 .6M186.2 118.5h.4M186.8 117.9h-.6v1.2h.6M187.9 118l-.5-.1-.2 .3 .2 .3 .5 .2v.3l-.7 .1M188.4 118.5h.4M189 117.9h-.6v1.2h.6M189.3 117.9h.7M189.7 117.9v1.2M101.5 125.7v1.2h1.2l-1.2 1.2-1.2-1.2h1.2"/>
<path d="M101.5 125.7h.1M101.5 123.3v2.4M159.3 134.1v1.2h1.1l-1.1 1.3-1.3-1.3h1.3M159.3 134.1h.1M159.3 123.3v1.2M159.3 129.3v1.3M170 131.7v1.2h1.2l-1.2 1.2-1.2-1.2h1.2M170 131.7h.1M171.2 131.7h2.4M173.6 130.6h4.9M176 128.9v1.7M178.5 131.7h2.3"/>
<path d="M183.1 130.6h6.7v2.3h-6.7l-1.1-1.2zM183.8 131.8h.4l.3-.2-.1-.4-.6-.1v1.2M184.1 131.8l.4 .5M185 131.7h.4M185.6 131.1h-.6v1.2h.6M186.7 131.2l-.4-.1-.3 .3 .1 .3 .6 .2v.3l-.7 .1M187.2 131.7h.4M187.8 131.1h-.6v1.2h.6M188.1 131.1h.7M188.5 131.1v1.2"/>
<circle cx="174.2" cy="131.7" r=".55"/>
<circle cx="178" cy="131.7" r=".55"/>
</g>
<path d="M146 78.4h2.4M146 74.5h2.4M153.7 68.5v3.9M155.1 68.5v3.9M176.5 67.3h3.8M176.5 68.7h3.8M153.7 80.5v3.9M155.1 80.5v3.9M165.7 116.6v3.8M167.1 116.6v3.8" fill="none" stroke="#910000" stroke-width=".51"/>
<path d="M89.5 56.1h24.1v67.2h-24.1zM136.7 74h1.9v4.9h-1.9zM144.8 75.4h4.8v2.2h-4.8zM226.5 60.8h4.8v7.2h-4.8zM126.8 103.2h4.8v1.9h-4.8zM126.8 100.8h4.8v1.9h-4.8zM175.1 110.1h2v4.8h-2zM158.3 124.6h1.9v4.7h-1.9z" fill="none" stroke="#910000" stroke-width=".25"/>
<g fill="none" stroke="#b90000" stroke-width=".21">
<path d="M87.4 59.3l.1-.1h.4l.2 .1v.5l-.7 .6h.7M88.8 59.2a.68 .68 0 0 1 .4 .6 .68 .68 0 0 1-.4 .6l-.2-.2v-.8zM100.3 54.6h.8M100.8 54.4v.7l-.9-.2M102.9 54.1l.1-.2h.5v.2v.4l-.5 .1-.3-.7-.3 .1v.4l.1 .2 .4-.2M103.5 55.4h-1.1l.3 .3M103.5 55v.7M113.8 59.5l.4-.3v1.2M115 59.3l.4-.1 .3 .3-.8 .9h.8M87.4 64.3h.1l.2-.3v1.2M87.4 66.5h.7v.5l-.7 .6h.7M87.4 65.2h.7"/>
<path d="M88.6 66.5h.5l.1 .3-.7 .8h.7M89.2 64.5l-.2 .3-.4-.1v-.5l.4-.2a.81 .81 0 0 1 0 1.2h-.4M113.8 62l.4-.4v1.2M113.8 64.3l.4-.3v1.2M113.8 66.8l.4-.3v1.1M113.8 69.2l.4-.4v1.2M113.8 71.5l.4-.3v1.3M113.8 60.4h.8M113.8 62.8h.8M113.8 65.2h.8M113.8 67.6h.8M113.8 70h.8"/>
<path d="M113.8 72.5h.8M114.4 73.7h.7l-.5 1.1M114.6 76.5l-.2-.2 .2-.3h.3l.2 .5h-.5l-.2 .3 .2 .4 .5-.1v-.4l-.2-.2M114.9 61.6h.8l-.5 .5 .5 .2-.1 .4h-.7M114.9 71.2h.8l-.5 1.3M115.2 64l-.2 .9h.7M115.6 66.5h-.5l-.1 .5h.6v.6h-.5l-.1-.1M115.6 68.8l-.5 .1-.1 .4 .1 .7h.5a.43 .43 0 0 0 0-.5 .43 .43 0 0 0-.5-.2l-.1 .2M115.6 64.4v.8M142.9 74.8l-.2 .8h.7M143.3 75.3v.7M145.6 73.8v-.7l.4 .4 .1-.4h.6v.7"/>
<path d="M146.8 79.4h-1.2l.4 .4M146.8 79.1v.7M151 74.9h.7v.5l-.7 .6h.7M224.3 62.8h.7l-.3 .4 .3 .2v.5h-.7M224.4 60.8l.3-.4v1.2M224.4 61.6h.6M225 65.2h-.6v.6h.6v.5l-.1 .2h-.4l-.1-.2M232.8 60.5l.5-.1 .2 .4-.8 .8h.8M233.1 62.7l-.3 .9h.7M233.3 65.2l-.3 .1-.2 .2v.8l.5 .2 .2-.3v-.2l-.2-.3-.5 .1v.2M233.3 63.2v.8M113.8 80.9h.5l.3 .2-.8 .9h.8"/>
<path d="M113.8 83.4l.5-.2 .3 .3-.8 1h.8M113.8 85.8l.6-.1 .2 .1-.1 .4-.7 .7h.8M113.8 88.1h.5l.3 .2-.8 .9h.8M113.8 90.6l.6-.1 .2 .2-.1 .3-.7 .7h.8M113.8 93l.5-.1 .3 .2-.8 1h.8M113.8 95.4l.5-.2 .3 .3-.8 1h.8M114.9 80.9h.8l-.5 .4 .4 .1v.6h-.7M114.9 90.5h.8l-.5 1.2M115.2 83.2l-.2 .9h.7M115.2 93.4l-.2-.3a.35 .35 0 0 1 .3-.2 .35 .35 0 0 1 .4 .2l-.3 .3a.36 .36 0 0 0-.4 .4 .36 .36 0 0 0 .5 .3 .36 .36 0 0 0 .1-.6l-.2-.1M115.6 85.7h-.5l-.1 .6 .1-.2 .5 .1v.6h-.6M115.6 88.1h-.5l-.1 .5 .1 .6h.5v-.6h-.5l-.1 .1"/>
<path d="M115.6 83.6v.9M115.7 95.8a.35 .35 0 0 1-.4 .2 .35 .35 0 0 1-.3-.2l.1-.5 .3-.1a.72 .72 0 0 1 .2 .8 .72 .72 0 0 1-.5 .5M113.8 114.8l.4-.3v1.2M113.8 117.3l.4-.4v1.2M113.8 100.1h.8l-.5 .5 .5 .2v.3l-.2 .2-.6-.1M113.8 102.4h.8l-.5 .6h.4l.1 .5-.3 .2h-.3l-.2-.2M113.8 104.9h.8l-.5 .4 .5 .3-.1 .4h-.7M113.8 115.7h.8M113.8 118.1h.8M114.4 107.6h.2l.1-.3v1.2M114.4 109.8h.7v.4l-.7 .7h.7M114.4 108.5h.7"/>
<path d="M115 117.3l.3-.4v1.2M115 102.9l.3-.5v1.3M115 105l.4-.1 .3 .3-.8 .9h.8M115 118.1h.7M115 103.7h.7M115.1 100.2l.3-.1a.91 .91 0 0 1 .1 1.2l-.4-.1zM115.1 112.6l-.2 .3h-.3l-.2-.3 .1-.4h.6v.8l-.2 .3h-.3M115.2 114.5a.68 .68 0 0 1 .5 .6 .68 .68 0 0 1-.5 .6l-.2-.5 .1-.6zM99.9 124.9v-.7l.5 .3 .1-.3h.5v.7"/>
</g>
<g fill="none" stroke="#006665" stroke-width=".21">
<path d="M100.8 59l1.3 .4-1.3 .5M101 57.9l-.2 .3a.65 .65 0 0 0 .7 .5 .65 .65 0 0 0 .6-.5l-.2-.3M101 56.7l-.2 .3a.65 .65 0 0 0 .7 .5 .65 .65 0 0 0 .6-.5l-.2-.3M103.3 59l1.2 .4-1.2 .5M103.4 57.9l-.1 .5a.61 .61 0 0 0 .8 .3 .61 .61 0 0 0 .3-.8M103.4 56.7l-.1 .5a.61 .61 0 0 0 .8 .3 .61 .61 0 0 0 .3-.8M90.1 66.2l.4-1.3 .4 1.3M90.1 61.4l.4-1.2 .4 1.2M90.1 68.6l.4-1.2 .4 1.2M90.3 65.9h.5M90.3 61h.5M90.3 68.2h.5"/>
<path d="M91.4 64.9a.64 .64 0 0 1 .6 .7 .64 .64 0 0 1-.6 .6zM91.4 60.8l.5-.1 .1-.3-.1-.2h-.5v1.2M91.4 67.4h.4a.66 .66 0 0 1 .2 .7 .66 .66 0 0 1-.6 .5zM91.6 60.8l.4 .6M92.5 60.7h.5M93.1 60.2h-.6v1.2h.6M93.2 65.1l-.2-.2a.65 .65 0 0 0-.5 .7 .65 .65 0 0 0 .5 .6l.2-.2M93.2 67.5l-.5-.1a.61 .61 0 0 0-.3 .8 .61 .61 0 0 0 .8 .3M93.6 67.4h.8l-.5 1.2M93.6 60.7h.4M94.1 60.2h-.5v1.2M94.2 64.9l-.4 .2-.2 .9 .3 .2h.2l.3-.2v-.4l-.2-.2h-.4l-.2 .2"/>
<path d="M103.2 74.6l.8 1.2M103.2 77l.8 1.2M104 74.6l-.8 1.2M104 77l-.8 1.2M104.1 60.2v.5M104.3 74.6h.7M104.3 77h.7M104.5 60l-1.2 .4 1.2 .5M104.6 74.6v1.2M104.6 77v1.2M105.2 75.8l.4-1.2 .4 1.2M105.2 78.2l.4-1.2 .4 1.2"/>
<path d="M105.3 75.4h.6M105.3 77.8h.6M106.4 74.6v1.2h.6M106.4 77v1.2h.6M107.4 74.9l.3-.3v1.2M107.4 77.1l.4-.1 .2 .3-.7 .9h.7M107.4 75.8h.6M109.4 74.5l-1 1.6M109.4 77l-1 1.5M109.8 60.8l.6-.1 .1-.3-.2-.2h-.5v1.2M109.8 63.2h.5l.2-.2-.1-.3-.6-.1v1.2M109.8 65.6h.4l.3-.2-.3-.5h-.4v1.3"/>
<path d="M109.8 68h.5l.2-.4-.2-.2h-.5v1.2M109.8 70.4h.4l.3-.2-.3-.4h-.4v1.1M109.8 72.8l.6-.1 .1-.3-.2-.2h-.5v1.2M109.8 75.2h.5l.2-.2-.1-.3-.6-.1v1.2M109.8 77.6h.4l.3-.2-.3-.4h-.4v1.2M111 60.7h.5l.1-.4-.6-.1v1.2l.6-.1 .1-.3-.3-.3M111 63.2h.4l.2-.2v-.3l-.6-.1v1.2l.6-.1 .1-.4-.3-.1M111 65.5l.6-.1v-.3l-.2-.2h-.4v1.3l.6-.1 .1-.3-.3-.3M111 68h.4l.2-.2-.1-.4h-.5v1.2l.6-.1 .1-.3-.3-.2M111 70.4l.6-.1v-.4l-.2-.1h-.4v1.1h.6l.1-.3-.3-.2M111 72.7h.5l.1-.4-.6-.1v1.2l.6-.1 .1-.3-.3-.3M111 75.2h.4l.2-.2v-.3l-.2-.1h-.4v1.2l.6-.1 .1-.3-.3-.2"/>
<path d="M111 77.6l.6-.1v-.4l-.2-.1h-.4v1.2l.6-.1 .1-.3-.3-.2M112.1 62.9l.3-.3v1.2M112.1 65.1l.2-.2h.3l.2 .2v.3l-.7 .8h.7M112.1 67.4h.7l-.4 .4 .4 .2v.5h-.7M112.1 77h.8l-.6 1.2M112.1 63.8h.7M112.3 60.2h.3l.2 .2v.7l-.3 .3a.71 .71 0 0 1-.2-1.2zM112.4 69.7l-.3 .9h.8M112.7 74.6h-.3a.73 .73 0 0 0-.1 1.2l.5-.1v-.5l-.5-.2-.2 .3M112.7 70.2v.7M112.8 72.2h-.6l-.1 .5h.7v.5l-.2 .2h-.3l-.2-.2M103 95.9h5.1"/>
<path d="M103.1 96.9l.6-.1 .1-.4-.3-.2h-.4v1.2M103.4 96.9l.4 .5M104.3 96.8h.3M104.8 96.2h-.5v1.2h.5M106 96.3h-.6v.5l.5 .1 .1 .3-.3 .2h-.4M106.5 96.8h.4M107.1 96.2h-.6v1.2h.6M107.4 96.2h.7M107.8 96.2v1.2M109.4 96.2l-1 1.5M109.8 82.5h.4l.3-.3-.1-.3-.6-.1v1.2M109.8 84.8l.6-.1 .1-.3-.3-.2h-.4v1.2"/>
<path d="M109.8 87.2h.5l.2-.2-.1-.3-.6-.1v1.2M109.8 89.7h.4l.3-.3-.3-.4h-.4v1.2M109.8 92l.6-.1 .1-.3-.2-.2h-.5v1.2M109.8 94.5h.4l.3-.3-.1-.3-.6-.1v1.2M109.8 96.9l.6-.1 .1-.4-.3-.2h-.4v1.2M111.7 81.9l-.3-.1a.67 .67 0 0 0-.5 .5 .67 .67 0 0 0 .3 .7l.5-.1M111.7 84.3l-.1-.1a.61 .61 0 0 0-.7 .3 .61 .61 0 0 0 .1 .8l.3 .1 .4-.1M111.7 86.7l-.3-.1a.6 .6 0 0 0-.5 .6 .6 .6 0 0 0 .5 .6l.3-.1M111.7 89.2l-.3-.2a.67 .67 0 0 0-.5 .5 .67 .67 0 0 0 .3 .7l.5-.1M111.7 91.5l-.5-.1a.67 .67 0 0 0-.3 .7 .67 .67 0 0 0 .5 .5l.3-.1M111.7 93.9l-.3-.1a.67 .67 0 0 0-.5 .5 .67 .67 0 0 0 .3 .7l.5-.1M111.7 96.3l-.3-.1a.65 .65 0 0 0-.5 .6 .65 .65 0 0 0 .5 .6l.3-.1"/>
<path d="M112.1 84.6l.3-.4v1.2M112.1 86.7h.7v.4l-.7 .7h.7M112.1 89h.7l-.4 .5 .4 .1v.5h-.7M112.1 85.4h.7M112.3 81.9l.2-.1 .3 .2v.8l-.2 .2h-.3l-.2-.5zM112.4 91.4l-.3 .8h.8M112.7 96.2a.72 .72 0 0 0-.6 .5 .72 .72 0 0 0 .2 .7l.5-.1v-.5l-.5-.1-.2 .2M112.7 91.8v.8M112.8 93.8h-.6l-.1 .6 .2-.2h.3l.2 .2v.5h-.7M101 119.5h.9l.2 .6h-1.3zM109.8 108.9h.4l.3-.4-.3-.3h-.4v1.3M109.8 116.1l.6-.1 .1-.3-.2-.2h-.5v1.2"/>
<path d="M109.8 118.4h.5l.2-.1-.1-.4h-.6v1.1M109.8 111.2h.5l.2-.1-.2-.4h-.5v1.1M109.8 101.7h.4l.3-.4-.3-.3h-.4v1.2M109.8 104.1l.6-.1 .1-.4-.2-.1h-.5v1.1M109.8 106.4h.5l.2-.1-.1-.4-.6-.1v1.2M109.8 113.7h.4l.3-.2-.3-.5h-.4v1.2M111 108.2a.64 .64 0 0 1 .7 .6 .64 .64 0 0 1-.7 .7zM111 115.5h.4a.66 .66 0 0 1 .3 .7 .66 .66 0 0 1-.7 .5zM111 117.9l.6 .1 .1 .4-.1 .5-.4 .1h-.2zM111 110.7h.4a.66 .66 0 0 1 .3 .7 .66 .66 0 0 1-.7 .4zM111 101a.66 .66 0 0 1 .7 .4 .66 .66 0 0 1-.3 .8h-.4zM111 103.5h.4a.66 .66 0 0 1 .3 .7 .66 .66 0 0 1-.7 .4z"/>
<path d="M111 105.8a.66 .66 0 0 1 .7 .5 .66 .66 0 0 1-.3 .7h-.4zM111 113a.66 .66 0 0 1 .7 .5 .66 .66 0 0 1-.3 .7h-.4zM112.1 108.2h.7l-.4 .5 .4 .1v.5l-.2 .2h-.3l-.2-.2M112.1 117.9h.8l-.6 1.1M112.1 103.8l.3-.3v1.1M112.1 105.9h.7v.4l-.7 .7h.7M112.1 104.6h.7M112.3 101.1l.2-.1 .3 .3v.7l-.2 .2h-.3l-.2-.4zM112.4 110.6l-.3 .8h.8M112.7 115.5l-.4 .1a.82 .82 0 0 0 0 1.1l.5-.2v-.5l-.5-.1-.2 .3M112.7 111.1v.7M112.8 113h-.6l-.1 .6 .6-.1 .1 .6h-.7"/>
<path d="M100.8 120.6h1.3l-1.3 .7h1.3M100.9 121.9l-.1 .1a.6 .6 0 0 0 .7 .6 .6 .6 0 0 0 .5-.7l-.4-.1v.3"/>
</g>
<g fill="none" stroke="#090" stroke-width=".21">
<path d="M101.5 53.6h2.5M238.5 58.4v3.6h-3.6M115.9 77.6h14.5v3.7h16.8M137.6 71.6v1.2M147.2 71.6h-16.8v3.7h-14.5M150.8 70.4h-3.6v2.4M152 76.5h7.3M158 70.4h1.3v15.6h-16.9v-9.5M215.7 64.4h7.2M215.7 66.8h7.2M215.7 62h7.2M234.9 64.4h4.9"/>
<path d="M234.9 66.8h3.6v2.5M125.6 96.9v4.8h-9.7M137.6 80v1.3M147.2 80v2.5h3.6M158 82.5h1.3M115.9 104.1h9.7M132.8 101.7h6M132.8 104.1h6M155.6 118.5h7.2M159.3 118.5v4.8M170 118.5h13.2M176 107.7v1.2"/>
<path d="M176 116.1v2.4M159.3 130.6v3.5M170 131.7h1.2M180.8 131.7h1.2"/>
</g>
<g fill="none" stroke="#0000ca" stroke-width=".21">
<path d="M81.1 50h113v91.3h-113zM203.7 50h49.3v30h-49.3zM223.9 81.3v1.2M225 81.4l-.4-.1-.2 .1v.4l.6 .4-.2 .3h-.4M225.5 82l.6-.1v-.5l-.6-.1v1.2M227.6 81.3h.7l-.4 .5 .4 .1v.5l-.2 .1h-.4l-.1-.1M228.8 81.4l.4-.1 .2 .4-.7 .8h.7M230.1 81.9l-.2-.4 .2-.2h.3l.1 .4-.6 .3v.3l.2 .2 .4-.1v-.4l-.1-.1M231.1 81.8l.4-.1 .1 .2v.5l-.1 .1h-.4M231.1 81.7v1.2M133.5 144.3l.4-1.2 .4 1.2M133.6 143.9h.6"/>
<path d="M134.5 143.5h.5M134.7 143.1v1l.1 .2h.2M135.4 144.3v-1.2l.4 .8 .4-.8v1.2M136.7 143.9l.6-.1-.1-.3-.5 .1v.7h.5M138.3 143.5v.9l-.2 .3-.3-.1M138.3 143.6a.36 .36 0 0 0-.6 .2l.1 .5h.5M138.9 143.6l.4-.1 .1 .2v.6h-.5v-.4l.5-.1M140.8 143.1h.8l-.5 .5 .5 .2v.3l-.2 .2-.6-.1M142 143.2l.4-.1 .3 .3-.8 .9h.8M143.3 143.6l-.1-.1v-.3h.6v.2l-.6 .4 .1 .5h.4l.1-.2v-.3l-.2-.2M144.4 143.6h.5v.6l-.5 .1M144.4 143.5v1.2"/>
</g>
<path d="M86.5 67.5l1.2 1.1M86.5 65l1.2 1.2M86.5 60.2l1.2 1.2M87.7 67.5l-1.2 1.1M87.7 65l-1.2 1.2M87.7 60.2l-1.2 1.2" fill="none" stroke="#00008a" stroke-width=".21"/>
<g fill="#090">
<circle cx="101.6" cy="53.6" r=".47"/>
<circle cx="147.3" cy="71.7" r=".47"/>
<circle cx="159.3" cy="118.6" r=".47"/>
<circle cx="159.3" cy="76.5" r=".47"/>
<circle cx="159.3" cy="82.5" r=".47"/>
<circle cx="147.3" cy="81.3" r=".47"/>
<circle cx="176.1" cy="118.6" r=".47"/>
<circle cx="159.3" cy="86.1" r=".47"/>
<circle cx="137.6" cy="71.7" r=".47"/>
<circle cx="137.6" cy="81.3" r=".47"/>
<circle cx="125.6" cy="101.7" r=".47"/>
</g>
<g fill="none" stroke="#006665" stroke-width=".21">
<path d="M102.9 51.7h.9M103.3 51.3v.9M104.9 51.1h-.5l-.1 .5h.6v.6h-.6M105.3 51.1l.4 1.1 .4-1.1M222.7 58.9v-1.2l.3 .9 .4-.9v1.2M223.9 57.9l.2-.2 .4 .1 .1 .4-.7 .7h.7M225.4 57.7a.71 .71 0 0 1 .2 1.2h-.3l-.2-.1v-.8zM226.3 58.5h.9M228.4 58.2l-.2 .3-.5-.1v-.5l.5-.2a.81 .81 0 0 1 0 1.2h-.4M228.5 55.4v.8l-.4 .4M229 55.4h.8l-.5 1.2M229.5 58.2v.2l-.4 .1-.2-.1v-.4l.2-.3 .4 .2v.8l-.1 .2h-.4"/>
<path d="M230.2 58.2h-.2v-.3l.5-.2 .2 .4-.7 .3 .1 .5h.4l.2-.1v-.3l-.2-.3M231.3 57.8l.3-.1 .2 .3v.8l-.2 .1h-.3l-.2-.4zM232.2 57.7h.8l-.4 .5h.3l.1 .2-.1 .5-.7-.1M233.8 57.7l-.4 .9h.8M234 58.2v.7M235.2 57.7h-.6v.6l.6-.1v.7l-.6-.1M237 53.7h.9M237.5 53.3v.9M239.1 52.9h-.6l-.1 .6 .6-.1 .1 .6-.2 .2h-.3l-.2-.2M239.4 52.9l.5 1.3 .4-1.3M132.8 77.3h.1l.2-.3v1.2M132.8 78.2h.6"/>
<path d="M133 75.2h.6v-.5l-.6-.1v1.2M133.3 75.2l.4 .6M134 78.2v-1.2l.4 .8 .4-.8v1.2M134.1 74.6h.8l-.5 1.2M140.2 73.5l.4 .7 .5-.7M140.6 74.2v.5M141.4 73.8l.3-.3v1.2M141.4 74.7h.7M155.9 68.7l.4-.1 .2 .3-.7 .9h.7M157 68.7h.6v.4l-.7 .7h.7M157.1 71.1l-.4-.2-.3 .4 .1 .7 .2 .2 .4-.2M157.8 70.9l-.2 .9h.7"/>
<path d="M158.2 69.7a.36 .36 0 0 0 .5-.2v-.5h-.5v1.2M158.2 71.4v.8M170.9 66.5l.3-.3v1.2M170.9 67.4h.6M172.1 66.3l.1-.1a.59 .59 0 0 1 .6 .4 .59 .59 0 0 1-.2 .6l-.1 .2-.4-.2zM172.7 68.7a.61 .61 0 0 0-.8 .3 .61 .61 0 0 0 .3 .8l.5-.1M173.3 66.2a.6 .6 0 0 1 .6 .5 .6 .6 0 0 1-.4 .7 .81 .81 0 0 1-.2-1.2zM173.7 68.6l-.4 .1a.94 .94 0 0 0 0 1.1h.4l.2-.2v-.3l-.3-.3h-.2l-.3 .3M174.4 66.7l.2-.2 .3 .2v.7M174.4 66.5v.9M177.5 75.9l-.3-.1-.3 .3v.6l.1 .3 .6-.1v-.4h-.2M178.8 75.8v1.2l-.7-1.2v1.2"/>
<path d="M179.3 75.8a.66 .66 0 0 1 .7 .4 .66 .66 0 0 1-.2 .8h-.5zM179.7 62.6h1M180.3 62.1v1M181.9 61.8h-.6l-.1 .6h.7v.5l-.2 .2h-.3l-.2-.2M182.3 61.8l.3 1.3 .4-1.3M237.7 73.4h-.6l-.1 .3v.6a.45 .45 0 0 0 .7 .2v-.4h-.2M238.9 73.4v1.2l-.7-1.2v1.2M239.4 73.4h.5l.2 .3v.6l-.3 .3h-.4zM128.4 99.5l.3-.4v1.2M129.5 99.1v1.2M129.6 99.8l.4 .5M130 99.5l-.5 .5"/>
<path d="M155.9 80.4l.4-.1 .2 .4-.7 .8h.7M157 80.4h.6v.5l-.7 .6h.7M157.1 82.9l-.4-.2-.3 .4 .1 .7 .2 .2 .4-.2M158.2 81.5h.5v-.7h-.5v1.2M158.2 82.7h-.6v.6h.6v.6l-.5 .1-.1-.2M158.3 90.3a.42 .42 0 0 0-.7 .2v.6l.2 .3h.5v-.5h-.1M159.6 90.2v1.2l-.8-1.2v1.2M160.1 90.2l.5 .1 .2 .2v.6l-.4 .3h-.3zM128.3 104.1l.6-.1v-.5h-.6v1.1M128.3 101.7h.5l.1-.2v-.3l-.1-.2h-.5v1.2M128.4 105.7l.3-.4v1.3M128.4 106.6h.6"/>
<path d="M128.4 100.3h.6M128.6 104.1l.3 .5M128.6 101.7l.3 .5M129.5 101.2l.4-.2 .2 .3-.7 .9h.7M129.5 105.3v1.3M129.6 106.1l.4 .5M130 105.7l-.5 .5M130 103.5h-.5v.5h.5l.1 .4-.2 .2-.4-.1M164.7 113.2l-.1 .5a.61 .61 0 0 0 .8 .2 .61 .61 0 0 0 .3-.7M165.8 112.3h-1.2l.3 .4M165.8 112v.7M167 112.2l.7-.2 .4 .2v.3l-.1 .2h-.8l-.2-.3z"/>
<path d="M167.2 113.2h.8l.1 .2v.3a.75 .75 0 0 1-1.1-.2zM167.4 111.5h.7M168.1 114.6h-1.1l.3 .4M168.1 111h-.5l-.2 .2 .1 .3M168.1 114.3v.7M174.5 103h.9M174.9 102.5v1M176.5 102.2h-.5l-.1 .6h.6v.6l-.4 .1-.2-.2M177 102.2l.4 1.3 .4-1.3M178.8 113.4l.4-.4v1.2M178.8 111.2h.6l.1-.5h-.7v1.1M178.8 114.2h.7"/>
<path d="M179.2 111.2l.3 .6M180 111l.3-.3v1.1M180 111.8h.7M180.1 113.1l.2-.1 .3 .3v.7l-.2 .2-.4-.1-.1-.6zM181.1 113v1.2M181.3 113.8l.3 .4M181.4 110.6l-.3 .8h.8M181.6 113.5l-.5 .4M181.7 111.1v.7M100.6 130a.54 .54 0 0 0-.7 .5 .54 .54 0 0 0 .8 .5v-.4h-.3M101.9 129.9v1.2l-.7-1.2v1.2M102.4 129.9l.6 .1 .1 .4-.1 .5-.3 .2h-.3z"/>
<path d="M103.8 128.7l.4-1.2 .4 1.2M104 125v1.1l.1 .1h.5v-1.2M104 128.4h.5M104.8 127.5h.8M105.2 127.5v1.2M105.5 125l-.3 .9h.7M105.7 125.5v.7M105.9 128l.2-.2 .3 .1v.8M105.9 127.8v.9M106.4 128l.2-.2 .3 .1v.8M107.5 128.3l.5-.1v-.3h-.5v.7h.5M109 127.8v1.1l-.5 .1"/>
<path d="M109 127.9l-.3-.1-.2 .2v.5l.2 .2 .3-.1M109.6 127.9h.5v.8M110.1 128.2l-.5 .1v.3h.5M110.7 127.5h.6l-.3 .4 .3 .1v.5l-.1 .2h-.4l-.1-.2M111.8 127.6l.6-.1 .1 .3-.7 .9h.7M113.2 128l-.3-.2 .2-.3h.4l.2 .2-.2 .3h-.4l-.2 .2v.2l.3 .3h.3l.2-.3v-.2l-.2-.2M114.2 128.1l.6-.1 .1-.3-.2-.2h-.5v1.2M115.4 128.2h.9M116.7 128.7l.4-1.2 .4 1.2M116.8 128.4h.5M158.3 138.3h-.3l-.4 .3v.6l.2 .2h.5v-.5h-.1M159.6 138.3v1.1l-.8-1.1v1.1"/>
<path d="M160.1 138.3h.3l.4 .3v.6l-.2 .2h-.5zM162 127.8l.3-.3v1.2M162 128.7h.6M162 125.7h.5l.2-.2-.2-.5h-.5v1.2M162.3 125.7l.4 .5M163.1 125.4l.4-.4v1.2M163.1 127.5v1.2M163.1 126.2h.7M163.2 128.2l.4 .5M163.6 127.8l-.5 .6M164.3 125h.7l-.4 .6 .4 .1v.4l-.2 .1h-.5M169.1 136a.54 .54 0 0 0-.7 .5 .54 .54 0 0 0 .8 .5v-.4h-.3"/>
<path d="M170.3 135.9v1.2l-.6-1.2v1.2M170.9 135.9l.7 .2v.7l-.4 .3h-.3zM173.1 126.3h-.6v.4l.5 .2 .1 .4-.3 .2-.4-.1M173.5 126.2l.2 1.3 .3-.9 .2 .9 .3-1.3M174.7 127.6h.9M175.1 123.9h-.4l-.3 .2 .3 .4 .4 .1v.4h-.7M175.5 123.9l.3 1.1 .2-.8 .3 .8 .2-1.1M175.8 126.9h.6l.1-.2v-.3l-.1-.2h-.6v1.3M177 124.2l.3-.3v1.1M177 125h.6M177 126.7v.6l.2 .2 .4-.2M177.6 126.7v.8"/>
<path d="M178.6 126.7h-.5v.3l.5 .1v.2l-.1 .2-.4-.1M179.2 126.7h.3l.2 .1v.7M179.2 126.2v1.3"/>
</g>
</svg>
